VERSION 5.8 ;
BUSBITCHARS "[]" ;
DIVIDERCHAR "/" ;
UNITS
    DATABASE MICRONS 1000 ;
END UNITS

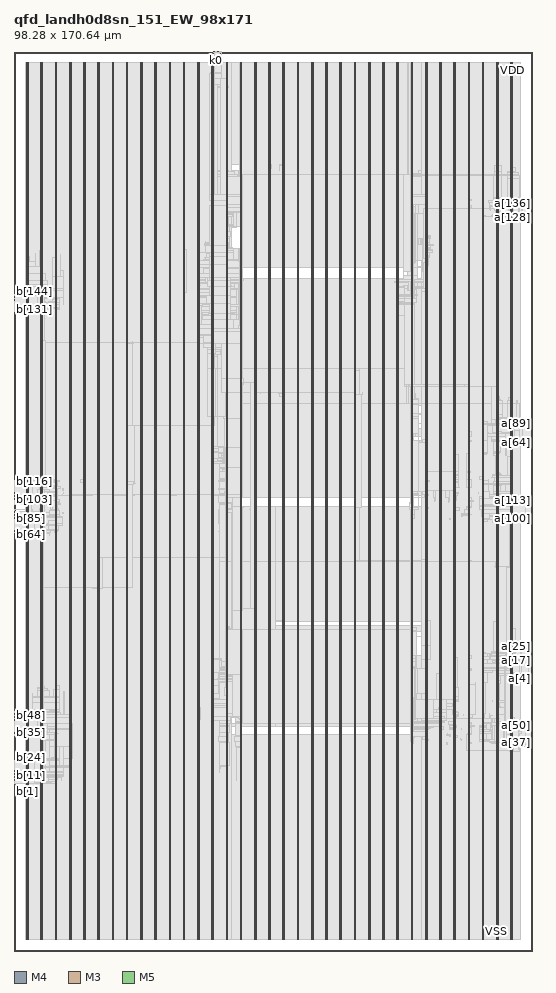
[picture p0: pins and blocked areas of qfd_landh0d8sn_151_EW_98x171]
MACRO qfd_landh0d8sn_151_EW_98x171
  FOREIGN qfd_landh0d8sn_151_EW_98x171 0 0 ;
  CLASS BLOCK ;
  SIZE 98.28 BY 170.64 ;
  PIN a[0]
    DIRECTION INPUT ;
    USE SIGNAL ;
    PORT
      LAYER M4 ;
        RECT  98.196 52.56 98.28 52.584 ;
    END
  END a[0]
  PIN a[100]
    DIRECTION INPUT ;
    USE SIGNAL ;
    PORT
      LAYER M4 ;
        RECT  98.196 81.936 98.28 81.96 ;
    END
  END a[100]
  PIN a[101]
    DIRECTION INPUT ;
    USE SIGNAL ;
    PORT
      LAYER M4 ;
        RECT  98.196 82.08 98.28 82.104 ;
    END
  END a[101]
  PIN a[102]
    DIRECTION INPUT ;
    USE SIGNAL ;
    PORT
      LAYER M4 ;
        RECT  98.196 82.224 98.28 82.248 ;
    END
  END a[102]
  PIN a[103]
    DIRECTION INPUT ;
    USE SIGNAL ;
    PORT
      LAYER M4 ;
        RECT  98.196 82.368 98.28 82.392 ;
    END
  END a[103]
  PIN a[104]
    DIRECTION INPUT ;
    USE SIGNAL ;
    PORT
      LAYER M4 ;
        RECT  98.196 82.512 98.28 82.536 ;
    END
  END a[104]
  PIN a[105]
    DIRECTION INPUT ;
    USE SIGNAL ;
    PORT
      LAYER M4 ;
        RECT  98.196 82.656 98.28 82.68 ;
    END
  END a[105]
  PIN a[106]
    DIRECTION INPUT ;
    USE SIGNAL ;
    PORT
      LAYER M4 ;
        RECT  98.196 82.8 98.28 82.824 ;
    END
  END a[106]
  PIN a[107]
    DIRECTION INPUT ;
    USE SIGNAL ;
    PORT
      LAYER M4 ;
        RECT  98.196 82.944 98.28 82.968 ;
    END
  END a[107]
  PIN a[108]
    DIRECTION INPUT ;
    USE SIGNAL ;
    PORT
      LAYER M4 ;
        RECT  98.196 83.088 98.28 83.112 ;
    END
  END a[108]
  PIN a[109]
    DIRECTION INPUT ;
    USE SIGNAL ;
    PORT
      LAYER M4 ;
        RECT  98.196 83.232 98.28 83.256 ;
    END
  END a[109]
  PIN a[10]
    DIRECTION INPUT ;
    USE SIGNAL ;
    PORT
      LAYER M4 ;
        RECT  98.196 54 98.28 54.024 ;
    END
  END a[10]
  PIN a[110]
    DIRECTION INPUT ;
    USE SIGNAL ;
    PORT
      LAYER M4 ;
        RECT  98.196 83.376 98.28 83.4 ;
    END
  END a[110]
  PIN a[111]
    DIRECTION INPUT ;
    USE SIGNAL ;
    PORT
      LAYER M4 ;
        RECT  98.196 83.52 98.28 83.544 ;
    END
  END a[111]
  PIN a[112]
    DIRECTION INPUT ;
    USE SIGNAL ;
    PORT
      LAYER M4 ;
        RECT  98.196 83.664 98.28 83.688 ;
    END
  END a[112]
  PIN a[113]
    DIRECTION INPUT ;
    USE SIGNAL ;
    PORT
      LAYER M4 ;
        RECT  98.196 83.808 98.28 83.832 ;
    END
  END a[113]
  PIN a[114]
    DIRECTION INPUT ;
    USE SIGNAL ;
    PORT
      LAYER M4 ;
        RECT  98.196 83.952 98.28 83.976 ;
    END
  END a[114]
  PIN a[115]
    DIRECTION INPUT ;
    USE SIGNAL ;
    PORT
      LAYER M4 ;
        RECT  98.196 84.096 98.28 84.12 ;
    END
  END a[115]
  PIN a[116]
    DIRECTION INPUT ;
    USE SIGNAL ;
    PORT
      LAYER M4 ;
        RECT  98.196 84.24 98.28 84.264 ;
    END
  END a[116]
  PIN a[117]
    DIRECTION INPUT ;
    USE SIGNAL ;
    PORT
      LAYER M4 ;
        RECT  98.196 84.384 98.28 84.408 ;
    END
  END a[117]
  PIN a[118]
    DIRECTION INPUT ;
    USE SIGNAL ;
    PORT
      LAYER M4 ;
        RECT  98.196 84.528 98.28 84.552 ;
    END
  END a[118]
  PIN a[119]
    DIRECTION INPUT ;
    USE SIGNAL ;
    PORT
      LAYER M4 ;
        RECT  98.196 84.672 98.28 84.696 ;
    END
  END a[119]
  PIN a[11]
    DIRECTION INPUT ;
    USE SIGNAL ;
    PORT
      LAYER M4 ;
        RECT  98.196 54.144 98.28 54.168 ;
    END
  END a[11]
  PIN a[120]
    DIRECTION INPUT ;
    USE SIGNAL ;
    PORT
      LAYER M4 ;
        RECT  98.196 84.816 98.28 84.84 ;
    END
  END a[120]
  PIN a[121]
    DIRECTION INPUT ;
    USE SIGNAL ;
    PORT
      LAYER M4 ;
        RECT  98.196 84.96 98.28 84.984 ;
    END
  END a[121]
  PIN a[122]
    DIRECTION INPUT ;
    USE SIGNAL ;
    PORT
      LAYER M4 ;
        RECT  98.196 85.104 98.28 85.128 ;
    END
  END a[122]
  PIN a[123]
    DIRECTION INPUT ;
    USE SIGNAL ;
    PORT
      LAYER M4 ;
        RECT  98.196 85.248 98.28 85.272 ;
    END
  END a[123]
  PIN a[124]
    DIRECTION INPUT ;
    USE SIGNAL ;
    PORT
      LAYER M4 ;
        RECT  98.196 85.392 98.28 85.416 ;
    END
  END a[124]
  PIN a[125]
    DIRECTION INPUT ;
    USE SIGNAL ;
    PORT
      LAYER M4 ;
        RECT  98.196 85.536 98.28 85.56 ;
    END
  END a[125]
  PIN a[126]
    DIRECTION INPUT ;
    USE SIGNAL ;
    PORT
      LAYER M4 ;
        RECT  98.196 85.68 98.28 85.704 ;
    END
  END a[126]
  PIN a[127]
    DIRECTION INPUT ;
    USE SIGNAL ;
    PORT
      LAYER M4 ;
        RECT  98.196 85.824 98.28 85.848 ;
    END
  END a[127]
  PIN a[128]
    DIRECTION INPUT ;
    USE SIGNAL ;
    PORT
      LAYER M4 ;
        RECT  98.196 139.104 98.28 139.128 ;
    END
  END a[128]
  PIN a[129]
    DIRECTION INPUT ;
    USE SIGNAL ;
    PORT
      LAYER M4 ;
        RECT  98.196 139.248 98.28 139.272 ;
    END
  END a[129]
  PIN a[12]
    DIRECTION INPUT ;
    USE SIGNAL ;
    PORT
      LAYER M4 ;
        RECT  98.196 54.288 98.28 54.312 ;
    END
  END a[12]
  PIN a[130]
    DIRECTION INPUT ;
    USE SIGNAL ;
    PORT
      LAYER M4 ;
        RECT  98.196 139.392 98.28 139.416 ;
    END
  END a[130]
  PIN a[131]
    DIRECTION INPUT ;
    USE SIGNAL ;
    PORT
      LAYER M4 ;
        RECT  98.196 139.536 98.28 139.56 ;
    END
  END a[131]
  PIN a[132]
    DIRECTION INPUT ;
    USE SIGNAL ;
    PORT
      LAYER M4 ;
        RECT  98.196 139.68 98.28 139.704 ;
    END
  END a[132]
  PIN a[133]
    DIRECTION INPUT ;
    USE SIGNAL ;
    PORT
      LAYER M4 ;
        RECT  98.196 139.824 98.28 139.848 ;
    END
  END a[133]
  PIN a[134]
    DIRECTION INPUT ;
    USE SIGNAL ;
    PORT
      LAYER M4 ;
        RECT  98.196 139.968 98.28 139.992 ;
    END
  END a[134]
  PIN a[135]
    DIRECTION INPUT ;
    USE SIGNAL ;
    PORT
      LAYER M4 ;
        RECT  98.196 140.112 98.28 140.136 ;
    END
  END a[135]
  PIN a[136]
    DIRECTION INPUT ;
    USE SIGNAL ;
    PORT
      LAYER M4 ;
        RECT  98.196 140.256 98.28 140.28 ;
    END
  END a[136]
  PIN a[137]
    DIRECTION INPUT ;
    USE SIGNAL ;
    PORT
      LAYER M4 ;
        RECT  98.196 140.4 98.28 140.424 ;
    END
  END a[137]
  PIN a[138]
    DIRECTION INPUT ;
    USE SIGNAL ;
    PORT
      LAYER M4 ;
        RECT  98.196 140.544 98.28 140.568 ;
    END
  END a[138]
  PIN a[139]
    DIRECTION INPUT ;
    USE SIGNAL ;
    PORT
      LAYER M4 ;
        RECT  98.196 140.688 98.28 140.712 ;
    END
  END a[139]
  PIN a[13]
    DIRECTION INPUT ;
    USE SIGNAL ;
    PORT
      LAYER M4 ;
        RECT  98.196 54.432 98.28 54.456 ;
    END
  END a[13]
  PIN a[140]
    DIRECTION INPUT ;
    USE SIGNAL ;
    PORT
      LAYER M4 ;
        RECT  98.196 140.832 98.28 140.856 ;
    END
  END a[140]
  PIN a[141]
    DIRECTION INPUT ;
    USE SIGNAL ;
    PORT
      LAYER M4 ;
        RECT  98.196 140.976 98.28 141 ;
    END
  END a[141]
  PIN a[142]
    DIRECTION INPUT ;
    USE SIGNAL ;
    PORT
      LAYER M4 ;
        RECT  98.196 141.12 98.28 141.144 ;
    END
  END a[142]
  PIN a[143]
    DIRECTION INPUT ;
    USE SIGNAL ;
    PORT
      LAYER M4 ;
        RECT  98.196 141.264 98.28 141.288 ;
    END
  END a[143]
  PIN a[144]
    DIRECTION INPUT ;
    USE SIGNAL ;
    PORT
      LAYER M4 ;
        RECT  98.196 141.408 98.28 141.432 ;
    END
  END a[144]
  PIN a[145]
    DIRECTION INPUT ;
    USE SIGNAL ;
    PORT
      LAYER M4 ;
        RECT  98.196 141.552 98.28 141.576 ;
    END
  END a[145]
  PIN a[146]
    DIRECTION INPUT ;
    USE SIGNAL ;
    PORT
      LAYER M4 ;
        RECT  98.196 141.696 98.28 141.72 ;
    END
  END a[146]
  PIN a[147]
    DIRECTION INPUT ;
    USE SIGNAL ;
    PORT
      LAYER M4 ;
        RECT  98.196 141.84 98.28 141.864 ;
    END
  END a[147]
  PIN a[148]
    DIRECTION INPUT ;
    USE SIGNAL ;
    PORT
      LAYER M4 ;
        RECT  98.196 141.984 98.28 142.008 ;
    END
  END a[148]
  PIN a[149]
    DIRECTION INPUT ;
    USE SIGNAL ;
    PORT
      LAYER M4 ;
        RECT  98.196 142.128 98.28 142.152 ;
    END
  END a[149]
  PIN a[14]
    DIRECTION INPUT ;
    USE SIGNAL ;
    PORT
      LAYER M4 ;
        RECT  98.196 54.576 98.28 54.6 ;
    END
  END a[14]
  PIN a[150]
    DIRECTION INPUT ;
    USE SIGNAL ;
    PORT
      LAYER M4 ;
        RECT  98.196 142.272 98.28 142.296 ;
    END
  END a[150]
  PIN a[15]
    DIRECTION INPUT ;
    USE SIGNAL ;
    PORT
      LAYER M4 ;
        RECT  98.196 54.72 98.28 54.744 ;
    END
  END a[15]
  PIN a[16]
    DIRECTION INPUT ;
    USE SIGNAL ;
    PORT
      LAYER M4 ;
        RECT  98.196 54.864 98.28 54.888 ;
    END
  END a[16]
  PIN a[17]
    DIRECTION INPUT ;
    USE SIGNAL ;
    PORT
      LAYER M4 ;
        RECT  98.196 55.008 98.28 55.032 ;
    END
  END a[17]
  PIN a[18]
    DIRECTION INPUT ;
    USE SIGNAL ;
    PORT
      LAYER M4 ;
        RECT  98.196 55.152 98.28 55.176 ;
    END
  END a[18]
  PIN a[19]
    DIRECTION INPUT ;
    USE SIGNAL ;
    PORT
      LAYER M4 ;
        RECT  98.196 55.296 98.28 55.32 ;
    END
  END a[19]
  PIN a[1]
    DIRECTION INPUT ;
    USE SIGNAL ;
    PORT
      LAYER M4 ;
        RECT  98.196 52.704 98.28 52.728 ;
    END
  END a[1]
  PIN a[20]
    DIRECTION INPUT ;
    USE SIGNAL ;
    PORT
      LAYER M4 ;
        RECT  98.196 55.44 98.28 55.464 ;
    END
  END a[20]
  PIN a[21]
    DIRECTION INPUT ;
    USE SIGNAL ;
    PORT
      LAYER M4 ;
        RECT  98.196 55.584 98.28 55.608 ;
    END
  END a[21]
  PIN a[22]
    DIRECTION INPUT ;
    USE SIGNAL ;
    PORT
      LAYER M4 ;
        RECT  98.196 55.728 98.28 55.752 ;
    END
  END a[22]
  PIN a[23]
    DIRECTION INPUT ;
    USE SIGNAL ;
    PORT
      LAYER M4 ;
        RECT  98.196 55.872 98.28 55.896 ;
    END
  END a[23]
  PIN a[24]
    DIRECTION INPUT ;
    USE SIGNAL ;
    PORT
      LAYER M4 ;
        RECT  98.196 56.016 98.28 56.04 ;
    END
  END a[24]
  PIN a[25]
    DIRECTION INPUT ;
    USE SIGNAL ;
    PORT
      LAYER M4 ;
        RECT  98.196 56.16 98.28 56.184 ;
    END
  END a[25]
  PIN a[26]
    DIRECTION INPUT ;
    USE SIGNAL ;
    PORT
      LAYER M4 ;
        RECT  98.196 56.304 98.28 56.328 ;
    END
  END a[26]
  PIN a[27]
    DIRECTION INPUT ;
    USE SIGNAL ;
    PORT
      LAYER M4 ;
        RECT  98.196 56.448 98.28 56.472 ;
    END
  END a[27]
  PIN a[28]
    DIRECTION INPUT ;
    USE SIGNAL ;
    PORT
      LAYER M4 ;
        RECT  98.196 56.592 98.28 56.616 ;
    END
  END a[28]
  PIN a[29]
    DIRECTION INPUT ;
    USE SIGNAL ;
    PORT
      LAYER M4 ;
        RECT  98.196 56.736 98.28 56.76 ;
    END
  END a[29]
  PIN a[2]
    DIRECTION INPUT ;
    USE SIGNAL ;
    PORT
      LAYER M4 ;
        RECT  98.196 52.848 98.28 52.872 ;
    END
  END a[2]
  PIN a[30]
    DIRECTION INPUT ;
    USE SIGNAL ;
    PORT
      LAYER M4 ;
        RECT  98.196 56.88 98.28 56.904 ;
    END
  END a[30]
  PIN a[31]
    DIRECTION INPUT ;
    USE SIGNAL ;
    PORT
      LAYER M4 ;
        RECT  98.196 57.024 98.28 57.048 ;
    END
  END a[31]
  PIN a[32]
    DIRECTION INPUT ;
    USE SIGNAL ;
    PORT
      LAYER M4 ;
        RECT  98.196 38.736 98.28 38.76 ;
    END
  END a[32]
  PIN a[33]
    DIRECTION INPUT ;
    USE SIGNAL ;
    PORT
      LAYER M4 ;
        RECT  98.196 38.88 98.28 38.904 ;
    END
  END a[33]
  PIN a[34]
    DIRECTION INPUT ;
    USE SIGNAL ;
    PORT
      LAYER M4 ;
        RECT  98.196 39.024 98.28 39.048 ;
    END
  END a[34]
  PIN a[35]
    DIRECTION INPUT ;
    USE SIGNAL ;
    PORT
      LAYER M4 ;
        RECT  98.196 39.168 98.28 39.192 ;
    END
  END a[35]
  PIN a[36]
    DIRECTION INPUT ;
    USE SIGNAL ;
    PORT
      LAYER M4 ;
        RECT  98.196 39.312 98.28 39.336 ;
    END
  END a[36]
  PIN a[37]
    DIRECTION INPUT ;
    USE SIGNAL ;
    PORT
      LAYER M4 ;
        RECT  98.196 39.456 98.28 39.48 ;
    END
  END a[37]
  PIN a[38]
    DIRECTION INPUT ;
    USE SIGNAL ;
    PORT
      LAYER M4 ;
        RECT  98.196 39.6 98.28 39.624 ;
    END
  END a[38]
  PIN a[39]
    DIRECTION INPUT ;
    USE SIGNAL ;
    PORT
      LAYER M4 ;
        RECT  98.196 39.744 98.28 39.768 ;
    END
  END a[39]
  PIN a[3]
    DIRECTION INPUT ;
    USE SIGNAL ;
    PORT
      LAYER M4 ;
        RECT  98.196 52.992 98.28 53.016 ;
    END
  END a[3]
  PIN a[40]
    DIRECTION INPUT ;
    USE SIGNAL ;
    PORT
      LAYER M4 ;
        RECT  98.196 39.888 98.28 39.912 ;
    END
  END a[40]
  PIN a[41]
    DIRECTION INPUT ;
    USE SIGNAL ;
    PORT
      LAYER M4 ;
        RECT  98.196 40.032 98.28 40.056 ;
    END
  END a[41]
  PIN a[42]
    DIRECTION INPUT ;
    USE SIGNAL ;
    PORT
      LAYER M4 ;
        RECT  98.196 40.176 98.28 40.2 ;
    END
  END a[42]
  PIN a[43]
    DIRECTION INPUT ;
    USE SIGNAL ;
    PORT
      LAYER M4 ;
        RECT  98.196 40.32 98.28 40.344 ;
    END
  END a[43]
  PIN a[44]
    DIRECTION INPUT ;
    USE SIGNAL ;
    PORT
      LAYER M4 ;
        RECT  98.196 40.464 98.28 40.488 ;
    END
  END a[44]
  PIN a[45]
    DIRECTION INPUT ;
    USE SIGNAL ;
    PORT
      LAYER M4 ;
        RECT  98.196 40.608 98.28 40.632 ;
    END
  END a[45]
  PIN a[46]
    DIRECTION INPUT ;
    USE SIGNAL ;
    PORT
      LAYER M4 ;
        RECT  98.196 40.752 98.28 40.776 ;
    END
  END a[46]
  PIN a[47]
    DIRECTION INPUT ;
    USE SIGNAL ;
    PORT
      LAYER M4 ;
        RECT  98.196 40.896 98.28 40.92 ;
    END
  END a[47]
  PIN a[48]
    DIRECTION INPUT ;
    USE SIGNAL ;
    PORT
      LAYER M4 ;
        RECT  98.196 41.04 98.28 41.064 ;
    END
  END a[48]
  PIN a[49]
    DIRECTION INPUT ;
    USE SIGNAL ;
    PORT
      LAYER M4 ;
        RECT  98.196 41.184 98.28 41.208 ;
    END
  END a[49]
  PIN a[4]
    DIRECTION INPUT ;
    USE SIGNAL ;
    PORT
      LAYER M4 ;
        RECT  98.196 53.136 98.28 53.16 ;
    END
  END a[4]
  PIN a[50]
    DIRECTION INPUT ;
    USE SIGNAL ;
    PORT
      LAYER M4 ;
        RECT  98.196 41.328 98.28 41.352 ;
    END
  END a[50]
  PIN a[51]
    DIRECTION INPUT ;
    USE SIGNAL ;
    PORT
      LAYER M4 ;
        RECT  98.196 41.472 98.28 41.496 ;
    END
  END a[51]
  PIN a[52]
    DIRECTION INPUT ;
    USE SIGNAL ;
    PORT
      LAYER M4 ;
        RECT  98.196 41.616 98.28 41.64 ;
    END
  END a[52]
  PIN a[53]
    DIRECTION INPUT ;
    USE SIGNAL ;
    PORT
      LAYER M4 ;
        RECT  98.196 41.76 98.28 41.784 ;
    END
  END a[53]
  PIN a[54]
    DIRECTION INPUT ;
    USE SIGNAL ;
    PORT
      LAYER M4 ;
        RECT  98.196 41.904 98.28 41.928 ;
    END
  END a[54]
  PIN a[55]
    DIRECTION INPUT ;
    USE SIGNAL ;
    PORT
      LAYER M4 ;
        RECT  98.196 42.048 98.28 42.072 ;
    END
  END a[55]
  PIN a[56]
    DIRECTION INPUT ;
    USE SIGNAL ;
    PORT
      LAYER M4 ;
        RECT  98.196 42.192 98.28 42.216 ;
    END
  END a[56]
  PIN a[57]
    DIRECTION INPUT ;
    USE SIGNAL ;
    PORT
      LAYER M4 ;
        RECT  98.196 42.336 98.28 42.36 ;
    END
  END a[57]
  PIN a[58]
    DIRECTION INPUT ;
    USE SIGNAL ;
    PORT
      LAYER M4 ;
        RECT  98.196 42.48 98.28 42.504 ;
    END
  END a[58]
  PIN a[59]
    DIRECTION INPUT ;
    USE SIGNAL ;
    PORT
      LAYER M4 ;
        RECT  98.196 42.624 98.28 42.648 ;
    END
  END a[59]
  PIN a[5]
    DIRECTION INPUT ;
    USE SIGNAL ;
    PORT
      LAYER M4 ;
        RECT  98.196 53.28 98.28 53.304 ;
    END
  END a[5]
  PIN a[60]
    DIRECTION INPUT ;
    USE SIGNAL ;
    PORT
      LAYER M4 ;
        RECT  98.196 42.768 98.28 42.792 ;
    END
  END a[60]
  PIN a[61]
    DIRECTION INPUT ;
    USE SIGNAL ;
    PORT
      LAYER M4 ;
        RECT  98.196 42.912 98.28 42.936 ;
    END
  END a[61]
  PIN a[62]
    DIRECTION INPUT ;
    USE SIGNAL ;
    PORT
      LAYER M4 ;
        RECT  98.196 43.056 98.28 43.08 ;
    END
  END a[62]
  PIN a[63]
    DIRECTION INPUT ;
    USE SIGNAL ;
    PORT
      LAYER M4 ;
        RECT  98.196 43.2 98.28 43.224 ;
    END
  END a[63]
  PIN a[64]
    DIRECTION INPUT ;
    USE SIGNAL ;
    PORT
      LAYER M4 ;
        RECT  98.196 96.336 98.28 96.36 ;
    END
  END a[64]
  PIN a[65]
    DIRECTION INPUT ;
    USE SIGNAL ;
    PORT
      LAYER M4 ;
        RECT  98.196 96.48 98.28 96.504 ;
    END
  END a[65]
  PIN a[66]
    DIRECTION INPUT ;
    USE SIGNAL ;
    PORT
      LAYER M4 ;
        RECT  98.196 96.624 98.28 96.648 ;
    END
  END a[66]
  PIN a[67]
    DIRECTION INPUT ;
    USE SIGNAL ;
    PORT
      LAYER M4 ;
        RECT  98.196 96.768 98.28 96.792 ;
    END
  END a[67]
  PIN a[68]
    DIRECTION INPUT ;
    USE SIGNAL ;
    PORT
      LAYER M4 ;
        RECT  98.196 96.912 98.28 96.936 ;
    END
  END a[68]
  PIN a[69]
    DIRECTION INPUT ;
    USE SIGNAL ;
    PORT
      LAYER M4 ;
        RECT  98.196 97.056 98.28 97.08 ;
    END
  END a[69]
  PIN a[6]
    DIRECTION INPUT ;
    USE SIGNAL ;
    PORT
      LAYER M4 ;
        RECT  98.196 53.424 98.28 53.448 ;
    END
  END a[6]
  PIN a[70]
    DIRECTION INPUT ;
    USE SIGNAL ;
    PORT
      LAYER M4 ;
        RECT  98.196 97.2 98.28 97.224 ;
    END
  END a[70]
  PIN a[71]
    DIRECTION INPUT ;
    USE SIGNAL ;
    PORT
      LAYER M4 ;
        RECT  98.196 97.344 98.28 97.368 ;
    END
  END a[71]
  PIN a[72]
    DIRECTION INPUT ;
    USE SIGNAL ;
    PORT
      LAYER M4 ;
        RECT  98.196 97.488 98.28 97.512 ;
    END
  END a[72]
  PIN a[73]
    DIRECTION INPUT ;
    USE SIGNAL ;
    PORT
      LAYER M4 ;
        RECT  98.196 97.632 98.28 97.656 ;
    END
  END a[73]
  PIN a[74]
    DIRECTION INPUT ;
    USE SIGNAL ;
    PORT
      LAYER M4 ;
        RECT  98.196 97.776 98.28 97.8 ;
    END
  END a[74]
  PIN a[75]
    DIRECTION INPUT ;
    USE SIGNAL ;
    PORT
      LAYER M4 ;
        RECT  98.196 97.92 98.28 97.944 ;
    END
  END a[75]
  PIN a[76]
    DIRECTION INPUT ;
    USE SIGNAL ;
    PORT
      LAYER M4 ;
        RECT  98.196 98.064 98.28 98.088 ;
    END
  END a[76]
  PIN a[77]
    DIRECTION INPUT ;
    USE SIGNAL ;
    PORT
      LAYER M4 ;
        RECT  98.196 98.208 98.28 98.232 ;
    END
  END a[77]
  PIN a[78]
    DIRECTION INPUT ;
    USE SIGNAL ;
    PORT
      LAYER M4 ;
        RECT  98.196 98.352 98.28 98.376 ;
    END
  END a[78]
  PIN a[79]
    DIRECTION INPUT ;
    USE SIGNAL ;
    PORT
      LAYER M4 ;
        RECT  98.196 98.496 98.28 98.52 ;
    END
  END a[79]
  PIN a[7]
    DIRECTION INPUT ;
    USE SIGNAL ;
    PORT
      LAYER M4 ;
        RECT  98.196 53.568 98.28 53.592 ;
    END
  END a[7]
  PIN a[80]
    DIRECTION INPUT ;
    USE SIGNAL ;
    PORT
      LAYER M4 ;
        RECT  98.196 98.64 98.28 98.664 ;
    END
  END a[80]
  PIN a[81]
    DIRECTION INPUT ;
    USE SIGNAL ;
    PORT
      LAYER M4 ;
        RECT  98.196 98.784 98.28 98.808 ;
    END
  END a[81]
  PIN a[82]
    DIRECTION INPUT ;
    USE SIGNAL ;
    PORT
      LAYER M4 ;
        RECT  98.196 98.928 98.28 98.952 ;
    END
  END a[82]
  PIN a[83]
    DIRECTION INPUT ;
    USE SIGNAL ;
    PORT
      LAYER M4 ;
        RECT  98.196 99.072 98.28 99.096 ;
    END
  END a[83]
  PIN a[84]
    DIRECTION INPUT ;
    USE SIGNAL ;
    PORT
      LAYER M4 ;
        RECT  98.196 99.216 98.28 99.24 ;
    END
  END a[84]
  PIN a[85]
    DIRECTION INPUT ;
    USE SIGNAL ;
    PORT
      LAYER M4 ;
        RECT  98.196 99.36 98.28 99.384 ;
    END
  END a[85]
  PIN a[86]
    DIRECTION INPUT ;
    USE SIGNAL ;
    PORT
      LAYER M4 ;
        RECT  98.196 99.504 98.28 99.528 ;
    END
  END a[86]
  PIN a[87]
    DIRECTION INPUT ;
    USE SIGNAL ;
    PORT
      LAYER M4 ;
        RECT  98.196 99.648 98.28 99.672 ;
    END
  END a[87]
  PIN a[88]
    DIRECTION INPUT ;
    USE SIGNAL ;
    PORT
      LAYER M4 ;
        RECT  98.196 99.792 98.28 99.816 ;
    END
  END a[88]
  PIN a[89]
    DIRECTION INPUT ;
    USE SIGNAL ;
    PORT
      LAYER M4 ;
        RECT  98.196 99.936 98.28 99.96 ;
    END
  END a[89]
  PIN a[8]
    DIRECTION INPUT ;
    USE SIGNAL ;
    PORT
      LAYER M4 ;
        RECT  98.196 53.712 98.28 53.736 ;
    END
  END a[8]
  PIN a[90]
    DIRECTION INPUT ;
    USE SIGNAL ;
    PORT
      LAYER M4 ;
        RECT  98.196 100.08 98.28 100.104 ;
    END
  END a[90]
  PIN a[91]
    DIRECTION INPUT ;
    USE SIGNAL ;
    PORT
      LAYER M4 ;
        RECT  98.196 100.224 98.28 100.248 ;
    END
  END a[91]
  PIN a[92]
    DIRECTION INPUT ;
    USE SIGNAL ;
    PORT
      LAYER M4 ;
        RECT  98.196 100.368 98.28 100.392 ;
    END
  END a[92]
  PIN a[93]
    DIRECTION INPUT ;
    USE SIGNAL ;
    PORT
      LAYER M4 ;
        RECT  98.196 100.512 98.28 100.536 ;
    END
  END a[93]
  PIN a[94]
    DIRECTION INPUT ;
    USE SIGNAL ;
    PORT
      LAYER M4 ;
        RECT  98.196 100.656 98.28 100.68 ;
    END
  END a[94]
  PIN a[95]
    DIRECTION INPUT ;
    USE SIGNAL ;
    PORT
      LAYER M4 ;
        RECT  98.196 100.8 98.28 100.824 ;
    END
  END a[95]
  PIN a[96]
    DIRECTION INPUT ;
    USE SIGNAL ;
    PORT
      LAYER M4 ;
        RECT  98.196 81.36 98.28 81.384 ;
    END
  END a[96]
  PIN a[97]
    DIRECTION INPUT ;
    USE SIGNAL ;
    PORT
      LAYER M4 ;
        RECT  98.196 81.504 98.28 81.528 ;
    END
  END a[97]
  PIN a[98]
    DIRECTION INPUT ;
    USE SIGNAL ;
    PORT
      LAYER M4 ;
        RECT  98.196 81.648 98.28 81.672 ;
    END
  END a[98]
  PIN a[99]
    DIRECTION INPUT ;
    USE SIGNAL ;
    PORT
      LAYER M4 ;
        RECT  98.196 81.792 98.28 81.816 ;
    END
  END a[99]
  PIN a[9]
    DIRECTION INPUT ;
    USE SIGNAL ;
    PORT
      LAYER M4 ;
        RECT  98.196 53.856 98.28 53.88 ;
    END
  END a[9]
  PIN b[0]
    DIRECTION OUTPUT ;
    USE SIGNAL ;
    PORT
      LAYER M4 ;
        RECT  0 31.68 0.084 31.704 ;
    END
  END b[0]
  PIN b[100]
    DIRECTION OUTPUT ;
    USE SIGNAL ;
    PORT
      LAYER M4 ;
        RECT  0 85.248 0.084 85.272 ;
    END
  END b[100]
  PIN b[101]
    DIRECTION OUTPUT ;
    USE SIGNAL ;
    PORT
      LAYER M4 ;
        RECT  0 85.392 0.084 85.416 ;
    END
  END b[101]
  PIN b[102]
    DIRECTION OUTPUT ;
    USE SIGNAL ;
    PORT
      LAYER M4 ;
        RECT  0 85.536 0.084 85.56 ;
    END
  END b[102]
  PIN b[103]
    DIRECTION OUTPUT ;
    USE SIGNAL ;
    PORT
      LAYER M4 ;
        RECT  0 85.68 0.084 85.704 ;
    END
  END b[103]
  PIN b[104]
    DIRECTION OUTPUT ;
    USE SIGNAL ;
    PORT
      LAYER M4 ;
        RECT  0 85.824 0.084 85.848 ;
    END
  END b[104]
  PIN b[105]
    DIRECTION OUTPUT ;
    USE SIGNAL ;
    PORT
      LAYER M4 ;
        RECT  0 85.968 0.084 85.992 ;
    END
  END b[105]
  PIN b[106]
    DIRECTION OUTPUT ;
    USE SIGNAL ;
    PORT
      LAYER M4 ;
        RECT  0 86.112 0.084 86.136 ;
    END
  END b[106]
  PIN b[107]
    DIRECTION OUTPUT ;
    USE SIGNAL ;
    PORT
      LAYER M4 ;
        RECT  0 86.256 0.084 86.28 ;
    END
  END b[107]
  PIN b[108]
    DIRECTION OUTPUT ;
    USE SIGNAL ;
    PORT
      LAYER M4 ;
        RECT  0 86.4 0.084 86.424 ;
    END
  END b[108]
  PIN b[109]
    DIRECTION OUTPUT ;
    USE SIGNAL ;
    PORT
      LAYER M4 ;
        RECT  0 86.544 0.084 86.568 ;
    END
  END b[109]
  PIN b[10]
    DIRECTION OUTPUT ;
    USE SIGNAL ;
    PORT
      LAYER M4 ;
        RECT  0 33.12 0.084 33.144 ;
    END
  END b[10]
  PIN b[110]
    DIRECTION OUTPUT ;
    USE SIGNAL ;
    PORT
      LAYER M4 ;
        RECT  0 86.688 0.084 86.712 ;
    END
  END b[110]
  PIN b[111]
    DIRECTION OUTPUT ;
    USE SIGNAL ;
    PORT
      LAYER M4 ;
        RECT  0 86.832 0.084 86.856 ;
    END
  END b[111]
  PIN b[112]
    DIRECTION OUTPUT ;
    USE SIGNAL ;
    PORT
      LAYER M4 ;
        RECT  0 86.976 0.084 87 ;
    END
  END b[112]
  PIN b[113]
    DIRECTION OUTPUT ;
    USE SIGNAL ;
    PORT
      LAYER M4 ;
        RECT  0 87.12 0.084 87.144 ;
    END
  END b[113]
  PIN b[114]
    DIRECTION OUTPUT ;
    USE SIGNAL ;
    PORT
      LAYER M4 ;
        RECT  0 87.264 0.084 87.288 ;
    END
  END b[114]
  PIN b[115]
    DIRECTION OUTPUT ;
    USE SIGNAL ;
    PORT
      LAYER M4 ;
        RECT  0 87.408 0.084 87.432 ;
    END
  END b[115]
  PIN b[116]
    DIRECTION OUTPUT ;
    USE SIGNAL ;
    PORT
      LAYER M4 ;
        RECT  0 87.552 0.084 87.576 ;
    END
  END b[116]
  PIN b[117]
    DIRECTION OUTPUT ;
    USE SIGNAL ;
    PORT
      LAYER M4 ;
        RECT  0 87.696 0.084 87.72 ;
    END
  END b[117]
  PIN b[118]
    DIRECTION OUTPUT ;
    USE SIGNAL ;
    PORT
      LAYER M4 ;
        RECT  0 87.84 0.084 87.864 ;
    END
  END b[118]
  PIN b[119]
    DIRECTION OUTPUT ;
    USE SIGNAL ;
    PORT
      LAYER M4 ;
        RECT  0 87.984 0.084 88.008 ;
    END
  END b[119]
  PIN b[11]
    DIRECTION OUTPUT ;
    USE SIGNAL ;
    PORT
      LAYER M4 ;
        RECT  0 33.264 0.084 33.288 ;
    END
  END b[11]
  PIN b[120]
    DIRECTION OUTPUT ;
    USE SIGNAL ;
    PORT
      LAYER M4 ;
        RECT  0 88.128 0.084 88.152 ;
    END
  END b[120]
  PIN b[121]
    DIRECTION OUTPUT ;
    USE SIGNAL ;
    PORT
      LAYER M4 ;
        RECT  0 88.272 0.084 88.296 ;
    END
  END b[121]
  PIN b[122]
    DIRECTION OUTPUT ;
    USE SIGNAL ;
    PORT
      LAYER M4 ;
        RECT  0 88.416 0.084 88.44 ;
    END
  END b[122]
  PIN b[123]
    DIRECTION OUTPUT ;
    USE SIGNAL ;
    PORT
      LAYER M4 ;
        RECT  0 88.56 0.084 88.584 ;
    END
  END b[123]
  PIN b[124]
    DIRECTION OUTPUT ;
    USE SIGNAL ;
    PORT
      LAYER M4 ;
        RECT  0 88.704 0.084 88.728 ;
    END
  END b[124]
  PIN b[125]
    DIRECTION OUTPUT ;
    USE SIGNAL ;
    PORT
      LAYER M4 ;
        RECT  0 88.848 0.084 88.872 ;
    END
  END b[125]
  PIN b[126]
    DIRECTION OUTPUT ;
    USE SIGNAL ;
    PORT
      LAYER M4 ;
        RECT  0 88.992 0.084 89.016 ;
    END
  END b[126]
  PIN b[127]
    DIRECTION OUTPUT ;
    USE SIGNAL ;
    PORT
      LAYER M4 ;
        RECT  0 89.136 0.084 89.16 ;
    END
  END b[127]
  PIN b[128]
    DIRECTION OUTPUT ;
    USE SIGNAL ;
    PORT
      LAYER M4 ;
        RECT  0 121.248 0.084 121.272 ;
    END
  END b[128]
  PIN b[129]
    DIRECTION OUTPUT ;
    USE SIGNAL ;
    PORT
      LAYER M4 ;
        RECT  0 121.392 0.084 121.416 ;
    END
  END b[129]
  PIN b[12]
    DIRECTION OUTPUT ;
    USE SIGNAL ;
    PORT
      LAYER M4 ;
        RECT  0 33.408 0.084 33.432 ;
    END
  END b[12]
  PIN b[130]
    DIRECTION OUTPUT ;
    USE SIGNAL ;
    PORT
      LAYER M4 ;
        RECT  0 121.536 0.084 121.56 ;
    END
  END b[130]
  PIN b[131]
    DIRECTION OUTPUT ;
    USE SIGNAL ;
    PORT
      LAYER M4 ;
        RECT  0 121.68 0.084 121.704 ;
    END
  END b[131]
  PIN b[132]
    DIRECTION OUTPUT ;
    USE SIGNAL ;
    PORT
      LAYER M4 ;
        RECT  0 121.824 0.084 121.848 ;
    END
  END b[132]
  PIN b[133]
    DIRECTION OUTPUT ;
    USE SIGNAL ;
    PORT
      LAYER M4 ;
        RECT  0 121.968 0.084 121.992 ;
    END
  END b[133]
  PIN b[134]
    DIRECTION OUTPUT ;
    USE SIGNAL ;
    PORT
      LAYER M4 ;
        RECT  0 122.112 0.084 122.136 ;
    END
  END b[134]
  PIN b[135]
    DIRECTION OUTPUT ;
    USE SIGNAL ;
    PORT
      LAYER M4 ;
        RECT  0 122.256 0.084 122.28 ;
    END
  END b[135]
  PIN b[136]
    DIRECTION OUTPUT ;
    USE SIGNAL ;
    PORT
      LAYER M4 ;
        RECT  0 122.4 0.084 122.424 ;
    END
  END b[136]
  PIN b[137]
    DIRECTION OUTPUT ;
    USE SIGNAL ;
    PORT
      LAYER M4 ;
        RECT  0 122.544 0.084 122.568 ;
    END
  END b[137]
  PIN b[138]
    DIRECTION OUTPUT ;
    USE SIGNAL ;
    PORT
      LAYER M4 ;
        RECT  0 122.688 0.084 122.712 ;
    END
  END b[138]
  PIN b[139]
    DIRECTION OUTPUT ;
    USE SIGNAL ;
    PORT
      LAYER M4 ;
        RECT  0 122.832 0.084 122.856 ;
    END
  END b[139]
  PIN b[13]
    DIRECTION OUTPUT ;
    USE SIGNAL ;
    PORT
      LAYER M4 ;
        RECT  0 33.552 0.084 33.576 ;
    END
  END b[13]
  PIN b[140]
    DIRECTION OUTPUT ;
    USE SIGNAL ;
    PORT
      LAYER M4 ;
        RECT  0 122.976 0.084 123 ;
    END
  END b[140]
  PIN b[141]
    DIRECTION OUTPUT ;
    USE SIGNAL ;
    PORT
      LAYER M4 ;
        RECT  0 123.12 0.084 123.144 ;
    END
  END b[141]
  PIN b[142]
    DIRECTION OUTPUT ;
    USE SIGNAL ;
    PORT
      LAYER M4 ;
        RECT  0 123.264 0.084 123.288 ;
    END
  END b[142]
  PIN b[143]
    DIRECTION OUTPUT ;
    USE SIGNAL ;
    PORT
      LAYER M4 ;
        RECT  0 123.408 0.084 123.432 ;
    END
  END b[143]
  PIN b[144]
    DIRECTION OUTPUT ;
    USE SIGNAL ;
    PORT
      LAYER M4 ;
        RECT  0 123.552 0.084 123.576 ;
    END
  END b[144]
  PIN b[145]
    DIRECTION OUTPUT ;
    USE SIGNAL ;
    PORT
      LAYER M4 ;
        RECT  0 123.696 0.084 123.72 ;
    END
  END b[145]
  PIN b[146]
    DIRECTION OUTPUT ;
    USE SIGNAL ;
    PORT
      LAYER M4 ;
        RECT  0 123.84 0.084 123.864 ;
    END
  END b[146]
  PIN b[147]
    DIRECTION OUTPUT ;
    USE SIGNAL ;
    PORT
      LAYER M4 ;
        RECT  0 123.984 0.084 124.008 ;
    END
  END b[147]
  PIN b[148]
    DIRECTION OUTPUT ;
    USE SIGNAL ;
    PORT
      LAYER M4 ;
        RECT  0 124.128 0.084 124.152 ;
    END
  END b[148]
  PIN b[149]
    DIRECTION OUTPUT ;
    USE SIGNAL ;
    PORT
      LAYER M4 ;
        RECT  0 124.272 0.084 124.296 ;
    END
  END b[149]
  PIN b[14]
    DIRECTION OUTPUT ;
    USE SIGNAL ;
    PORT
      LAYER M4 ;
        RECT  0 33.696 0.084 33.72 ;
    END
  END b[14]
  PIN b[150]
    DIRECTION OUTPUT ;
    USE SIGNAL ;
    PORT
      LAYER M4 ;
        RECT  0 124.416 0.084 124.44 ;
    END
  END b[150]
  PIN b[15]
    DIRECTION OUTPUT ;
    USE SIGNAL ;
    PORT
      LAYER M4 ;
        RECT  0 33.84 0.084 33.864 ;
    END
  END b[15]
  PIN b[16]
    DIRECTION OUTPUT ;
    USE SIGNAL ;
    PORT
      LAYER M4 ;
        RECT  0 33.984 0.084 34.008 ;
    END
  END b[16]
  PIN b[17]
    DIRECTION OUTPUT ;
    USE SIGNAL ;
    PORT
      LAYER M4 ;
        RECT  0 34.128 0.084 34.152 ;
    END
  END b[17]
  PIN b[18]
    DIRECTION OUTPUT ;
    USE SIGNAL ;
    PORT
      LAYER M4 ;
        RECT  0 34.272 0.084 34.296 ;
    END
  END b[18]
  PIN b[19]
    DIRECTION OUTPUT ;
    USE SIGNAL ;
    PORT
      LAYER M4 ;
        RECT  0 34.416 0.084 34.44 ;
    END
  END b[19]
  PIN b[1]
    DIRECTION OUTPUT ;
    USE SIGNAL ;
    PORT
      LAYER M4 ;
        RECT  0 31.824 0.084 31.848 ;
    END
  END b[1]
  PIN b[20]
    DIRECTION OUTPUT ;
    USE SIGNAL ;
    PORT
      LAYER M4 ;
        RECT  0 34.56 0.084 34.584 ;
    END
  END b[20]
  PIN b[21]
    DIRECTION OUTPUT ;
    USE SIGNAL ;
    PORT
      LAYER M4 ;
        RECT  0 34.704 0.084 34.728 ;
    END
  END b[21]
  PIN b[22]
    DIRECTION OUTPUT ;
    USE SIGNAL ;
    PORT
      LAYER M4 ;
        RECT  0 34.848 0.084 34.872 ;
    END
  END b[22]
  PIN b[23]
    DIRECTION OUTPUT ;
    USE SIGNAL ;
    PORT
      LAYER M4 ;
        RECT  0 34.992 0.084 35.016 ;
    END
  END b[23]
  PIN b[24]
    DIRECTION OUTPUT ;
    USE SIGNAL ;
    PORT
      LAYER M4 ;
        RECT  0 35.136 0.084 35.16 ;
    END
  END b[24]
  PIN b[25]
    DIRECTION OUTPUT ;
    USE SIGNAL ;
    PORT
      LAYER M4 ;
        RECT  0 35.28 0.084 35.304 ;
    END
  END b[25]
  PIN b[26]
    DIRECTION OUTPUT ;
    USE SIGNAL ;
    PORT
      LAYER M4 ;
        RECT  0 35.424 0.084 35.448 ;
    END
  END b[26]
  PIN b[27]
    DIRECTION OUTPUT ;
    USE SIGNAL ;
    PORT
      LAYER M4 ;
        RECT  0 35.568 0.084 35.592 ;
    END
  END b[27]
  PIN b[28]
    DIRECTION OUTPUT ;
    USE SIGNAL ;
    PORT
      LAYER M4 ;
        RECT  0 35.712 0.084 35.736 ;
    END
  END b[28]
  PIN b[29]
    DIRECTION OUTPUT ;
    USE SIGNAL ;
    PORT
      LAYER M4 ;
        RECT  0 35.856 0.084 35.88 ;
    END
  END b[29]
  PIN b[2]
    DIRECTION OUTPUT ;
    USE SIGNAL ;
    PORT
      LAYER M4 ;
        RECT  0 31.968 0.084 31.992 ;
    END
  END b[2]
  PIN b[30]
    DIRECTION OUTPUT ;
    USE SIGNAL ;
    PORT
      LAYER M4 ;
        RECT  0 36 0.084 36.024 ;
    END
  END b[30]
  PIN b[31]
    DIRECTION OUTPUT ;
    USE SIGNAL ;
    PORT
      LAYER M4 ;
        RECT  0 36.144 0.084 36.168 ;
    END
  END b[31]
  PIN b[32]
    DIRECTION OUTPUT ;
    USE SIGNAL ;
    PORT
      LAYER M4 ;
        RECT  0 40.896 0.084 40.92 ;
    END
  END b[32]
  PIN b[33]
    DIRECTION OUTPUT ;
    USE SIGNAL ;
    PORT
      LAYER M4 ;
        RECT  0 41.04 0.084 41.064 ;
    END
  END b[33]
  PIN b[34]
    DIRECTION OUTPUT ;
    USE SIGNAL ;
    PORT
      LAYER M4 ;
        RECT  0 41.184 0.084 41.208 ;
    END
  END b[34]
  PIN b[35]
    DIRECTION OUTPUT ;
    USE SIGNAL ;
    PORT
      LAYER M4 ;
        RECT  0 41.328 0.084 41.352 ;
    END
  END b[35]
  PIN b[36]
    DIRECTION OUTPUT ;
    USE SIGNAL ;
    PORT
      LAYER M4 ;
        RECT  0 41.472 0.084 41.496 ;
    END
  END b[36]
  PIN b[37]
    DIRECTION OUTPUT ;
    USE SIGNAL ;
    PORT
      LAYER M4 ;
        RECT  0 41.616 0.084 41.64 ;
    END
  END b[37]
  PIN b[38]
    DIRECTION OUTPUT ;
    USE SIGNAL ;
    PORT
      LAYER M4 ;
        RECT  0 41.76 0.084 41.784 ;
    END
  END b[38]
  PIN b[39]
    DIRECTION OUTPUT ;
    USE SIGNAL ;
    PORT
      LAYER M4 ;
        RECT  0 41.904 0.084 41.928 ;
    END
  END b[39]
  PIN b[3]
    DIRECTION OUTPUT ;
    USE SIGNAL ;
    PORT
      LAYER M4 ;
        RECT  0 32.112 0.084 32.136 ;
    END
  END b[3]
  PIN b[40]
    DIRECTION OUTPUT ;
    USE SIGNAL ;
    PORT
      LAYER M4 ;
        RECT  0 42.048 0.084 42.072 ;
    END
  END b[40]
  PIN b[41]
    DIRECTION OUTPUT ;
    USE SIGNAL ;
    PORT
      LAYER M4 ;
        RECT  0 42.192 0.084 42.216 ;
    END
  END b[41]
  PIN b[42]
    DIRECTION OUTPUT ;
    USE SIGNAL ;
    PORT
      LAYER M4 ;
        RECT  0 42.336 0.084 42.36 ;
    END
  END b[42]
  PIN b[43]
    DIRECTION OUTPUT ;
    USE SIGNAL ;
    PORT
      LAYER M4 ;
        RECT  0 42.48 0.084 42.504 ;
    END
  END b[43]
  PIN b[44]
    DIRECTION OUTPUT ;
    USE SIGNAL ;
    PORT
      LAYER M4 ;
        RECT  0 42.624 0.084 42.648 ;
    END
  END b[44]
  PIN b[45]
    DIRECTION OUTPUT ;
    USE SIGNAL ;
    PORT
      LAYER M4 ;
        RECT  0 42.768 0.084 42.792 ;
    END
  END b[45]
  PIN b[46]
    DIRECTION OUTPUT ;
    USE SIGNAL ;
    PORT
      LAYER M4 ;
        RECT  0 42.912 0.084 42.936 ;
    END
  END b[46]
  PIN b[47]
    DIRECTION OUTPUT ;
    USE SIGNAL ;
    PORT
      LAYER M4 ;
        RECT  0 43.056 0.084 43.08 ;
    END
  END b[47]
  PIN b[48]
    DIRECTION OUTPUT ;
    USE SIGNAL ;
    PORT
      LAYER M4 ;
        RECT  0 43.2 0.084 43.224 ;
    END
  END b[48]
  PIN b[49]
    DIRECTION OUTPUT ;
    USE SIGNAL ;
    PORT
      LAYER M4 ;
        RECT  0 43.344 0.084 43.368 ;
    END
  END b[49]
  PIN b[4]
    DIRECTION OUTPUT ;
    USE SIGNAL ;
    PORT
      LAYER M4 ;
        RECT  0 32.256 0.084 32.28 ;
    END
  END b[4]
  PIN b[50]
    DIRECTION OUTPUT ;
    USE SIGNAL ;
    PORT
      LAYER M4 ;
        RECT  0 43.488 0.084 43.512 ;
    END
  END b[50]
  PIN b[51]
    DIRECTION OUTPUT ;
    USE SIGNAL ;
    PORT
      LAYER M4 ;
        RECT  0 43.632 0.084 43.656 ;
    END
  END b[51]
  PIN b[52]
    DIRECTION OUTPUT ;
    USE SIGNAL ;
    PORT
      LAYER M4 ;
        RECT  0 43.776 0.084 43.8 ;
    END
  END b[52]
  PIN b[53]
    DIRECTION OUTPUT ;
    USE SIGNAL ;
    PORT
      LAYER M4 ;
        RECT  0 43.92 0.084 43.944 ;
    END
  END b[53]
  PIN b[54]
    DIRECTION OUTPUT ;
    USE SIGNAL ;
    PORT
      LAYER M4 ;
        RECT  0 44.064 0.084 44.088 ;
    END
  END b[54]
  PIN b[55]
    DIRECTION OUTPUT ;
    USE SIGNAL ;
    PORT
      LAYER M4 ;
        RECT  0 44.208 0.084 44.232 ;
    END
  END b[55]
  PIN b[56]
    DIRECTION OUTPUT ;
    USE SIGNAL ;
    PORT
      LAYER M4 ;
        RECT  0 44.352 0.084 44.376 ;
    END
  END b[56]
  PIN b[57]
    DIRECTION OUTPUT ;
    USE SIGNAL ;
    PORT
      LAYER M4 ;
        RECT  0 44.496 0.084 44.52 ;
    END
  END b[57]
  PIN b[58]
    DIRECTION OUTPUT ;
    USE SIGNAL ;
    PORT
      LAYER M4 ;
        RECT  0 44.64 0.084 44.664 ;
    END
  END b[58]
  PIN b[59]
    DIRECTION OUTPUT ;
    USE SIGNAL ;
    PORT
      LAYER M4 ;
        RECT  0 44.784 0.084 44.808 ;
    END
  END b[59]
  PIN b[5]
    DIRECTION OUTPUT ;
    USE SIGNAL ;
    PORT
      LAYER M4 ;
        RECT  0 32.4 0.084 32.424 ;
    END
  END b[5]
  PIN b[60]
    DIRECTION OUTPUT ;
    USE SIGNAL ;
    PORT
      LAYER M4 ;
        RECT  0 44.928 0.084 44.952 ;
    END
  END b[60]
  PIN b[61]
    DIRECTION OUTPUT ;
    USE SIGNAL ;
    PORT
      LAYER M4 ;
        RECT  0 45.072 0.084 45.096 ;
    END
  END b[61]
  PIN b[62]
    DIRECTION OUTPUT ;
    USE SIGNAL ;
    PORT
      LAYER M4 ;
        RECT  0 45.216 0.084 45.24 ;
    END
  END b[62]
  PIN b[63]
    DIRECTION OUTPUT ;
    USE SIGNAL ;
    PORT
      LAYER M4 ;
        RECT  0 45.36 0.084 45.384 ;
    END
  END b[63]
  PIN b[64]
    DIRECTION OUTPUT ;
    USE SIGNAL ;
    PORT
      LAYER M4 ;
        RECT  0 78.912 0.084 78.936 ;
    END
  END b[64]
  PIN b[65]
    DIRECTION OUTPUT ;
    USE SIGNAL ;
    PORT
      LAYER M4 ;
        RECT  0 79.056 0.084 79.08 ;
    END
  END b[65]
  PIN b[66]
    DIRECTION OUTPUT ;
    USE SIGNAL ;
    PORT
      LAYER M4 ;
        RECT  0 79.2 0.084 79.224 ;
    END
  END b[66]
  PIN b[67]
    DIRECTION OUTPUT ;
    USE SIGNAL ;
    PORT
      LAYER M4 ;
        RECT  0 79.344 0.084 79.368 ;
    END
  END b[67]
  PIN b[68]
    DIRECTION OUTPUT ;
    USE SIGNAL ;
    PORT
      LAYER M4 ;
        RECT  0 79.488 0.084 79.512 ;
    END
  END b[68]
  PIN b[69]
    DIRECTION OUTPUT ;
    USE SIGNAL ;
    PORT
      LAYER M4 ;
        RECT  0 79.632 0.084 79.656 ;
    END
  END b[69]
  PIN b[6]
    DIRECTION OUTPUT ;
    USE SIGNAL ;
    PORT
      LAYER M4 ;
        RECT  0 32.544 0.084 32.568 ;
    END
  END b[6]
  PIN b[70]
    DIRECTION OUTPUT ;
    USE SIGNAL ;
    PORT
      LAYER M4 ;
        RECT  0 79.776 0.084 79.8 ;
    END
  END b[70]
  PIN b[71]
    DIRECTION OUTPUT ;
    USE SIGNAL ;
    PORT
      LAYER M4 ;
        RECT  0 79.92 0.084 79.944 ;
    END
  END b[71]
  PIN b[72]
    DIRECTION OUTPUT ;
    USE SIGNAL ;
    PORT
      LAYER M4 ;
        RECT  0 80.064 0.084 80.088 ;
    END
  END b[72]
  PIN b[73]
    DIRECTION OUTPUT ;
    USE SIGNAL ;
    PORT
      LAYER M4 ;
        RECT  0 80.208 0.084 80.232 ;
    END
  END b[73]
  PIN b[74]
    DIRECTION OUTPUT ;
    USE SIGNAL ;
    PORT
      LAYER M4 ;
        RECT  0 80.352 0.084 80.376 ;
    END
  END b[74]
  PIN b[75]
    DIRECTION OUTPUT ;
    USE SIGNAL ;
    PORT
      LAYER M4 ;
        RECT  0 80.496 0.084 80.52 ;
    END
  END b[75]
  PIN b[76]
    DIRECTION OUTPUT ;
    USE SIGNAL ;
    PORT
      LAYER M4 ;
        RECT  0 80.64 0.084 80.664 ;
    END
  END b[76]
  PIN b[77]
    DIRECTION OUTPUT ;
    USE SIGNAL ;
    PORT
      LAYER M4 ;
        RECT  0 80.784 0.084 80.808 ;
    END
  END b[77]
  PIN b[78]
    DIRECTION OUTPUT ;
    USE SIGNAL ;
    PORT
      LAYER M4 ;
        RECT  0 80.928 0.084 80.952 ;
    END
  END b[78]
  PIN b[79]
    DIRECTION OUTPUT ;
    USE SIGNAL ;
    PORT
      LAYER M4 ;
        RECT  0 81.072 0.084 81.096 ;
    END
  END b[79]
  PIN b[7]
    DIRECTION OUTPUT ;
    USE SIGNAL ;
    PORT
      LAYER M4 ;
        RECT  0 32.688 0.084 32.712 ;
    END
  END b[7]
  PIN b[80]
    DIRECTION OUTPUT ;
    USE SIGNAL ;
    PORT
      LAYER M4 ;
        RECT  0 81.216 0.084 81.24 ;
    END
  END b[80]
  PIN b[81]
    DIRECTION OUTPUT ;
    USE SIGNAL ;
    PORT
      LAYER M4 ;
        RECT  0 81.36 0.084 81.384 ;
    END
  END b[81]
  PIN b[82]
    DIRECTION OUTPUT ;
    USE SIGNAL ;
    PORT
      LAYER M4 ;
        RECT  0 81.504 0.084 81.528 ;
    END
  END b[82]
  PIN b[83]
    DIRECTION OUTPUT ;
    USE SIGNAL ;
    PORT
      LAYER M4 ;
        RECT  0 81.648 0.084 81.672 ;
    END
  END b[83]
  PIN b[84]
    DIRECTION OUTPUT ;
    USE SIGNAL ;
    PORT
      LAYER M4 ;
        RECT  0 81.792 0.084 81.816 ;
    END
  END b[84]
  PIN b[85]
    DIRECTION OUTPUT ;
    USE SIGNAL ;
    PORT
      LAYER M4 ;
        RECT  0 81.936 0.084 81.96 ;
    END
  END b[85]
  PIN b[86]
    DIRECTION OUTPUT ;
    USE SIGNAL ;
    PORT
      LAYER M4 ;
        RECT  0 82.08 0.084 82.104 ;
    END
  END b[86]
  PIN b[87]
    DIRECTION OUTPUT ;
    USE SIGNAL ;
    PORT
      LAYER M4 ;
        RECT  0 82.224 0.084 82.248 ;
    END
  END b[87]
  PIN b[88]
    DIRECTION OUTPUT ;
    USE SIGNAL ;
    PORT
      LAYER M4 ;
        RECT  0 82.368 0.084 82.392 ;
    END
  END b[88]
  PIN b[89]
    DIRECTION OUTPUT ;
    USE SIGNAL ;
    PORT
      LAYER M4 ;
        RECT  0 82.512 0.084 82.536 ;
    END
  END b[89]
  PIN b[8]
    DIRECTION OUTPUT ;
    USE SIGNAL ;
    PORT
      LAYER M4 ;
        RECT  0 32.832 0.084 32.856 ;
    END
  END b[8]
  PIN b[90]
    DIRECTION OUTPUT ;
    USE SIGNAL ;
    PORT
      LAYER M4 ;
        RECT  0 82.656 0.084 82.68 ;
    END
  END b[90]
  PIN b[91]
    DIRECTION OUTPUT ;
    USE SIGNAL ;
    PORT
      LAYER M4 ;
        RECT  0 82.8 0.084 82.824 ;
    END
  END b[91]
  PIN b[92]
    DIRECTION OUTPUT ;
    USE SIGNAL ;
    PORT
      LAYER M4 ;
        RECT  0 82.944 0.084 82.968 ;
    END
  END b[92]
  PIN b[93]
    DIRECTION OUTPUT ;
    USE SIGNAL ;
    PORT
      LAYER M4 ;
        RECT  0 83.088 0.084 83.112 ;
    END
  END b[93]
  PIN b[94]
    DIRECTION OUTPUT ;
    USE SIGNAL ;
    PORT
      LAYER M4 ;
        RECT  0 83.232 0.084 83.256 ;
    END
  END b[94]
  PIN b[95]
    DIRECTION OUTPUT ;
    USE SIGNAL ;
    PORT
      LAYER M4 ;
        RECT  0 83.376 0.084 83.4 ;
    END
  END b[95]
  PIN b[96]
    DIRECTION OUTPUT ;
    USE SIGNAL ;
    PORT
      LAYER M4 ;
        RECT  0 84.672 0.084 84.696 ;
    END
  END b[96]
  PIN b[97]
    DIRECTION OUTPUT ;
    USE SIGNAL ;
    PORT
      LAYER M4 ;
        RECT  0 84.816 0.084 84.84 ;
    END
  END b[97]
  PIN b[98]
    DIRECTION OUTPUT ;
    USE SIGNAL ;
    PORT
      LAYER M4 ;
        RECT  0 84.96 0.084 84.984 ;
    END
  END b[98]
  PIN b[99]
    DIRECTION OUTPUT ;
    USE SIGNAL ;
    PORT
      LAYER M4 ;
        RECT  0 85.104 0.084 85.128 ;
    END
  END b[99]
  PIN b[9]
    DIRECTION OUTPUT ;
    USE SIGNAL ;
    PORT
      LAYER M4 ;
        RECT  0 32.976 0.084 33 ;
    END
  END b[9]
  PIN ck
    DIRECTION INPUT ;
    USE SIGNAL ;
    PORT
      LAYER M3 ;
        RECT  37.908 170.603 37.926 170.64 ;
    END
  END ck
  PIN ck_s
    DIRECTION INPUT ;
    USE SIGNAL ;
    PORT
      LAYER M3 ;
        RECT  38.016 170.603 38.034 170.64 ;
    END
  END ck_s
  PIN en
    DIRECTION INPUT ;
    USE SIGNAL ;
    PORT
      LAYER M3 ;
        RECT  38.124 170.603 38.142 170.64 ;
    END
  END en
  PIN fault
    DIRECTION OUTPUT ;
    USE SIGNAL ;
    PORT
      LAYER M3 ;
        RECT  38.232 170.603 38.25 170.64 ;
    END
  END fault
  PIN k0
    DIRECTION INPUT ;
    USE SIGNAL ;
    PORT
      LAYER M3 ;
        RECT  38.34 170.603 38.358 170.64 ;
    END
  END k0
  PIN k1
    DIRECTION INPUT ;
    USE SIGNAL ;
    PORT
      LAYER M3 ;
        RECT  38.448 170.603 38.466 170.64 ;
    END
  END k1
  PIN k2
    DIRECTION INPUT ;
    USE SIGNAL ;
    PORT
      LAYER M3 ;
        RECT  38.556 170.603 38.574 170.64 ;
    END
  END k2
  PIN k3
    DIRECTION INPUT ;
    USE SIGNAL ;
    PORT
      LAYER M3 ;
        RECT  38.664 170.603 38.682 170.64 ;
    END
  END k3
  PIN rs
    DIRECTION INPUT ;
    USE SIGNAL ;
    PORT
      LAYER M3 ;
        RECT  38.772 170.603 38.79 170.64 ;
    END
  END rs
  PIN tie_hi
    DIRECTION OUTPUT ;
    USE SIGNAL ;
    PORT
      LAYER M3 ;
        RECT  38.88 170.603 38.898 170.64 ;
    END
  END tie_hi
  PIN tie_lo
    DIRECTION OUTPUT ;
    USE SIGNAL ;
    PORT
      LAYER M3 ;
        RECT  38.988 170.603 39.006 170.64 ;
    END
  END tie_lo
  PIN VDD
    DIRECTION INOUT ;
    USE POWER ;
    PORT
      LAYER M5 ;
        RECT  94.392 2.151 94.512 168.489 ;
        RECT  91.692 2.151 91.812 168.489 ;
        RECT  88.992 2.151 89.112 168.489 ;
        RECT  86.292 2.151 86.412 168.489 ;
        RECT  83.592 2.151 83.712 168.489 ;
        RECT  80.892 2.151 81.012 168.489 ;
        RECT  78.192 2.151 78.312 168.489 ;
        RECT  75.492 2.151 75.612 168.489 ;
        RECT  72.792 2.151 72.912 168.489 ;
        RECT  70.092 2.151 70.212 168.489 ;
        RECT  67.392 2.151 67.512 168.489 ;
        RECT  64.692 2.151 64.812 168.489 ;
        RECT  61.992 2.151 62.112 168.489 ;
        RECT  59.292 2.151 59.412 168.489 ;
        RECT  56.592 2.151 56.712 168.489 ;
        RECT  53.892 2.151 54.012 168.489 ;
        RECT  51.192 2.151 51.312 168.489 ;
        RECT  48.492 2.151 48.612 168.489 ;
        RECT  45.792 2.151 45.912 168.489 ;
        RECT  43.092 2.151 43.212 168.489 ;
        RECT  40.392 2.151 40.512 168.489 ;
        RECT  37.692 2.151 37.812 168.489 ;
        RECT  34.992 2.151 35.112 168.489 ;
        RECT  32.292 2.151 32.412 168.489 ;
        RECT  29.592 2.151 29.712 168.489 ;
        RECT  26.892 2.151 27.012 168.489 ;
        RECT  24.192 2.151 24.312 168.489 ;
        RECT  21.492 2.151 21.612 168.489 ;
        RECT  18.792 2.151 18.912 168.489 ;
        RECT  16.092 2.151 16.212 168.489 ;
        RECT  13.392 2.151 13.512 168.489 ;
        RECT  10.692 2.151 10.812 168.489 ;
        RECT  7.992 2.151 8.112 168.489 ;
        RECT  5.292 2.151 5.412 168.489 ;
        RECT  2.592 2.151 2.712 168.489 ;
    END
  END VDD
  PIN VSS
    DIRECTION INOUT ;
    USE GROUND ;
    PORT
      LAYER M5 ;
        RECT  94.2 2.137 94.32 168.503 ;
        RECT  91.5 2.137 91.62 168.503 ;
        RECT  88.8 2.137 88.92 168.503 ;
        RECT  86.1 2.137 86.22 168.503 ;
        RECT  83.4 2.137 83.52 168.503 ;
        RECT  80.7 2.137 80.82 168.503 ;
        RECT  78 2.137 78.12 168.503 ;
        RECT  75.3 2.137 75.42 168.503 ;
        RECT  72.6 2.137 72.72 168.503 ;
        RECT  69.9 2.137 70.02 168.503 ;
        RECT  67.2 2.137 67.32 168.503 ;
        RECT  64.5 2.137 64.62 168.503 ;
        RECT  61.8 2.137 61.92 168.503 ;
        RECT  59.1 2.137 59.22 168.503 ;
        RECT  56.4 2.137 56.52 168.503 ;
        RECT  53.7 2.137 53.82 168.503 ;
        RECT  51 2.137 51.12 168.503 ;
        RECT  48.3 2.137 48.42 168.503 ;
        RECT  45.6 2.137 45.72 168.503 ;
        RECT  42.9 2.137 43.02 168.503 ;
        RECT  40.2 2.137 40.32 168.503 ;
        RECT  37.5 2.137 37.62 168.503 ;
        RECT  34.8 2.137 34.92 168.503 ;
        RECT  32.1 2.137 32.22 168.503 ;
        RECT  29.4 2.137 29.52 168.503 ;
        RECT  26.7 2.137 26.82 168.503 ;
        RECT  24 2.137 24.12 168.503 ;
        RECT  21.3 2.137 21.42 168.503 ;
        RECT  18.6 2.137 18.72 168.503 ;
        RECT  15.9 2.137 16.02 168.503 ;
        RECT  13.2 2.137 13.32 168.503 ;
        RECT  10.5 2.137 10.62 168.503 ;
        RECT  7.8 2.137 7.92 168.503 ;
        RECT  5.1 2.137 5.22 168.503 ;
        RECT  2.4 2.137 2.52 168.503 ;
    END
  END VSS
  OBS
    LAYER RVTN ;
     RECT  2.16 2.16 96.12 2.295 ;
     RECT  2.16 2.565 96.12 2.835 ;
     RECT  2.16 3.105 96.12 3.375 ;
     RECT  2.16 3.645 96.12 3.915 ;
     RECT  2.16 4.185 96.12 4.455 ;
     RECT  2.16 4.725 96.12 4.995 ;
     RECT  2.16 5.265 96.12 5.535 ;
     RECT  2.16 5.805 96.12 6.075 ;
     RECT  2.16 6.345 96.12 6.615 ;
     RECT  2.16 6.885 96.12 7.155 ;
     RECT  2.16 7.425 96.12 7.695 ;
     RECT  2.16 7.965 96.12 8.235 ;
     RECT  2.16 8.505 96.12 8.775 ;
     RECT  2.16 9.045 96.12 9.315 ;
     RECT  2.16 9.585 96.12 9.855 ;
     RECT  2.16 10.125 96.12 10.395 ;
     RECT  2.16 10.665 96.12 10.935 ;
     RECT  2.16 11.205 96.12 11.475 ;
     RECT  2.16 11.745 96.12 12.015 ;
     RECT  2.16 12.285 96.12 12.555 ;
     RECT  2.16 12.825 96.12 13.095 ;
     RECT  2.16 13.365 96.12 13.635 ;
     RECT  2.16 13.905 96.12 14.175 ;
     RECT  2.16 14.445 96.12 14.715 ;
     RECT  2.16 14.985 96.12 15.255 ;
     RECT  2.16 15.525 96.12 15.795 ;
     RECT  2.16 16.065 96.12 16.335 ;
     RECT  2.16 16.605 96.12 16.875 ;
     RECT  2.16 17.145 96.12 17.415 ;
     RECT  2.16 17.685 96.12 17.955 ;
     RECT  2.16 18.225 96.12 18.495 ;
     RECT  2.16 18.765 96.12 19.035 ;
     RECT  2.16 19.305 96.12 19.575 ;
     RECT  2.16 19.845 96.12 20.115 ;
     RECT  2.16 20.385 96.12 20.655 ;
     RECT  2.16 20.925 96.12 21.195 ;
     RECT  2.16 21.465 96.12 21.735 ;
     RECT  2.16 22.005 96.12 22.275 ;
     RECT  2.16 22.545 96.12 22.815 ;
     RECT  2.16 23.085 96.12 23.355 ;
     RECT  2.16 23.625 96.12 23.895 ;
     RECT  2.16 24.165 96.12 24.435 ;
     RECT  2.16 24.705 96.12 24.975 ;
     RECT  2.16 25.245 96.12 25.515 ;
     RECT  2.16 25.785 96.12 26.055 ;
     RECT  2.16 26.325 96.12 26.595 ;
     RECT  2.16 26.865 96.12 27.135 ;
     RECT  2.16 27.405 96.12 27.675 ;
     RECT  2.16 27.945 96.12 28.215 ;
     RECT  2.16 28.485 96.12 28.755 ;
     RECT  2.16 29.025 96.12 29.295 ;
     RECT  2.16 29.565 96.12 29.835 ;
     RECT  2.16 30.105 96.12 30.375 ;
     RECT  2.16 30.645 96.12 30.915 ;
     RECT  2.16 31.185 96.12 31.455 ;
     RECT  2.16 31.725 96.12 31.995 ;
     RECT  2.16 32.265 96.12 32.535 ;
     RECT  2.16 32.805 96.12 33.075 ;
     RECT  2.16 33.345 96.12 33.615 ;
     RECT  2.16 33.885 96.12 34.155 ;
     RECT  2.16 34.425 96.12 34.695 ;
     RECT  2.16 34.965 96.12 35.235 ;
     RECT  2.16 35.505 96.12 35.775 ;
     RECT  2.16 36.045 96.12 36.315 ;
     RECT  2.16 36.585 96.12 36.855 ;
     RECT  2.16 37.125 96.12 37.395 ;
     RECT  2.16 37.665 96.12 37.935 ;
     RECT  2.16 38.205 96.12 38.475 ;
     RECT  2.16 38.745 96.12 39.015 ;
     RECT  2.16 39.285 96.12 39.555 ;
     RECT  2.16 39.825 96.12 40.095 ;
     RECT  2.16 40.365 96.12 40.635 ;
     RECT  2.16 40.905 96.12 41.04 ;
     RECT  2.16 41.04 41.148 41.175 ;
     RECT  77.22 41.04 96.12 41.175 ;
     RECT  2.16 41.445 41.148 41.715 ;
     RECT  77.22 41.445 96.12 41.715 ;
     RECT  2.16 41.985 41.148 42.255 ;
     RECT  77.22 41.985 96.12 42.255 ;
     RECT  2.16 42.525 41.148 42.795 ;
     RECT  77.22 42.525 96.12 42.795 ;
     RECT  2.16 43.065 41.148 43.335 ;
     RECT  77.22 43.065 96.12 43.335 ;
     RECT  2.16 43.605 41.148 43.875 ;
     RECT  77.22 43.605 96.12 43.875 ;
     RECT  2.16 44.145 41.148 44.415 ;
     RECT  77.22 44.145 96.12 44.415 ;
     RECT  2.16 44.685 41.148 44.955 ;
     RECT  77.22 44.685 96.12 44.955 ;
     RECT  2.16 45.225 41.148 45.495 ;
     RECT  77.22 45.225 96.12 45.495 ;
     RECT  2.16 45.765 41.148 46.035 ;
     RECT  77.22 45.765 96.12 46.035 ;
     RECT  2.16 46.305 41.148 46.575 ;
     RECT  77.22 46.305 96.12 46.575 ;
     RECT  2.16 46.845 41.148 47.115 ;
     RECT  77.22 46.845 96.12 47.115 ;
     RECT  2.16 47.385 41.148 47.655 ;
     RECT  77.22 47.385 96.12 47.655 ;
     RECT  2.16 47.925 41.148 48.195 ;
     RECT  77.22 47.925 96.12 48.195 ;
     RECT  2.16 48.465 41.148 48.735 ;
     RECT  77.22 48.465 96.12 48.735 ;
     RECT  2.16 49.005 41.148 49.275 ;
     RECT  77.22 49.005 96.12 49.275 ;
     RECT  2.16 49.545 41.148 49.815 ;
     RECT  77.22 49.545 96.12 49.815 ;
     RECT  2.16 50.085 41.148 50.355 ;
     RECT  77.22 50.085 96.12 50.355 ;
     RECT  2.16 50.625 41.148 50.895 ;
     RECT  77.22 50.625 96.12 50.895 ;
     RECT  2.16 51.165 41.148 51.435 ;
     RECT  77.22 51.165 96.12 51.435 ;
     RECT  2.16 51.705 41.148 51.975 ;
     RECT  77.22 51.705 96.12 51.975 ;
     RECT  2.16 52.245 41.148 52.515 ;
     RECT  77.22 52.245 96.12 52.515 ;
     RECT  2.16 52.785 41.148 53.055 ;
     RECT  77.22 52.785 96.12 53.055 ;
     RECT  2.16 53.325 41.148 53.595 ;
     RECT  77.22 53.325 96.12 53.595 ;
     RECT  2.16 53.865 41.148 54.135 ;
     RECT  77.22 53.865 96.12 54.135 ;
     RECT  2.16 54.405 41.148 54.675 ;
     RECT  77.22 54.405 96.12 54.675 ;
     RECT  2.16 54.945 41.148 55.215 ;
     RECT  77.22 54.945 96.12 55.215 ;
     RECT  2.16 55.485 41.148 55.755 ;
     RECT  77.22 55.485 96.12 55.755 ;
     RECT  2.16 56.025 41.148 56.295 ;
     RECT  77.22 56.025 96.12 56.295 ;
     RECT  2.16 56.565 41.148 56.835 ;
     RECT  77.22 56.565 96.12 56.835 ;
     RECT  2.16 57.105 41.148 57.375 ;
     RECT  77.22 57.105 96.12 57.375 ;
     RECT  2.16 57.645 41.148 57.915 ;
     RECT  77.22 57.645 96.12 57.915 ;
     RECT  2.16 58.185 41.148 58.455 ;
     RECT  77.22 58.185 96.12 58.455 ;
     RECT  2.16 58.725 41.148 58.995 ;
     RECT  77.22 58.725 96.12 58.995 ;
     RECT  2.16 59.265 41.148 59.535 ;
     RECT  77.22 59.265 96.12 59.535 ;
     RECT  2.16 59.805 41.148 60.075 ;
     RECT  77.22 59.805 96.12 60.075 ;
     RECT  2.16 60.345 41.148 60.615 ;
     RECT  77.22 60.345 96.12 60.615 ;
     RECT  2.16 60.885 41.148 61.155 ;
     RECT  77.22 60.885 96.12 61.155 ;
     RECT  2.16 61.425 41.148 61.695 ;
     RECT  77.22 61.425 96.12 61.695 ;
     RECT  2.16 61.965 41.148 62.235 ;
     RECT  77.22 61.965 96.12 62.235 ;
     RECT  2.16 62.505 41.148 62.64 ;
     RECT  77.22 62.505 96.12 62.64 ;
     RECT  2.16 62.64 96.12 62.775 ;
     RECT  2.16 63.045 96.12 63.315 ;
     RECT  2.16 63.585 96.12 63.855 ;
     RECT  2.16 64.125 96.12 64.395 ;
     RECT  2.16 64.665 96.12 64.935 ;
     RECT  2.16 65.205 96.12 65.475 ;
     RECT  2.16 65.745 96.12 66.015 ;
     RECT  2.16 66.285 96.12 66.555 ;
     RECT  2.16 66.825 96.12 67.095 ;
     RECT  2.16 67.365 96.12 67.635 ;
     RECT  2.16 67.905 96.12 68.175 ;
     RECT  2.16 68.445 96.12 68.715 ;
     RECT  2.16 68.985 96.12 69.255 ;
     RECT  2.16 69.525 96.12 69.795 ;
     RECT  2.16 70.065 96.12 70.335 ;
     RECT  2.16 70.605 96.12 70.875 ;
     RECT  2.16 71.145 96.12 71.415 ;
     RECT  2.16 71.685 96.12 71.955 ;
     RECT  2.16 72.225 96.12 72.495 ;
     RECT  2.16 72.765 96.12 73.035 ;
     RECT  2.16 73.305 96.12 73.575 ;
     RECT  2.16 73.845 96.12 74.115 ;
     RECT  2.16 74.385 96.12 74.655 ;
     RECT  2.16 74.925 96.12 75.195 ;
     RECT  2.16 75.465 96.12 75.735 ;
     RECT  2.16 76.005 96.12 76.275 ;
     RECT  2.16 76.545 96.12 76.815 ;
     RECT  2.16 77.085 96.12 77.355 ;
     RECT  2.16 77.625 96.12 77.895 ;
     RECT  2.16 78.165 96.12 78.435 ;
     RECT  2.16 78.705 96.12 78.975 ;
     RECT  2.16 79.245 96.12 79.515 ;
     RECT  2.16 79.785 96.12 80.055 ;
     RECT  2.16 80.325 96.12 80.595 ;
     RECT  2.16 80.865 96.12 81.135 ;
     RECT  2.16 81.405 96.12 81.675 ;
     RECT  2.16 81.945 96.12 82.215 ;
     RECT  2.16 82.485 96.12 82.755 ;
     RECT  2.16 83.025 96.12 83.295 ;
     RECT  2.16 83.565 96.12 83.835 ;
     RECT  2.16 84.105 96.12 84.24 ;
     RECT  2.16 84.24 41.148 84.375 ;
     RECT  77.22 84.24 96.12 84.375 ;
     RECT  2.16 84.645 41.148 84.915 ;
     RECT  77.22 84.645 96.12 84.915 ;
     RECT  2.16 85.185 41.148 85.455 ;
     RECT  77.22 85.185 96.12 85.455 ;
     RECT  2.16 85.725 41.148 85.995 ;
     RECT  77.22 85.725 96.12 85.995 ;
     RECT  2.16 86.265 41.148 86.535 ;
     RECT  77.22 86.265 96.12 86.535 ;
     RECT  2.16 86.805 41.148 87.075 ;
     RECT  77.22 86.805 96.12 87.075 ;
     RECT  2.16 87.345 41.148 87.615 ;
     RECT  77.22 87.345 96.12 87.615 ;
     RECT  2.16 87.885 41.148 88.155 ;
     RECT  77.22 87.885 96.12 88.155 ;
     RECT  2.16 88.425 41.148 88.695 ;
     RECT  77.22 88.425 96.12 88.695 ;
     RECT  2.16 88.965 41.148 89.235 ;
     RECT  77.22 88.965 96.12 89.235 ;
     RECT  2.16 89.505 41.148 89.775 ;
     RECT  77.22 89.505 96.12 89.775 ;
     RECT  2.16 90.045 41.148 90.315 ;
     RECT  77.22 90.045 96.12 90.315 ;
     RECT  2.16 90.585 41.148 90.855 ;
     RECT  77.22 90.585 96.12 90.855 ;
     RECT  2.16 91.125 41.148 91.395 ;
     RECT  77.22 91.125 96.12 91.395 ;
     RECT  2.16 91.665 41.148 91.935 ;
     RECT  77.22 91.665 96.12 91.935 ;
     RECT  2.16 92.205 41.148 92.475 ;
     RECT  77.22 92.205 96.12 92.475 ;
     RECT  2.16 92.745 41.148 93.015 ;
     RECT  77.22 92.745 96.12 93.015 ;
     RECT  2.16 93.285 41.148 93.555 ;
     RECT  77.22 93.285 96.12 93.555 ;
     RECT  2.16 93.825 41.148 94.095 ;
     RECT  77.22 93.825 96.12 94.095 ;
     RECT  2.16 94.365 41.148 94.635 ;
     RECT  77.22 94.365 96.12 94.635 ;
     RECT  2.16 94.905 41.148 95.175 ;
     RECT  77.22 94.905 96.12 95.175 ;
     RECT  2.16 95.445 41.148 95.715 ;
     RECT  77.22 95.445 96.12 95.715 ;
     RECT  2.16 95.985 41.148 96.255 ;
     RECT  77.22 95.985 96.12 96.255 ;
     RECT  2.16 96.525 41.148 96.795 ;
     RECT  77.22 96.525 96.12 96.795 ;
     RECT  2.16 97.065 41.148 97.335 ;
     RECT  77.22 97.065 96.12 97.335 ;
     RECT  2.16 97.605 41.148 97.875 ;
     RECT  77.22 97.605 96.12 97.875 ;
     RECT  2.16 98.145 41.148 98.415 ;
     RECT  77.22 98.145 96.12 98.415 ;
     RECT  2.16 98.685 41.148 98.955 ;
     RECT  77.22 98.685 96.12 98.955 ;
     RECT  2.16 99.225 41.148 99.495 ;
     RECT  77.22 99.225 96.12 99.495 ;
     RECT  2.16 99.765 41.148 100.035 ;
     RECT  77.22 99.765 96.12 100.035 ;
     RECT  2.16 100.305 41.148 100.575 ;
     RECT  77.22 100.305 96.12 100.575 ;
     RECT  2.16 100.845 41.148 101.115 ;
     RECT  77.22 100.845 96.12 101.115 ;
     RECT  2.16 101.385 41.148 101.655 ;
     RECT  77.22 101.385 96.12 101.655 ;
     RECT  2.16 101.925 41.148 102.195 ;
     RECT  77.22 101.925 96.12 102.195 ;
     RECT  2.16 102.465 41.148 102.735 ;
     RECT  77.22 102.465 96.12 102.735 ;
     RECT  2.16 103.005 41.148 103.275 ;
     RECT  77.22 103.005 96.12 103.275 ;
     RECT  2.16 103.545 41.148 103.815 ;
     RECT  77.22 103.545 96.12 103.815 ;
     RECT  2.16 104.085 41.148 104.355 ;
     RECT  77.22 104.085 96.12 104.355 ;
     RECT  2.16 104.625 41.148 104.895 ;
     RECT  77.22 104.625 96.12 104.895 ;
     RECT  2.16 105.165 41.148 105.435 ;
     RECT  77.22 105.165 96.12 105.435 ;
     RECT  2.16 105.705 41.148 105.84 ;
     RECT  77.22 105.705 96.12 105.84 ;
     RECT  2.16 105.84 96.12 105.975 ;
     RECT  2.16 106.245 96.12 106.515 ;
     RECT  2.16 106.785 96.12 107.055 ;
     RECT  2.16 107.325 96.12 107.595 ;
     RECT  2.16 107.865 96.12 108.135 ;
     RECT  2.16 108.405 96.12 108.675 ;
     RECT  2.16 108.945 96.12 109.215 ;
     RECT  2.16 109.485 96.12 109.755 ;
     RECT  2.16 110.025 96.12 110.295 ;
     RECT  2.16 110.565 96.12 110.835 ;
     RECT  2.16 111.105 96.12 111.375 ;
     RECT  2.16 111.645 96.12 111.915 ;
     RECT  2.16 112.185 96.12 112.455 ;
     RECT  2.16 112.725 96.12 112.995 ;
     RECT  2.16 113.265 96.12 113.535 ;
     RECT  2.16 113.805 96.12 114.075 ;
     RECT  2.16 114.345 96.12 114.615 ;
     RECT  2.16 114.885 96.12 115.155 ;
     RECT  2.16 115.425 96.12 115.695 ;
     RECT  2.16 115.965 96.12 116.235 ;
     RECT  2.16 116.505 96.12 116.775 ;
     RECT  2.16 117.045 96.12 117.315 ;
     RECT  2.16 117.585 96.12 117.855 ;
     RECT  2.16 118.125 96.12 118.395 ;
     RECT  2.16 118.665 96.12 118.935 ;
     RECT  2.16 119.205 96.12 119.475 ;
     RECT  2.16 119.745 96.12 120.015 ;
     RECT  2.16 120.285 96.12 120.555 ;
     RECT  2.16 120.825 96.12 121.095 ;
     RECT  2.16 121.365 96.12 121.635 ;
     RECT  2.16 121.905 96.12 122.175 ;
     RECT  2.16 122.445 96.12 122.715 ;
     RECT  2.16 122.985 96.12 123.255 ;
     RECT  2.16 123.525 96.12 123.795 ;
     RECT  2.16 124.065 96.12 124.335 ;
     RECT  2.16 124.605 96.12 124.875 ;
     RECT  2.16 125.145 96.12 125.415 ;
     RECT  2.16 125.685 96.12 125.955 ;
     RECT  2.16 126.225 96.12 126.495 ;
     RECT  2.16 126.765 96.12 127.035 ;
     RECT  2.16 127.305 96.12 127.44 ;
     RECT  2.16 127.44 41.148 127.575 ;
     RECT  77.22 127.44 96.12 127.575 ;
     RECT  2.16 127.845 41.148 128.115 ;
     RECT  77.22 127.845 96.12 128.115 ;
     RECT  2.16 128.385 41.148 128.655 ;
     RECT  77.22 128.385 96.12 128.655 ;
     RECT  2.16 128.925 41.148 129.195 ;
     RECT  77.22 128.925 96.12 129.195 ;
     RECT  2.16 129.465 41.148 129.735 ;
     RECT  77.22 129.465 96.12 129.735 ;
     RECT  2.16 130.005 41.148 130.275 ;
     RECT  77.22 130.005 96.12 130.275 ;
     RECT  2.16 130.545 41.148 130.815 ;
     RECT  77.22 130.545 96.12 130.815 ;
     RECT  2.16 131.085 41.148 131.355 ;
     RECT  77.22 131.085 96.12 131.355 ;
     RECT  2.16 131.625 41.148 131.895 ;
     RECT  77.22 131.625 96.12 131.895 ;
     RECT  2.16 132.165 41.148 132.435 ;
     RECT  77.22 132.165 96.12 132.435 ;
     RECT  2.16 132.705 41.148 132.975 ;
     RECT  77.22 132.705 96.12 132.975 ;
     RECT  2.16 133.245 41.148 133.515 ;
     RECT  77.22 133.245 96.12 133.515 ;
     RECT  2.16 133.785 41.148 134.055 ;
     RECT  77.22 133.785 96.12 134.055 ;
     RECT  2.16 134.325 41.148 134.595 ;
     RECT  77.22 134.325 96.12 134.595 ;
     RECT  2.16 134.865 41.148 135.135 ;
     RECT  77.22 134.865 96.12 135.135 ;
     RECT  2.16 135.405 41.148 135.675 ;
     RECT  77.22 135.405 96.12 135.675 ;
     RECT  2.16 135.945 41.148 136.215 ;
     RECT  77.22 135.945 96.12 136.215 ;
     RECT  2.16 136.485 41.148 136.755 ;
     RECT  77.22 136.485 96.12 136.755 ;
     RECT  2.16 137.025 41.148 137.295 ;
     RECT  77.22 137.025 96.12 137.295 ;
     RECT  2.16 137.565 41.148 137.835 ;
     RECT  77.22 137.565 96.12 137.835 ;
     RECT  2.16 138.105 41.148 138.375 ;
     RECT  77.22 138.105 96.12 138.375 ;
     RECT  2.16 138.645 41.148 138.915 ;
     RECT  77.22 138.645 96.12 138.915 ;
     RECT  2.16 139.185 41.148 139.455 ;
     RECT  77.22 139.185 96.12 139.455 ;
     RECT  2.16 139.725 41.148 139.995 ;
     RECT  77.22 139.725 96.12 139.995 ;
     RECT  2.16 140.265 41.148 140.535 ;
     RECT  77.22 140.265 96.12 140.535 ;
     RECT  2.16 140.805 41.148 141.075 ;
     RECT  77.22 140.805 96.12 141.075 ;
     RECT  2.16 141.345 41.148 141.615 ;
     RECT  77.22 141.345 96.12 141.615 ;
     RECT  2.16 141.885 41.148 142.155 ;
     RECT  77.22 141.885 96.12 142.155 ;
     RECT  2.16 142.425 41.148 142.695 ;
     RECT  77.22 142.425 96.12 142.695 ;
     RECT  2.16 142.965 41.148 143.235 ;
     RECT  77.22 142.965 96.12 143.235 ;
     RECT  2.16 143.505 41.148 143.775 ;
     RECT  77.22 143.505 96.12 143.775 ;
     RECT  2.16 144.045 41.148 144.315 ;
     RECT  77.22 144.045 96.12 144.315 ;
     RECT  2.16 144.585 41.148 144.855 ;
     RECT  77.22 144.585 96.12 144.855 ;
     RECT  2.16 145.125 41.148 145.395 ;
     RECT  77.22 145.125 96.12 145.395 ;
     RECT  2.16 145.665 41.148 145.935 ;
     RECT  77.22 145.665 96.12 145.935 ;
     RECT  2.16 146.205 41.148 146.475 ;
     RECT  77.22 146.205 96.12 146.475 ;
     RECT  2.16 146.745 41.148 147.015 ;
     RECT  77.22 146.745 96.12 147.015 ;
     RECT  2.16 147.285 41.148 147.555 ;
     RECT  77.22 147.285 96.12 147.555 ;
     RECT  2.16 147.825 41.148 148.095 ;
     RECT  77.22 147.825 96.12 148.095 ;
     RECT  2.16 148.365 41.148 148.635 ;
     RECT  77.22 148.365 96.12 148.635 ;
     RECT  2.16 148.905 41.148 149.04 ;
     RECT  77.22 148.905 96.12 149.04 ;
     RECT  2.16 149.04 96.12 149.175 ;
     RECT  2.16 149.445 96.12 149.715 ;
     RECT  2.16 149.985 96.12 150.255 ;
     RECT  2.16 150.525 96.12 150.795 ;
     RECT  2.16 151.065 96.12 151.335 ;
     RECT  2.16 151.605 96.12 151.875 ;
     RECT  2.16 152.145 96.12 152.415 ;
     RECT  2.16 152.685 96.12 152.955 ;
     RECT  2.16 153.225 96.12 153.495 ;
     RECT  2.16 153.765 96.12 154.035 ;
     RECT  2.16 154.305 96.12 154.575 ;
     RECT  2.16 154.845 96.12 155.115 ;
     RECT  2.16 155.385 96.12 155.655 ;
     RECT  2.16 155.925 96.12 156.195 ;
     RECT  2.16 156.465 96.12 156.735 ;
     RECT  2.16 157.005 96.12 157.275 ;
     RECT  2.16 157.545 96.12 157.815 ;
     RECT  2.16 158.085 96.12 158.355 ;
     RECT  2.16 158.625 96.12 158.895 ;
     RECT  2.16 159.165 96.12 159.435 ;
     RECT  2.16 159.705 96.12 159.975 ;
     RECT  2.16 160.245 96.12 160.515 ;
     RECT  2.16 160.785 96.12 161.055 ;
     RECT  2.16 161.325 96.12 161.595 ;
     RECT  2.16 161.865 96.12 162.135 ;
     RECT  2.16 162.405 96.12 162.675 ;
     RECT  2.16 162.945 96.12 163.215 ;
     RECT  2.16 163.485 96.12 163.755 ;
     RECT  2.16 164.025 96.12 164.295 ;
     RECT  2.16 164.565 96.12 164.835 ;
     RECT  2.16 165.105 96.12 165.375 ;
     RECT  2.16 165.645 96.12 165.915 ;
     RECT  2.16 166.185 96.12 166.455 ;
     RECT  2.16 166.725 96.12 166.995 ;
     RECT  2.16 167.265 96.12 167.535 ;
     RECT  2.16 167.805 96.12 168.075 ;
     RECT  2.16 168.345 96.12 168.48 ;
    LAYER RVTP ;
     RECT  2.16 2.295 96.12 2.565 ;
     RECT  2.16 2.835 96.12 3.105 ;
     RECT  2.16 3.375 96.12 3.645 ;
     RECT  2.16 3.915 96.12 4.185 ;
     RECT  2.16 4.455 96.12 4.725 ;
     RECT  2.16 4.995 96.12 5.265 ;
     RECT  2.16 5.535 96.12 5.805 ;
     RECT  2.16 6.075 96.12 6.345 ;
     RECT  2.16 6.615 96.12 6.885 ;
     RECT  2.16 7.155 96.12 7.425 ;
     RECT  2.16 7.695 96.12 7.965 ;
     RECT  2.16 8.235 96.12 8.505 ;
     RECT  2.16 8.775 96.12 9.045 ;
     RECT  2.16 9.315 96.12 9.585 ;
     RECT  2.16 9.855 96.12 10.125 ;
     RECT  2.16 10.395 96.12 10.665 ;
     RECT  2.16 10.935 96.12 11.205 ;
     RECT  2.16 11.475 96.12 11.745 ;
     RECT  2.16 12.015 96.12 12.285 ;
     RECT  2.16 12.555 96.12 12.825 ;
     RECT  2.16 13.095 96.12 13.365 ;
     RECT  2.16 13.635 96.12 13.905 ;
     RECT  2.16 14.175 96.12 14.445 ;
     RECT  2.16 14.715 96.12 14.985 ;
     RECT  2.16 15.255 96.12 15.525 ;
     RECT  2.16 15.795 96.12 16.065 ;
     RECT  2.16 16.335 96.12 16.605 ;
     RECT  2.16 16.875 96.12 17.145 ;
     RECT  2.16 17.415 96.12 17.685 ;
     RECT  2.16 17.955 96.12 18.225 ;
     RECT  2.16 18.495 96.12 18.765 ;
     RECT  2.16 19.035 96.12 19.305 ;
     RECT  2.16 19.575 96.12 19.845 ;
     RECT  2.16 20.115 96.12 20.385 ;
     RECT  2.16 20.655 96.12 20.925 ;
     RECT  2.16 21.195 96.12 21.465 ;
     RECT  2.16 21.735 96.12 22.005 ;
     RECT  2.16 22.275 96.12 22.545 ;
     RECT  2.16 22.815 96.12 23.085 ;
     RECT  2.16 23.355 96.12 23.625 ;
     RECT  2.16 23.895 96.12 24.165 ;
     RECT  2.16 24.435 96.12 24.705 ;
     RECT  2.16 24.975 96.12 25.245 ;
     RECT  2.16 25.515 96.12 25.785 ;
     RECT  2.16 26.055 96.12 26.325 ;
     RECT  2.16 26.595 96.12 26.865 ;
     RECT  2.16 27.135 96.12 27.405 ;
     RECT  2.16 27.675 96.12 27.945 ;
     RECT  2.16 28.215 96.12 28.485 ;
     RECT  2.16 28.755 96.12 29.025 ;
     RECT  2.16 29.295 96.12 29.565 ;
     RECT  2.16 29.835 96.12 30.105 ;
     RECT  2.16 30.375 96.12 30.645 ;
     RECT  2.16 30.915 96.12 31.185 ;
     RECT  2.16 31.455 96.12 31.725 ;
     RECT  2.16 31.995 96.12 32.265 ;
     RECT  2.16 32.535 96.12 32.805 ;
     RECT  2.16 33.075 96.12 33.345 ;
     RECT  2.16 33.615 96.12 33.885 ;
     RECT  2.16 34.155 96.12 34.425 ;
     RECT  2.16 34.695 96.12 34.965 ;
     RECT  2.16 35.235 96.12 35.505 ;
     RECT  2.16 35.775 96.12 36.045 ;
     RECT  2.16 36.315 96.12 36.585 ;
     RECT  2.16 36.855 96.12 37.125 ;
     RECT  2.16 37.395 96.12 37.665 ;
     RECT  2.16 37.935 96.12 38.205 ;
     RECT  2.16 38.475 96.12 38.745 ;
     RECT  2.16 39.015 96.12 39.285 ;
     RECT  2.16 39.555 96.12 39.825 ;
     RECT  2.16 40.095 96.12 40.365 ;
     RECT  2.16 40.635 96.12 40.905 ;
     RECT  2.16 41.175 41.148 41.445 ;
     RECT  77.22 41.175 96.12 41.445 ;
     RECT  2.16 41.715 41.148 41.985 ;
     RECT  77.22 41.715 96.12 41.985 ;
     RECT  2.16 42.255 41.148 42.525 ;
     RECT  77.22 42.255 96.12 42.525 ;
     RECT  2.16 42.795 41.148 43.065 ;
     RECT  77.22 42.795 96.12 43.065 ;
     RECT  2.16 43.335 41.148 43.605 ;
     RECT  77.22 43.335 96.12 43.605 ;
     RECT  2.16 43.875 41.148 44.145 ;
     RECT  77.22 43.875 96.12 44.145 ;
     RECT  2.16 44.415 41.148 44.685 ;
     RECT  77.22 44.415 96.12 44.685 ;
     RECT  2.16 44.955 41.148 45.225 ;
     RECT  77.22 44.955 96.12 45.225 ;
     RECT  2.16 45.495 41.148 45.765 ;
     RECT  77.22 45.495 96.12 45.765 ;
     RECT  2.16 46.035 41.148 46.305 ;
     RECT  77.22 46.035 96.12 46.305 ;
     RECT  2.16 46.575 41.148 46.845 ;
     RECT  77.22 46.575 96.12 46.845 ;
     RECT  2.16 47.115 41.148 47.385 ;
     RECT  77.22 47.115 96.12 47.385 ;
     RECT  2.16 47.655 41.148 47.925 ;
     RECT  77.22 47.655 96.12 47.925 ;
     RECT  2.16 48.195 41.148 48.465 ;
     RECT  77.22 48.195 96.12 48.465 ;
     RECT  2.16 48.735 41.148 49.005 ;
     RECT  77.22 48.735 96.12 49.005 ;
     RECT  2.16 49.275 41.148 49.545 ;
     RECT  77.22 49.275 96.12 49.545 ;
     RECT  2.16 49.815 41.148 50.085 ;
     RECT  77.22 49.815 96.12 50.085 ;
     RECT  2.16 50.355 41.148 50.625 ;
     RECT  77.22 50.355 96.12 50.625 ;
     RECT  2.16 50.895 41.148 51.165 ;
     RECT  77.22 50.895 96.12 51.165 ;
     RECT  2.16 51.435 41.148 51.705 ;
     RECT  77.22 51.435 96.12 51.705 ;
     RECT  2.16 51.975 41.148 52.245 ;
     RECT  77.22 51.975 96.12 52.245 ;
     RECT  2.16 52.515 41.148 52.785 ;
     RECT  77.22 52.515 96.12 52.785 ;
     RECT  2.16 53.055 41.148 53.325 ;
     RECT  77.22 53.055 96.12 53.325 ;
     RECT  2.16 53.595 41.148 53.865 ;
     RECT  77.22 53.595 96.12 53.865 ;
     RECT  2.16 54.135 41.148 54.405 ;
     RECT  77.22 54.135 96.12 54.405 ;
     RECT  2.16 54.675 41.148 54.945 ;
     RECT  77.22 54.675 96.12 54.945 ;
     RECT  2.16 55.215 41.148 55.485 ;
     RECT  77.22 55.215 96.12 55.485 ;
     RECT  2.16 55.755 41.148 56.025 ;
     RECT  77.22 55.755 96.12 56.025 ;
     RECT  2.16 56.295 41.148 56.565 ;
     RECT  77.22 56.295 96.12 56.565 ;
     RECT  2.16 56.835 41.148 57.105 ;
     RECT  77.22 56.835 96.12 57.105 ;
     RECT  2.16 57.375 41.148 57.645 ;
     RECT  77.22 57.375 96.12 57.645 ;
     RECT  2.16 57.915 41.148 58.185 ;
     RECT  77.22 57.915 96.12 58.185 ;
     RECT  2.16 58.455 41.148 58.725 ;
     RECT  77.22 58.455 96.12 58.725 ;
     RECT  2.16 58.995 41.148 59.265 ;
     RECT  77.22 58.995 96.12 59.265 ;
     RECT  2.16 59.535 41.148 59.805 ;
     RECT  77.22 59.535 96.12 59.805 ;
     RECT  2.16 60.075 41.148 60.345 ;
     RECT  77.22 60.075 96.12 60.345 ;
     RECT  2.16 60.615 41.148 60.885 ;
     RECT  77.22 60.615 96.12 60.885 ;
     RECT  2.16 61.155 41.148 61.425 ;
     RECT  77.22 61.155 96.12 61.425 ;
     RECT  2.16 61.695 41.148 61.965 ;
     RECT  77.22 61.695 96.12 61.965 ;
     RECT  2.16 62.235 41.148 62.505 ;
     RECT  77.22 62.235 96.12 62.505 ;
     RECT  2.16 62.775 96.12 63.045 ;
     RECT  2.16 63.315 96.12 63.585 ;
     RECT  2.16 63.855 96.12 64.125 ;
     RECT  2.16 64.395 96.12 64.665 ;
     RECT  2.16 64.935 96.12 65.205 ;
     RECT  2.16 65.475 96.12 65.745 ;
     RECT  2.16 66.015 96.12 66.285 ;
     RECT  2.16 66.555 96.12 66.825 ;
     RECT  2.16 67.095 96.12 67.365 ;
     RECT  2.16 67.635 96.12 67.905 ;
     RECT  2.16 68.175 96.12 68.445 ;
     RECT  2.16 68.715 96.12 68.985 ;
     RECT  2.16 69.255 96.12 69.525 ;
     RECT  2.16 69.795 96.12 70.065 ;
     RECT  2.16 70.335 96.12 70.605 ;
     RECT  2.16 70.875 96.12 71.145 ;
     RECT  2.16 71.415 96.12 71.685 ;
     RECT  2.16 71.955 96.12 72.225 ;
     RECT  2.16 72.495 96.12 72.765 ;
     RECT  2.16 73.035 96.12 73.305 ;
     RECT  2.16 73.575 96.12 73.845 ;
     RECT  2.16 74.115 96.12 74.385 ;
     RECT  2.16 74.655 96.12 74.925 ;
     RECT  2.16 75.195 96.12 75.465 ;
     RECT  2.16 75.735 96.12 76.005 ;
     RECT  2.16 76.275 96.12 76.545 ;
     RECT  2.16 76.815 96.12 77.085 ;
     RECT  2.16 77.355 96.12 77.625 ;
     RECT  2.16 77.895 96.12 78.165 ;
     RECT  2.16 78.435 96.12 78.705 ;
     RECT  2.16 78.975 96.12 79.245 ;
     RECT  2.16 79.515 96.12 79.785 ;
     RECT  2.16 80.055 96.12 80.325 ;
     RECT  2.16 80.595 96.12 80.865 ;
     RECT  2.16 81.135 96.12 81.405 ;
     RECT  2.16 81.675 96.12 81.945 ;
     RECT  2.16 82.215 96.12 82.485 ;
     RECT  2.16 82.755 96.12 83.025 ;
     RECT  2.16 83.295 96.12 83.565 ;
     RECT  2.16 83.835 96.12 84.105 ;
     RECT  2.16 84.375 41.148 84.645 ;
     RECT  77.22 84.375 96.12 84.645 ;
     RECT  2.16 84.915 41.148 85.185 ;
     RECT  77.22 84.915 96.12 85.185 ;
     RECT  2.16 85.455 41.148 85.725 ;
     RECT  77.22 85.455 96.12 85.725 ;
     RECT  2.16 85.995 41.148 86.265 ;
     RECT  77.22 85.995 96.12 86.265 ;
     RECT  2.16 86.535 41.148 86.805 ;
     RECT  77.22 86.535 96.12 86.805 ;
     RECT  2.16 87.075 41.148 87.345 ;
     RECT  77.22 87.075 96.12 87.345 ;
     RECT  2.16 87.615 41.148 87.885 ;
     RECT  77.22 87.615 96.12 87.885 ;
     RECT  2.16 88.155 41.148 88.425 ;
     RECT  77.22 88.155 96.12 88.425 ;
     RECT  2.16 88.695 41.148 88.965 ;
     RECT  77.22 88.695 96.12 88.965 ;
     RECT  2.16 89.235 41.148 89.505 ;
     RECT  77.22 89.235 96.12 89.505 ;
     RECT  2.16 89.775 41.148 90.045 ;
     RECT  77.22 89.775 96.12 90.045 ;
     RECT  2.16 90.315 41.148 90.585 ;
     RECT  77.22 90.315 96.12 90.585 ;
     RECT  2.16 90.855 41.148 91.125 ;
     RECT  77.22 90.855 96.12 91.125 ;
     RECT  2.16 91.395 41.148 91.665 ;
     RECT  77.22 91.395 96.12 91.665 ;
     RECT  2.16 91.935 41.148 92.205 ;
     RECT  77.22 91.935 96.12 92.205 ;
     RECT  2.16 92.475 41.148 92.745 ;
     RECT  77.22 92.475 96.12 92.745 ;
     RECT  2.16 93.015 41.148 93.285 ;
     RECT  77.22 93.015 96.12 93.285 ;
     RECT  2.16 93.555 41.148 93.825 ;
     RECT  77.22 93.555 96.12 93.825 ;
     RECT  2.16 94.095 41.148 94.365 ;
     RECT  77.22 94.095 96.12 94.365 ;
     RECT  2.16 94.635 41.148 94.905 ;
     RECT  77.22 94.635 96.12 94.905 ;
     RECT  2.16 95.175 41.148 95.445 ;
     RECT  77.22 95.175 96.12 95.445 ;
     RECT  2.16 95.715 41.148 95.985 ;
     RECT  77.22 95.715 96.12 95.985 ;
     RECT  2.16 96.255 41.148 96.525 ;
     RECT  77.22 96.255 96.12 96.525 ;
     RECT  2.16 96.795 41.148 97.065 ;
     RECT  77.22 96.795 96.12 97.065 ;
     RECT  2.16 97.335 41.148 97.605 ;
     RECT  77.22 97.335 96.12 97.605 ;
     RECT  2.16 97.875 41.148 98.145 ;
     RECT  77.22 97.875 96.12 98.145 ;
     RECT  2.16 98.415 41.148 98.685 ;
     RECT  77.22 98.415 96.12 98.685 ;
     RECT  2.16 98.955 41.148 99.225 ;
     RECT  77.22 98.955 96.12 99.225 ;
     RECT  2.16 99.495 41.148 99.765 ;
     RECT  77.22 99.495 96.12 99.765 ;
     RECT  2.16 100.035 41.148 100.305 ;
     RECT  77.22 100.035 96.12 100.305 ;
     RECT  2.16 100.575 41.148 100.845 ;
     RECT  77.22 100.575 96.12 100.845 ;
     RECT  2.16 101.115 41.148 101.385 ;
     RECT  77.22 101.115 96.12 101.385 ;
     RECT  2.16 101.655 41.148 101.925 ;
     RECT  77.22 101.655 96.12 101.925 ;
     RECT  2.16 102.195 41.148 102.465 ;
     RECT  77.22 102.195 96.12 102.465 ;
     RECT  2.16 102.735 41.148 103.005 ;
     RECT  77.22 102.735 96.12 103.005 ;
     RECT  2.16 103.275 41.148 103.545 ;
     RECT  77.22 103.275 96.12 103.545 ;
     RECT  2.16 103.815 41.148 104.085 ;
     RECT  77.22 103.815 96.12 104.085 ;
     RECT  2.16 104.355 41.148 104.625 ;
     RECT  77.22 104.355 96.12 104.625 ;
     RECT  2.16 104.895 41.148 105.165 ;
     RECT  77.22 104.895 96.12 105.165 ;
     RECT  2.16 105.435 41.148 105.705 ;
     RECT  77.22 105.435 96.12 105.705 ;
     RECT  2.16 105.975 96.12 106.245 ;
     RECT  2.16 106.515 96.12 106.785 ;
     RECT  2.16 107.055 96.12 107.325 ;
     RECT  2.16 107.595 96.12 107.865 ;
     RECT  2.16 108.135 96.12 108.405 ;
     RECT  2.16 108.675 96.12 108.945 ;
     RECT  2.16 109.215 96.12 109.485 ;
     RECT  2.16 109.755 96.12 110.025 ;
     RECT  2.16 110.295 96.12 110.565 ;
     RECT  2.16 110.835 96.12 111.105 ;
     RECT  2.16 111.375 96.12 111.645 ;
     RECT  2.16 111.915 96.12 112.185 ;
     RECT  2.16 112.455 96.12 112.725 ;
     RECT  2.16 112.995 96.12 113.265 ;
     RECT  2.16 113.535 96.12 113.805 ;
     RECT  2.16 114.075 96.12 114.345 ;
     RECT  2.16 114.615 96.12 114.885 ;
     RECT  2.16 115.155 96.12 115.425 ;
     RECT  2.16 115.695 96.12 115.965 ;
     RECT  2.16 116.235 96.12 116.505 ;
     RECT  2.16 116.775 96.12 117.045 ;
     RECT  2.16 117.315 96.12 117.585 ;
     RECT  2.16 117.855 96.12 118.125 ;
     RECT  2.16 118.395 96.12 118.665 ;
     RECT  2.16 118.935 96.12 119.205 ;
     RECT  2.16 119.475 96.12 119.745 ;
     RECT  2.16 120.015 96.12 120.285 ;
     RECT  2.16 120.555 96.12 120.825 ;
     RECT  2.16 121.095 96.12 121.365 ;
     RECT  2.16 121.635 96.12 121.905 ;
     RECT  2.16 122.175 96.12 122.445 ;
     RECT  2.16 122.715 96.12 122.985 ;
     RECT  2.16 123.255 96.12 123.525 ;
     RECT  2.16 123.795 96.12 124.065 ;
     RECT  2.16 124.335 96.12 124.605 ;
     RECT  2.16 124.875 96.12 125.145 ;
     RECT  2.16 125.415 96.12 125.685 ;
     RECT  2.16 125.955 96.12 126.225 ;
     RECT  2.16 126.495 96.12 126.765 ;
     RECT  2.16 127.035 96.12 127.305 ;
     RECT  2.16 127.575 41.148 127.845 ;
     RECT  77.22 127.575 96.12 127.845 ;
     RECT  2.16 128.115 41.148 128.385 ;
     RECT  77.22 128.115 96.12 128.385 ;
     RECT  2.16 128.655 41.148 128.925 ;
     RECT  77.22 128.655 96.12 128.925 ;
     RECT  2.16 129.195 41.148 129.465 ;
     RECT  77.22 129.195 96.12 129.465 ;
     RECT  2.16 129.735 41.148 130.005 ;
     RECT  77.22 129.735 96.12 130.005 ;
     RECT  2.16 130.275 41.148 130.545 ;
     RECT  77.22 130.275 96.12 130.545 ;
     RECT  2.16 130.815 41.148 131.085 ;
     RECT  77.22 130.815 96.12 131.085 ;
     RECT  2.16 131.355 41.148 131.625 ;
     RECT  77.22 131.355 96.12 131.625 ;
     RECT  2.16 131.895 41.148 132.165 ;
     RECT  77.22 131.895 96.12 132.165 ;
     RECT  2.16 132.435 41.148 132.705 ;
     RECT  77.22 132.435 96.12 132.705 ;
     RECT  2.16 132.975 41.148 133.245 ;
     RECT  77.22 132.975 96.12 133.245 ;
     RECT  2.16 133.515 41.148 133.785 ;
     RECT  77.22 133.515 96.12 133.785 ;
     RECT  2.16 134.055 41.148 134.325 ;
     RECT  77.22 134.055 96.12 134.325 ;
     RECT  2.16 134.595 41.148 134.865 ;
     RECT  77.22 134.595 96.12 134.865 ;
     RECT  2.16 135.135 41.148 135.405 ;
     RECT  77.22 135.135 96.12 135.405 ;
     RECT  2.16 135.675 41.148 135.945 ;
     RECT  77.22 135.675 96.12 135.945 ;
     RECT  2.16 136.215 41.148 136.485 ;
     RECT  77.22 136.215 96.12 136.485 ;
     RECT  2.16 136.755 41.148 137.025 ;
     RECT  77.22 136.755 96.12 137.025 ;
     RECT  2.16 137.295 41.148 137.565 ;
     RECT  77.22 137.295 96.12 137.565 ;
     RECT  2.16 137.835 41.148 138.105 ;
     RECT  77.22 137.835 96.12 138.105 ;
     RECT  2.16 138.375 41.148 138.645 ;
     RECT  77.22 138.375 96.12 138.645 ;
     RECT  2.16 138.915 41.148 139.185 ;
     RECT  77.22 138.915 96.12 139.185 ;
     RECT  2.16 139.455 41.148 139.725 ;
     RECT  77.22 139.455 96.12 139.725 ;
     RECT  2.16 139.995 41.148 140.265 ;
     RECT  77.22 139.995 96.12 140.265 ;
     RECT  2.16 140.535 41.148 140.805 ;
     RECT  77.22 140.535 96.12 140.805 ;
     RECT  2.16 141.075 41.148 141.345 ;
     RECT  77.22 141.075 96.12 141.345 ;
     RECT  2.16 141.615 41.148 141.885 ;
     RECT  77.22 141.615 96.12 141.885 ;
     RECT  2.16 142.155 41.148 142.425 ;
     RECT  77.22 142.155 96.12 142.425 ;
     RECT  2.16 142.695 41.148 142.965 ;
     RECT  77.22 142.695 96.12 142.965 ;
     RECT  2.16 143.235 41.148 143.505 ;
     RECT  77.22 143.235 96.12 143.505 ;
     RECT  2.16 143.775 41.148 144.045 ;
     RECT  77.22 143.775 96.12 144.045 ;
     RECT  2.16 144.315 41.148 144.585 ;
     RECT  77.22 144.315 96.12 144.585 ;
     RECT  2.16 144.855 41.148 145.125 ;
     RECT  77.22 144.855 96.12 145.125 ;
     RECT  2.16 145.395 41.148 145.665 ;
     RECT  77.22 145.395 96.12 145.665 ;
     RECT  2.16 145.935 41.148 146.205 ;
     RECT  77.22 145.935 96.12 146.205 ;
     RECT  2.16 146.475 41.148 146.745 ;
     RECT  77.22 146.475 96.12 146.745 ;
     RECT  2.16 147.015 41.148 147.285 ;
     RECT  77.22 147.015 96.12 147.285 ;
     RECT  2.16 147.555 41.148 147.825 ;
     RECT  77.22 147.555 96.12 147.825 ;
     RECT  2.16 148.095 41.148 148.365 ;
     RECT  77.22 148.095 96.12 148.365 ;
     RECT  2.16 148.635 41.148 148.905 ;
     RECT  77.22 148.635 96.12 148.905 ;
     RECT  2.16 149.175 96.12 149.445 ;
     RECT  2.16 149.715 96.12 149.985 ;
     RECT  2.16 150.255 96.12 150.525 ;
     RECT  2.16 150.795 96.12 151.065 ;
     RECT  2.16 151.335 96.12 151.605 ;
     RECT  2.16 151.875 96.12 152.145 ;
     RECT  2.16 152.415 96.12 152.685 ;
     RECT  2.16 152.955 96.12 153.225 ;
     RECT  2.16 153.495 96.12 153.765 ;
     RECT  2.16 154.035 96.12 154.305 ;
     RECT  2.16 154.575 96.12 154.845 ;
     RECT  2.16 155.115 96.12 155.385 ;
     RECT  2.16 155.655 96.12 155.925 ;
     RECT  2.16 156.195 96.12 156.465 ;
     RECT  2.16 156.735 96.12 157.005 ;
     RECT  2.16 157.275 96.12 157.545 ;
     RECT  2.16 157.815 96.12 158.085 ;
     RECT  2.16 158.355 96.12 158.625 ;
     RECT  2.16 158.895 96.12 159.165 ;
     RECT  2.16 159.435 96.12 159.705 ;
     RECT  2.16 159.975 96.12 160.245 ;
     RECT  2.16 160.515 96.12 160.785 ;
     RECT  2.16 161.055 96.12 161.325 ;
     RECT  2.16 161.595 96.12 161.865 ;
     RECT  2.16 162.135 96.12 162.405 ;
     RECT  2.16 162.675 96.12 162.945 ;
     RECT  2.16 163.215 96.12 163.485 ;
     RECT  2.16 163.755 96.12 164.025 ;
     RECT  2.16 164.295 96.12 164.565 ;
     RECT  2.16 164.835 96.12 165.105 ;
     RECT  2.16 165.375 96.12 165.645 ;
     RECT  2.16 165.915 96.12 166.185 ;
     RECT  2.16 166.455 96.12 166.725 ;
     RECT  2.16 166.995 96.12 167.265 ;
     RECT  2.16 167.535 96.12 167.805 ;
     RECT  2.16 168.075 96.12 168.345 ;
    LAYER M1 ;
     RECT  2.16 2.151 96.12 41.049 ;
     RECT  43.2 43.2 75.192 60.504 ;
     RECT  2.16 41.049 41.148 62.631 ;
     RECT  77.22 41.049 96.12 62.631 ;
     RECT  2.16 62.631 96.12 84.249 ;
     RECT  43.2 86.4 75.192 103.704 ;
     RECT  2.16 84.249 41.148 105.831 ;
     RECT  77.22 84.249 96.12 105.831 ;
     RECT  2.16 105.831 96.12 127.449 ;
     RECT  43.2 129.6 75.192 146.904 ;
     RECT  2.16 127.449 41.148 149.031 ;
     RECT  77.22 127.449 96.12 149.031 ;
     RECT  2.16 149.031 96.12 168.489 ;
    LAYER M2 ;
     RECT  0.103 84.888 0.139 85.446 ;
     RECT  0.103 81.648 0.239 82.044 ;
     RECT  0.103 79.056 0.535 80.856 ;
     RECT  0.139 84.888 0.535 85.554 ;
     RECT  0.103 86.616 0.535 87.174 ;
     RECT  0.103 88.776 0.535 88.794 ;
     RECT  0.103 43.614 1.147 44.604 ;
     RECT  0.103 31.806 2.16 35.334 ;
     RECT  0.103 40.986 2.16 42.714 ;
     RECT  1.147 43.614 2.16 44.676 ;
     RECT  0.535 79.056 2.16 81.234 ;
     RECT  0.239 82.026 2.16 82.044 ;
     RECT  0.103 83.646 2.16 83.664 ;
     RECT  0.535 84.888 2.16 85.824 ;
     RECT  0.535 86.616 2.16 88.794 ;
     RECT  0.103 121.338 2.16 123.084 ;
     RECT  37.831 170.586 37.903 170.604 ;
     RECT  37.903 170.514 38.219 170.604 ;
     RECT  2.16 2.151 41.148 168.489 ;
     RECT  41.148 50.976 41.315 56.754 ;
     RECT  41.148 85.932 41.387 89.766 ;
     RECT  41.148 93.996 41.387 100.134 ;
     RECT  41.148 130.554 41.423 133.434 ;
     RECT  41.387 96.696 41.459 100.134 ;
     RECT  41.423 130.752 41.459 133.434 ;
     RECT  41.315 50.976 41.495 54.324 ;
     RECT  41.459 97.236 41.495 100.134 ;
     RECT  41.315 55.386 41.531 56.754 ;
     RECT  41.387 93.996 41.531 95.904 ;
     RECT  41.148 47.358 41.639 49.338 ;
     RECT  41.459 130.752 41.639 132.966 ;
     RECT  41.639 47.592 41.675 49.338 ;
     RECT  41.675 47.781 41.711 49.338 ;
     RECT  41.387 86.544 41.747 89.766 ;
     RECT  41.747 86.616 41.819 89.766 ;
     RECT  41.148 105.831 41.891 127.566 ;
     RECT  41.148 60.552 41.899 61.614 ;
     RECT  41.148 62.631 41.899 84.249 ;
     RECT  41.148 101.016 41.927 101.034 ;
     RECT  41.148 128.898 41.927 129.528 ;
     RECT  41.531 55.458 41.963 56.754 ;
     RECT  41.899 62.631 42.043 84.294 ;
     RECT  41.495 97.416 42.143 99.684 ;
     RECT  41.495 50.976 42.179 52.974 ;
     RECT  42.043 62.631 42.179 84.366 ;
     RECT  42.143 97.416 42.179 99.414 ;
     RECT  41.148 137.106 42.179 142.488 ;
     RECT  41.148 44.388 42.215 46.332 ;
     RECT  42.179 50.976 42.215 52.074 ;
     RECT  41.963 55.458 42.215 55.476 ;
     RECT  41.531 93.996 42.215 95.544 ;
     RECT  41.927 128.898 42.215 128.916 ;
     RECT  41.639 130.752 42.215 132.696 ;
     RECT  42.215 50.976 42.251 51.084 ;
     RECT  42.215 130.752 42.251 131.616 ;
     RECT  42.179 138.006 42.251 142.488 ;
     RECT  42.251 51.066 42.287 51.084 ;
     RECT  42.215 132.372 42.287 132.696 ;
     RECT  42.287 132.678 42.323 132.696 ;
     RECT  41.819 87.12 42.431 89.766 ;
     RECT  42.215 51.876 42.467 52.074 ;
     RECT  42.431 87.12 42.467 88.65 ;
     RECT  41.148 147.096 42.547 148.014 ;
     RECT  41.891 105.831 42.619 127.449 ;
     RECT  41.148 103.752 42.655 104.922 ;
     RECT  42.619 105.75 42.655 127.449 ;
     RECT  41.899 60.552 42.691 61.65 ;
     RECT  42.547 147.06 42.691 148.014 ;
     RECT  41.148 149.031 42.691 168.489 ;
     RECT  42.691 60.552 42.727 61.839 ;
     RECT  42.179 62.631 42.727 84.249 ;
     RECT  42.655 103.752 42.799 127.449 ;
     RECT  41.148 42.57 43.2 43.164 ;
     RECT  42.215 44.856 43.2 46.332 ;
     RECT  41.711 47.781 43.2 48.762 ;
     RECT  42.467 51.876 43.2 51.894 ;
     RECT  42.179 52.866 43.2 52.974 ;
     RECT  41.495 53.874 43.2 54.324 ;
     RECT  41.963 56.268 43.2 56.754 ;
     RECT  42.727 60.552 43.2 84.249 ;
     RECT  42.467 87.12 43.2 88.344 ;
     RECT  42.431 89.748 43.2 89.766 ;
     RECT  42.655 90.63 43.2 90.648 ;
     RECT  41.148 92.826 43.2 92.844 ;
     RECT  42.215 93.996 43.2 94.284 ;
     RECT  42.215 95.184 43.2 95.544 ;
     RECT  42.179 97.416 43.2 99.216 ;
     RECT  42.799 103.752 43.2 127.674 ;
     RECT  42.251 131.058 43.2 131.616 ;
     RECT  42.251 138.006 43.2 139.014 ;
     RECT  42.251 140.076 43.2 142.488 ;
     RECT  42.691 147.06 43.2 168.489 ;
     RECT  43.2 86.4 43.331 127.674 ;
     RECT  43.2 42.57 49.667 84.249 ;
     RECT  43.331 86.4 74.443 127.449 ;
     RECT  43.2 129.6 74.659 168.489 ;
     RECT  74.443 86.4 74.731 128.142 ;
     RECT  74.731 86.4 74.767 128.259 ;
     RECT  74.659 129.402 74.767 168.489 ;
     RECT  74.767 86.4 75.091 168.489 ;
     RECT  75.091 86.121 75.127 168.489 ;
     RECT  49.667 42.57 75.192 61.65 ;
     RECT  75.127 86.076 75.192 168.489 ;
     RECT  75.192 86.076 75.235 87.03 ;
     RECT  49.667 62.514 75.271 84.249 ;
     RECT  75.192 53.334 75.335 54.738 ;
     RECT  75.235 86.004 75.335 87.03 ;
     RECT  75.192 91.296 75.335 91.314 ;
     RECT  75.192 96.57 75.335 98.91 ;
     RECT  75.192 142.506 75.335 142.524 ;
     RECT  75.192 58.698 75.371 58.716 ;
     RECT  75.271 62.514 75.371 84.942 ;
     RECT  75.192 103.446 75.371 130.536 ;
     RECT  75.192 146.448 75.371 168.489 ;
     RECT  75.192 42.57 75.407 43.164 ;
     RECT  75.335 86.121 75.407 87.03 ;
     RECT  75.192 44.928 75.551 45.252 ;
     RECT  75.371 128.7 75.551 130.536 ;
     RECT  75.371 62.514 75.587 84.294 ;
     RECT  75.407 86.346 75.623 87.03 ;
     RECT  75.371 103.446 75.623 127.602 ;
     RECT  75.551 128.7 75.767 128.799 ;
     RECT  75.623 103.446 75.947 127.494 ;
     RECT  75.335 53.334 76.063 54.324 ;
     RECT  75.192 131.598 76.063 132.084 ;
     RECT  75.192 139.896 76.063 141.174 ;
     RECT  75.551 129.672 76.091 130.536 ;
     RECT  75.407 42.57 76.099 43.128 ;
     RECT  75.335 97.506 76.099 98.91 ;
     RECT  76.063 53.334 76.135 55.008 ;
     RECT  76.135 53.334 76.207 55.512 ;
     RECT  76.091 130.446 76.235 130.536 ;
     RECT  75.192 88.506 76.279 88.722 ;
     RECT  75.192 135.072 76.279 135.09 ;
     RECT  75.192 136.152 76.279 137.358 ;
     RECT  76.063 91.404 76.315 91.422 ;
     RECT  75.192 92.79 76.315 93.348 ;
     RECT  76.279 135.072 76.315 137.358 ;
     RECT  76.235 130.518 76.343 130.536 ;
     RECT  76.207 53.334 76.351 56.052 ;
     RECT  75.623 86.472 76.351 87.03 ;
     RECT  76.315 91.332 76.351 91.422 ;
     RECT  76.315 92.79 76.351 93.816 ;
     RECT  75.192 94.608 76.351 95.13 ;
     RECT  76.279 88.506 76.379 88.92 ;
     RECT  76.099 42.156 76.387 43.128 ;
     RECT  75.551 45 76.387 45.252 ;
     RECT  75.192 47.736 76.387 48.996 ;
     RECT  75.192 51.21 76.387 51.228 ;
     RECT  76.351 52.866 76.387 56.052 ;
     RECT  76.351 92.79 76.387 95.13 ;
     RECT  75.335 96.57 76.387 96.588 ;
     RECT  76.063 131.436 76.387 132.084 ;
     RECT  75.192 133.596 76.387 133.614 ;
     RECT  76.315 134.874 76.387 137.358 ;
     RECT  76.387 42.156 76.423 43.29 ;
     RECT  76.387 44.316 76.423 45.252 ;
     RECT  76.387 130.896 76.423 132.624 ;
     RECT  76.387 133.596 76.423 133.974 ;
     RECT  76.387 134.874 76.423 138.87 ;
     RECT  76.423 130.896 76.487 138.87 ;
     RECT  76.487 130.986 76.639 138.87 ;
     RECT  76.063 139.896 76.639 141.606 ;
     RECT  76.171 101.736 76.675 101.754 ;
     RECT  76.351 90.936 76.927 91.422 ;
     RECT  76.387 92.25 76.927 96.75 ;
     RECT  76.639 130.986 76.999 141.606 ;
     RECT  76.135 142.434 76.999 142.452 ;
     RECT  41.148 2.151 77.22 41.049 ;
     RECT  76.423 42.156 77.22 45.252 ;
     RECT  76.387 47.736 77.22 56.052 ;
     RECT  76.099 59.706 77.22 59.724 ;
     RECT  75.192 60.552 77.22 61.65 ;
     RECT  75.587 62.514 77.22 84.249 ;
     RECT  76.351 86.346 77.22 87.03 ;
     RECT  76.379 88.506 77.22 88.722 ;
     RECT  76.279 89.946 77.22 89.964 ;
     RECT  76.927 90.936 77.22 96.75 ;
     RECT  76.099 97.506 77.22 99.144 ;
     RECT  75.192 99.972 77.22 99.99 ;
     RECT  76.675 101.736 77.22 101.844 ;
     RECT  75.947 103.446 77.22 127.449 ;
     RECT  76.091 129.672 77.22 129.69 ;
     RECT  76.999 130.986 77.22 142.452 ;
     RECT  75.192 145.332 77.22 145.35 ;
     RECT  75.371 147.06 77.22 168.489 ;
     RECT  77.22 2.151 96.12 168.489 ;
     RECT  96.12 39.798 96.323 39.816 ;
     RECT  96.12 81.684 96.323 85.446 ;
     RECT  96.12 139.158 96.323 142.722 ;
     RECT  96.12 41.148 96.359 43.596 ;
     RECT  96.12 52.794 96.359 57.402 ;
     RECT  96.12 96.3 96.359 96.624 ;
     RECT  96.323 139.23 96.359 142.722 ;
     RECT  96.359 139.23 96.899 142.524 ;
     RECT  96.359 54.99 96.935 57.402 ;
     RECT  96.323 81.684 96.935 84.636 ;
     RECT  96.12 86.238 96.935 86.256 ;
     RECT  96.12 97.38 96.935 100.872 ;
     RECT  96.899 139.23 96.935 140.562 ;
     RECT  96.359 43.074 96.971 43.596 ;
     RECT  96.935 82.26 96.971 82.278 ;
     RECT  96.971 43.074 97.007 43.164 ;
     RECT  96.935 55.026 97.007 55.044 ;
     RECT  96.935 97.38 97.007 100.098 ;
     RECT  96.359 41.148 97.439 42.084 ;
     RECT  97.439 41.148 97.475 41.166 ;
     RECT  97.439 42.03 97.475 42.084 ;
     RECT  97.007 43.074 97.511 43.092 ;
     RECT  96.359 52.794 97.511 53.964 ;
     RECT  96.935 56.034 97.511 57.402 ;
     RECT  96.935 83.07 97.511 84.636 ;
     RECT  96.359 96.534 97.511 96.624 ;
     RECT  97.007 97.38 97.511 97.398 ;
     RECT  97.007 98.424 97.511 100.098 ;
     RECT  96.935 139.23 97.511 139.824 ;
     RECT  96.899 141.426 97.511 142.524 ;
     RECT  97.475 42.03 97.547 42.048 ;
     RECT  97.511 98.424 97.547 98.982 ;
     RECT  97.511 100.008 97.547 100.026 ;
     RECT  97.511 139.23 97.547 139.284 ;
     RECT  97.547 139.266 97.619 139.284 ;
     RECT  98.167 81.756 98.267 81.774 ;
    LAYER M3 ;
     RECT  2.415 2.143 2.505 2.413 ;
     RECT  5.115 2.143 5.205 2.413 ;
     RECT  7.815 2.143 7.905 2.413 ;
     RECT  10.515 2.143 10.605 2.413 ;
     RECT  13.215 2.143 13.305 2.413 ;
     RECT  15.915 2.143 16.005 2.413 ;
     RECT  18.615 2.143 18.705 2.413 ;
     RECT  21.315 2.143 21.405 2.413 ;
     RECT  24.015 2.143 24.105 2.413 ;
     RECT  26.715 2.143 26.805 2.413 ;
     RECT  29.415 2.143 29.505 2.413 ;
     RECT  32.115 2.143 32.205 2.413 ;
     RECT  34.815 2.143 34.905 2.413 ;
     RECT  37.515 2.143 37.605 2.413 ;
     RECT  40.215 2.143 40.305 2.413 ;
     RECT  42.915 2.143 43.005 2.413 ;
     RECT  45.615 2.143 45.705 2.413 ;
     RECT  48.315 2.143 48.405 2.413 ;
     RECT  51.015 2.143 51.105 2.413 ;
     RECT  53.715 2.143 53.805 2.413 ;
     RECT  56.415 2.143 56.505 2.413 ;
     RECT  59.115 2.143 59.205 2.413 ;
     RECT  61.815 2.143 61.905 2.413 ;
     RECT  64.515 2.143 64.605 2.413 ;
     RECT  67.215 2.143 67.305 2.413 ;
     RECT  69.915 2.143 70.005 2.413 ;
     RECT  72.615 2.143 72.705 2.413 ;
     RECT  75.315 2.143 75.405 2.413 ;
     RECT  78.015 2.143 78.105 2.413 ;
     RECT  80.715 2.143 80.805 2.413 ;
     RECT  83.415 2.143 83.505 2.413 ;
     RECT  86.115 2.143 86.205 2.413 ;
     RECT  88.815 2.143 88.905 2.413 ;
     RECT  91.515 2.143 91.605 2.413 ;
     RECT  94.215 2.143 94.305 2.413 ;
     RECT  0.108 31.675 0.126 31.723 ;
     RECT  5.115 2.413 5.397 31.765 ;
     RECT  3.852 31.723 3.87 31.801 ;
     RECT  4.824 31.765 5.598 31.801 ;
     RECT  3.852 31.801 6.102 31.829 ;
     RECT  0.108 31.723 0.198 31.853 ;
     RECT  3.996 31.829 6.102 31.927 ;
     RECT  7.02 31.771 7.038 31.927 ;
     RECT  2.415 2.413 2.697 32.059 ;
     RECT  3.996 31.927 7.038 32.063 ;
     RECT  6.624 32.063 7.038 32.071 ;
     RECT  7.815 2.413 8.097 32.071 ;
     RECT  2.415 32.059 2.79 32.161 ;
     RECT  2.415 32.161 2.862 32.261 ;
     RECT  3.996 32.063 5.814 32.333 ;
     RECT  2.415 32.261 2.697 32.395 ;
     RECT  2.304 32.395 2.697 32.459 ;
     RECT  6.624 32.071 8.097 32.467 ;
     RECT  0.108 31.853 0.126 32.683 ;
     RECT  0.108 32.683 0.234 32.813 ;
     RECT  4.14 32.333 5.814 32.845 ;
     RECT  6.624 32.467 8.298 32.845 ;
     RECT  9.072 32.341 9.09 32.845 ;
     RECT  2.415 32.459 2.697 33.007 ;
     RECT  4.14 32.845 9.09 33.043 ;
     RECT  2.415 33.007 3.33 33.241 ;
     RECT  4.14 33.043 9.306 33.241 ;
     RECT  2.415 33.241 9.306 33.403 ;
     RECT  2.304 33.403 9.306 33.809 ;
     RECT  3.6 33.809 9.306 33.889 ;
     RECT  3.6 33.889 9.45 33.953 ;
     RECT  2.304 33.809 2.79 33.989 ;
     RECT  39.024 33.889 39.042 34.627 ;
     RECT  3.6 33.953 6.03 34.699 ;
     RECT  2.415 33.989 2.79 34.735 ;
     RECT  3.6 34.699 6.066 34.735 ;
     RECT  6.804 33.953 9.45 34.735 ;
     RECT  10.515 2.413 10.797 34.735 ;
     RECT  2.415 34.735 6.066 34.747 ;
     RECT  6.804 34.735 10.797 34.747 ;
     RECT  0.108 32.813 0.126 34.843 ;
     RECT  0.108 34.843 0.162 34.973 ;
     RECT  2.415 34.747 10.797 34.973 ;
     RECT  39.024 34.627 39.078 35.041 ;
     RECT  40.215 2.413 40.497 35.041 ;
     RECT  39.024 35.041 40.497 35.131 ;
     RECT  6.768 34.973 10.797 35.159 ;
     RECT  0.108 34.973 0.126 35.339 ;
     RECT  2.415 34.973 6.03 35.563 ;
     RECT  2.304 35.563 6.03 35.779 ;
     RECT  2.232 35.779 6.03 35.885 ;
     RECT  2.304 35.885 6.03 36.211 ;
     RECT  6.768 35.159 8.622 36.211 ;
     RECT  2.304 36.211 8.622 36.269 ;
     RECT  2.415 36.269 8.622 36.509 ;
     RECT  9.396 35.159 10.797 36.589 ;
     RECT  94.215 2.413 94.497 37.867 ;
     RECT  95.904 37.831 95.922 37.901 ;
     RECT  94.032 37.867 94.497 37.963 ;
     RECT  94.032 37.963 94.914 37.975 ;
     RECT  94.032 37.975 95.886 38.137 ;
     RECT  42.12 32.269 42.138 38.515 ;
     RECT  42.915 2.413 43.197 38.515 ;
     RECT  93.924 38.137 95.886 38.551 ;
     RECT  42.12 38.515 43.197 38.713 ;
     RECT  6.768 36.509 8.622 38.749 ;
     RECT  9.396 36.589 11.106 38.749 ;
     RECT  93.492 38.551 95.886 38.947 ;
     RECT  92.952 38.947 95.886 38.983 ;
     RECT  92.88 38.983 95.886 39.181 ;
     RECT  75.315 2.413 75.597 39.289 ;
     RECT  91.515 2.413 91.797 39.325 ;
     RECT  86.115 2.413 86.397 39.361 ;
     RECT  91.152 39.325 91.797 39.361 ;
     RECT  39.024 35.131 40.95 39.479 ;
     RECT  82.08 39.181 82.098 39.479 ;
     RECT  90.54 39.361 91.797 39.487 ;
     RECT  92.844 39.181 95.886 39.499 ;
     RECT  92.736 39.499 95.886 39.547 ;
     RECT  86.115 39.361 86.67 39.551 ;
     RECT  92.592 39.547 95.886 39.595 ;
     RECT  42.084 38.713 43.197 39.631 ;
     RECT  75.315 39.289 75.654 39.631 ;
     RECT  88.815 2.413 89.097 39.631 ;
     RECT  90.144 39.487 91.797 39.631 ;
     RECT  92.592 39.595 96.318 39.631 ;
     RECT  39.024 39.479 40.734 39.721 ;
     RECT  88.815 39.631 91.797 39.793 ;
     RECT  92.556 39.631 96.318 39.821 ;
     RECT  78.015 2.413 78.297 39.901 ;
     RECT  78.015 39.901 78.642 40.019 ;
     RECT  84.816 39.901 84.834 40.019 ;
     RECT  88.344 39.793 91.797 40.027 ;
     RECT  92.556 39.821 95.922 40.027 ;
     RECT  88.344 40.027 95.922 40.127 ;
     RECT  78.015 40.019 78.297 40.171 ;
     RECT  84.708 40.027 84.726 40.199 ;
     RECT  75.132 39.631 75.654 40.441 ;
     RECT  83.415 2.413 83.697 40.567 ;
     RECT  98.1 40.459 98.118 40.589 ;
     RECT  75.132 40.441 75.906 40.639 ;
     RECT  41.832 39.631 43.197 40.667 ;
     RECT  38.772 39.721 40.734 40.703 ;
     RECT  75.132 40.639 76.41 40.711 ;
     RECT  77.364 40.171 78.297 40.711 ;
     RECT  41.94 40.667 43.197 40.787 ;
     RECT  45.615 2.413 45.897 40.787 ;
     RECT  48.315 2.413 48.597 40.787 ;
     RECT  51.015 2.413 51.297 40.787 ;
     RECT  53.715 2.413 53.997 40.787 ;
     RECT  56.415 2.413 56.697 40.787 ;
     RECT  59.115 2.413 59.397 40.787 ;
     RECT  61.815 2.413 62.097 40.787 ;
     RECT  64.515 2.413 64.797 40.787 ;
     RECT  67.215 2.413 67.497 40.787 ;
     RECT  69.915 2.413 70.197 40.787 ;
     RECT  72.615 2.413 72.897 40.787 ;
     RECT  82.656 40.603 82.674 40.801 ;
     RECT  83.415 40.567 84.15 40.829 ;
     RECT  90.648 40.127 95.922 40.829 ;
     RECT  82.152 40.801 82.674 40.837 ;
     RECT  90.648 40.829 95.814 40.987 ;
     RECT  82.08 40.837 82.674 41.009 ;
     RECT  2.415 36.509 6.03 41.035 ;
     RECT  86.115 39.551 86.397 41.035 ;
     RECT  45.615 40.787 45.705 41.057 ;
     RECT  48.315 40.787 48.405 41.057 ;
     RECT  51.015 40.787 51.105 41.057 ;
     RECT  53.715 40.787 53.805 41.057 ;
     RECT  56.415 40.787 56.505 41.057 ;
     RECT  59.115 40.787 59.205 41.057 ;
     RECT  61.815 40.787 61.905 41.057 ;
     RECT  64.515 40.787 64.605 41.057 ;
     RECT  67.215 40.787 67.305 41.057 ;
     RECT  69.915 40.787 70.005 41.057 ;
     RECT  72.615 40.787 72.705 41.057 ;
     RECT  85.788 41.035 86.397 41.071 ;
     RECT  2.304 41.035 6.03 41.099 ;
     RECT  82.08 41.009 82.17 41.099 ;
     RECT  83.415 40.829 83.697 41.107 ;
     RECT  0.108 40.891 0.126 41.131 ;
     RECT  85.788 41.071 86.67 41.135 ;
     RECT  82.152 41.099 82.17 41.207 ;
     RECT  85.896 41.135 86.67 41.207 ;
     RECT  88.344 40.127 89.586 41.251 ;
     RECT  90.504 40.987 95.814 41.251 ;
     RECT  83.412 41.107 83.697 41.279 ;
     RECT  39.024 40.703 40.734 41.449 ;
     RECT  75.132 40.711 78.297 41.597 ;
     RECT  97.452 41.035 97.47 41.611 ;
     RECT  88.344 41.251 95.814 41.639 ;
     RECT  97.416 41.611 97.47 41.711 ;
     RECT  0.108 41.131 0.162 41.741 ;
     RECT  93.96 41.639 95.814 41.755 ;
     RECT  97.452 41.711 97.47 41.755 ;
     RECT  75.204 41.597 78.297 41.989 ;
     RECT  80.715 2.413 80.997 41.989 ;
     RECT  2.415 41.099 6.03 42.025 ;
     RECT  6.768 38.749 11.106 42.025 ;
     RECT  93.96 41.755 95.922 42.043 ;
     RECT  88.344 41.639 93.15 42.053 ;
     RECT  97.452 41.755 97.542 42.053 ;
     RECT  2.415 42.025 11.106 42.061 ;
     RECT  82.656 41.953 82.674 42.061 ;
     RECT  83.415 41.279 83.697 42.061 ;
     RECT  80.715 41.989 81.522 42.089 ;
     RECT  97.452 42.053 97.47 42.089 ;
     RECT  75.204 41.989 78.678 42.151 ;
     RECT  2.376 42.061 11.106 42.179 ;
     RECT  84.852 41.953 84.87 42.179 ;
     RECT  82.656 42.061 83.697 42.259 ;
     RECT  88.344 42.053 89.586 42.295 ;
     RECT  82.548 42.259 83.697 42.331 ;
     RECT  75.204 42.151 78.93 42.421 ;
     RECT  86.115 41.207 86.67 42.421 ;
     RECT  90.36 42.053 93.15 42.421 ;
     RECT  93.96 42.043 96.354 42.421 ;
     RECT  82.476 42.331 83.697 42.457 ;
     RECT  90.36 42.421 96.354 42.509 ;
     RECT  88.272 42.295 89.586 42.529 ;
     RECT  80.715 42.089 81.486 42.557 ;
     RECT  39.024 41.449 40.878 42.565 ;
     RECT  75.204 42.421 79.506 42.565 ;
     RECT  80.715 42.557 80.997 42.565 ;
     RECT  86.115 42.421 86.742 42.601 ;
     RECT  95.76 42.509 96.354 42.619 ;
     RECT  82.476 42.457 83.934 42.719 ;
     RECT  82.476 42.719 83.754 42.755 ;
     RECT  86.115 42.601 87.354 42.755 ;
     RECT  88.164 42.529 89.586 42.755 ;
     RECT  39.024 42.565 40.914 42.758 ;
     RECT  95.76 42.619 96.966 42.907 ;
     RECT  82.476 42.755 83.697 43.033 ;
     RECT  90.36 42.509 94.878 43.061 ;
     RECT  39.024 42.758 40.95 43.069 ;
     RECT  88.815 42.755 89.586 43.069 ;
     RECT  90.36 43.061 90.702 43.069 ;
     RECT  95.76 42.907 97.506 43.085 ;
     RECT  91.44 43.061 94.878 43.097 ;
     RECT  96.912 43.085 97.506 43.097 ;
     RECT  38.988 43.069 40.95 43.105 ;
     RECT  86.115 42.755 86.742 43.133 ;
     RECT  88.815 43.069 90.702 43.133 ;
     RECT  91.44 43.097 93.258 43.133 ;
     RECT  2.415 42.179 11.106 43.169 ;
     RECT  91.476 43.133 93.258 43.169 ;
     RECT  2.415 43.169 10.797 43.195 ;
     RECT  41.94 40.787 43.074 43.2 ;
     RECT  70.74 43.069 70.758 43.2 ;
     RECT  75.204 42.565 80.997 43.2 ;
     RECT  96.912 43.097 97.002 43.229 ;
     RECT  86.115 43.133 86.67 43.259 ;
     RECT  41.94 43.2 80.997 43.303 ;
     RECT  96.912 43.229 96.966 43.331 ;
     RECT  82.368 43.033 83.697 43.439 ;
     RECT  95.76 43.085 95.994 43.439 ;
     RECT  83.34 43.439 83.697 43.501 ;
     RECT  94.032 43.097 94.878 43.529 ;
     RECT  41.94 43.303 81.558 43.565 ;
     RECT  91.512 43.169 93.258 43.565 ;
     RECT  88.815 43.133 90.63 43.601 ;
     RECT  96.948 43.331 96.966 43.601 ;
     RECT  37.515 2.413 37.797 43.609 ;
     RECT  38.988 43.105 40.986 43.609 ;
     RECT  88.815 43.601 90.378 43.637 ;
     RECT  77.22 43.565 81.558 43.771 ;
     RECT  95.76 43.439 95.922 43.799 ;
     RECT  34.815 2.413 35.097 43.807 ;
     RECT  95.76 43.799 95.778 43.835 ;
     RECT  83.34 43.501 83.754 44.107 ;
     RECT  94.215 43.529 94.878 44.213 ;
     RECT  2.304 43.195 10.797 44.249 ;
     RECT  86.115 43.259 86.397 44.311 ;
     RECT  37.515 43.609 40.986 44.419 ;
     RECT  41.94 43.565 76.446 44.419 ;
     RECT  83.34 44.107 83.826 44.455 ;
     RECT  0.108 41.741 0.126 44.609 ;
     RECT  83.34 44.455 84.294 44.609 ;
     RECT  90.072 43.637 90.378 44.617 ;
     RECT  1.152 43.483 1.17 44.681 ;
     RECT  90.072 44.617 90.702 44.717 ;
     RECT  2.415 44.249 10.797 44.753 ;
     RECT  85.284 44.617 85.302 44.753 ;
     RECT  83.34 44.609 84.222 44.761 ;
     RECT  86.115 44.311 86.922 44.761 ;
     RECT  34.815 43.807 35.37 44.851 ;
     RECT  2.415 44.753 9.63 44.879 ;
     RECT  91.515 43.565 93.258 44.879 ;
     RECT  34.776 44.851 35.37 44.987 ;
     RECT  90.072 44.717 90.09 45.059 ;
     RECT  88.815 43.637 89.154 45.121 ;
     RECT  2.415 44.879 8.73 45.149 ;
     RECT  9.468 44.879 9.63 45.149 ;
     RECT  83.232 44.761 84.222 45.185 ;
     RECT  77.22 43.771 82.026 45.193 ;
     RECT  0.144 45.067 0.162 45.197 ;
     RECT  77.22 45.193 82.062 45.293 ;
     RECT  2.415 45.149 8.694 45.355 ;
     RECT  2.304 45.355 8.694 45.419 ;
     RECT  83.232 45.185 84.114 45.455 ;
     RECT  77.22 45.293 79.218 45.533 ;
     RECT  77.22 45.533 78.714 45.563 ;
     RECT  80.064 45.293 82.062 45.697 ;
     RECT  83.232 45.455 83.697 45.697 ;
     RECT  2.415 45.419 8.694 45.761 ;
     RECT  37.515 44.419 76.446 46.109 ;
     RECT  34.815 44.987 35.37 46.229 ;
     RECT  91.515 44.879 93.114 46.229 ;
     RECT  91.515 46.229 92.322 46.265 ;
     RECT  80.064 45.697 83.697 46.409 ;
     RECT  34.815 46.229 35.097 46.471 ;
     RECT  37.515 46.109 76.41 46.493 ;
     RECT  77.22 45.563 78.642 46.747 ;
     RECT  37.515 46.493 76.086 46.877 ;
     RECT  83.232 46.409 83.697 46.877 ;
     RECT  37.515 46.877 41.706 46.973 ;
     RECT  93.06 46.229 93.114 47.039 ;
     RECT  80.064 46.409 82.062 47.069 ;
     RECT  80.064 47.069 81.522 47.165 ;
     RECT  3.42 45.761 8.694 47.183 ;
     RECT  91.515 46.265 92.07 47.191 ;
     RECT  93.06 47.039 93.078 47.191 ;
     RECT  34.776 46.471 35.097 47.219 ;
     RECT  42.768 46.877 76.086 47.261 ;
     RECT  83.415 46.877 83.697 47.281 ;
     RECT  90.648 47.317 90.666 47.417 ;
     RECT  91.515 47.191 93.078 47.417 ;
     RECT  91.515 47.417 91.962 47.461 ;
     RECT  77.22 46.747 78.678 47.563 ;
     RECT  91.476 47.461 91.962 47.615 ;
     RECT  83.415 47.281 84.186 47.659 ;
     RECT  77.22 47.563 78.714 47.693 ;
     RECT  37.515 46.973 41.67 47.741 ;
     RECT  83.088 47.659 84.186 47.759 ;
     RECT  37.515 47.741 41.202 47.804 ;
     RECT  3.42 47.183 8.658 48.029 ;
     RECT  83.415 47.759 84.186 48.163 ;
     RECT  3.42 48.029 8.622 48.191 ;
     RECT  42.192 47.857 42.21 48.199 ;
     RECT  42.192 48.199 42.246 48.221 ;
     RECT  4.5 48.191 8.622 48.263 ;
     RECT  42.228 48.221 42.246 48.361 ;
     RECT  43.092 47.261 76.086 48.361 ;
     RECT  42.228 48.361 76.086 48.605 ;
     RECT  42.768 48.605 76.086 48.763 ;
     RECT  3.42 48.191 3.438 48.839 ;
     RECT  42.768 48.763 76.41 48.989 ;
     RECT  42.804 48.989 76.41 49.085 ;
     RECT  9.468 45.149 9.486 49.109 ;
     RECT  37.515 47.804 41.13 49.279 ;
     RECT  43.2 49.085 76.41 49.351 ;
     RECT  4.5 48.263 6.642 49.379 ;
     RECT  43.2 49.351 76.446 49.565 ;
     RECT  7.524 48.263 8.622 49.649 ;
     RECT  43.2 49.565 76.41 49.661 ;
     RECT  34.815 47.219 35.097 49.711 ;
     RECT  4.5 49.379 6.318 49.739 ;
     RECT  4.5 49.739 5.814 49.919 ;
     RECT  37.515 49.279 41.706 50.009 ;
     RECT  83.415 48.163 84.258 50.009 ;
     RECT  38.772 50.009 41.706 50.045 ;
     RECT  5.115 49.919 5.814 50.189 ;
     RECT  7.815 49.649 8.622 50.279 ;
     RECT  38.772 50.045 41.13 50.333 ;
     RECT  34.776 49.711 35.097 50.351 ;
     RECT  86.115 44.761 87.498 50.549 ;
     RECT  91.515 47.615 91.962 50.629 ;
     RECT  91.515 50.629 92.034 50.665 ;
     RECT  87.48 50.549 87.498 50.819 ;
     RECT  93.06 47.417 93.078 50.819 ;
     RECT  88.815 45.121 89.406 50.935 ;
     RECT  42.228 50.971 42.246 51.061 ;
     RECT  42.228 51.061 42.282 51.067 ;
     RECT  38.808 50.333 41.13 51.163 ;
     RECT  42.156 51.067 42.282 51.163 ;
     RECT  43.2 49.661 75.192 51.205 ;
     RECT  76.392 49.661 76.41 51.205 ;
     RECT  91.515 50.665 92.214 51.205 ;
     RECT  43.2 51.205 76.41 51.389 ;
     RECT  37.515 50.009 37.797 51.475 ;
     RECT  38.808 51.163 42.282 51.475 ;
     RECT  37.515 51.475 42.282 51.533 ;
     RECT  43.2 51.389 75.192 51.547 ;
     RECT  38.628 51.533 42.282 51.737 ;
     RECT  77.22 47.693 78.297 52.007 ;
     RECT  38.916 51.737 42.282 52.051 ;
     RECT  43.092 51.547 75.192 52.051 ;
     RECT  91.44 51.205 92.214 52.285 ;
     RECT  93.096 50.935 93.258 52.285 ;
     RECT  94.215 44.213 94.497 52.285 ;
     RECT  91.44 52.285 94.497 52.321 ;
     RECT  38.916 52.051 75.192 52.445 ;
     RECT  77.4 52.007 78.297 52.475 ;
     RECT  38.916 52.445 41.598 52.591 ;
     RECT  80.064 47.165 80.997 52.619 ;
     RECT  91.44 52.321 94.554 52.681 ;
     RECT  37.515 51.533 37.797 52.717 ;
     RECT  38.772 52.591 41.598 52.717 ;
     RECT  37.515 52.717 41.598 52.781 ;
     RECT  95.76 52.411 95.778 52.825 ;
     RECT  76.392 51.389 76.41 52.861 ;
     RECT  88.815 50.935 89.766 52.861 ;
     RECT  76.356 52.861 76.41 53.015 ;
     RECT  76.356 53.015 76.374 53.117 ;
     RECT  88.815 52.861 90.666 53.131 ;
     RECT  91.44 52.681 94.662 53.131 ;
     RECT  95.76 52.825 95.922 53.131 ;
     RECT  88.815 53.131 90.702 53.221 ;
     RECT  91.44 53.131 95.922 53.221 ;
     RECT  86.115 50.549 86.397 53.257 ;
     RECT  38.7 52.781 41.598 53.275 ;
     RECT  42.444 52.445 75.192 53.275 ;
     RECT  77.436 52.475 78.297 53.275 ;
     RECT  38.7 53.275 75.192 53.329 ;
     RECT  86.115 53.257 86.67 53.329 ;
     RECT  77.4 53.275 78.297 53.467 ;
     RECT  38.7 53.329 75.582 53.563 ;
     RECT  77.364 53.467 78.297 53.563 ;
     RECT  88.815 53.221 95.922 53.563 ;
     RECT  86.115 53.329 86.742 53.591 ;
     RECT  38.7 53.563 76.122 53.693 ;
     RECT  88.815 53.563 96.354 53.741 ;
     RECT  39.276 53.693 76.122 53.969 ;
     RECT  97.488 52.699 97.506 54.029 ;
     RECT  88.815 53.741 96.066 54.437 ;
     RECT  90.648 54.437 96.066 54.679 ;
     RECT  96.912 54.571 96.93 54.679 ;
     RECT  39.348 53.969 76.122 54.869 ;
     RECT  90.648 54.679 96.93 55.021 ;
     RECT  77.22 53.563 78.297 55.183 ;
     RECT  88.815 54.437 89.838 55.183 ;
     RECT  90.648 55.021 97.002 55.183 ;
     RECT  37.515 52.781 37.797 55.291 ;
     RECT  38.736 54.985 39.294 55.291 ;
     RECT  88.815 55.183 97.002 55.325 ;
     RECT  86.115 53.591 86.397 55.381 ;
     RECT  37.515 55.291 39.294 55.409 ;
     RECT  38.736 55.409 38.97 55.445 ;
     RECT  40.068 54.869 76.122 55.489 ;
     RECT  86.115 55.381 86.706 55.517 ;
     RECT  83.415 50.009 84.114 55.553 ;
     RECT  88.815 55.325 96.318 55.859 ;
     RECT  90.504 55.859 96.318 56.021 ;
     RECT  40.068 55.489 76.158 56.029 ;
     RECT  86.115 55.517 86.67 56.057 ;
     RECT  90.504 56.021 95.166 56.399 ;
     RECT  88.815 55.859 89.766 56.489 ;
     RECT  88.815 56.489 89.37 56.525 ;
     RECT  96.048 56.021 96.318 56.587 ;
     RECT  90.504 56.399 95.022 56.669 ;
     RECT  90.504 56.669 91.797 56.759 ;
     RECT  92.664 56.669 95.022 56.759 ;
     RECT  96.048 56.587 96.354 56.869 ;
     RECT  95.76 56.869 96.354 56.909 ;
     RECT  92.808 56.759 95.022 56.939 ;
     RECT  92.916 56.939 95.022 57.029 ;
     RECT  96.048 56.909 96.354 57.137 ;
     RECT  93.492 57.029 95.022 57.299 ;
     RECT  97.488 55.867 97.506 57.407 ;
     RECT  77.22 55.183 78.93 57.875 ;
     RECT  96.048 57.137 96.066 58.693 ;
     RECT  95.976 58.693 96.066 58.721 ;
     RECT  40.068 56.029 76.23 60.504 ;
     RECT  95.976 58.721 95.994 60.575 ;
     RECT  70.704 60.504 70.794 60.719 ;
     RECT  74.664 60.504 76.23 60.719 ;
     RECT  70.704 60.719 70.722 60.764 ;
     RECT  93.528 57.299 95.022 61.079 ;
     RECT  40.068 60.504 42.75 61.115 ;
     RECT  93.528 61.079 94.497 61.115 ;
     RECT  41.904 61.115 42.75 61.187 ;
     RECT  93.6 61.115 94.497 61.187 ;
     RECT  41.904 61.187 41.958 61.223 ;
     RECT  75.204 60.719 76.23 61.259 ;
     RECT  40.068 61.115 40.842 61.385 ;
     RECT  75.204 61.259 76.158 61.385 ;
     RECT  76.14 61.385 76.158 61.421 ;
     RECT  40.068 61.385 40.77 61.457 ;
     RECT  77.22 57.875 77.238 61.457 ;
     RECT  40.068 61.457 40.734 61.619 ;
     RECT  41.904 61.223 41.922 61.655 ;
     RECT  93.78 61.187 94.497 61.655 ;
     RECT  42.696 61.187 42.75 61.844 ;
     RECT  49.644 61.816 49.662 62.509 ;
     RECT  90.9 56.759 91.797 62.537 ;
     RECT  42.732 61.844 42.75 62.573 ;
     RECT  49.536 62.509 49.662 62.581 ;
     RECT  50.4 62.545 50.418 62.581 ;
     RECT  78.015 57.875 78.93 62.609 ;
     RECT  49.536 62.581 50.418 62.623 ;
     RECT  75.204 61.385 75.33 62.623 ;
     RECT  49.536 62.623 51.105 62.699 ;
     RECT  75.204 62.623 75.405 62.735 ;
     RECT  42.915 62.623 43.005 62.893 ;
     RECT  45.615 62.623 45.705 62.893 ;
     RECT  48.315 62.623 48.405 62.893 ;
     RECT  51.015 62.699 51.105 62.893 ;
     RECT  53.715 62.623 53.805 62.893 ;
     RECT  56.415 62.623 56.505 62.893 ;
     RECT  59.115 62.623 59.205 62.893 ;
     RECT  61.815 62.623 61.905 62.893 ;
     RECT  64.515 62.623 64.605 62.893 ;
     RECT  67.215 62.623 67.305 62.893 ;
     RECT  69.915 62.623 70.005 62.893 ;
     RECT  72.615 62.623 72.705 62.893 ;
     RECT  75.24 62.735 75.405 62.893 ;
     RECT  75.24 62.893 75.597 62.969 ;
     RECT  42.915 62.893 43.197 64.552 ;
     RECT  42.915 64.552 43.326 64.589 ;
     RECT  42.915 64.589 43.254 64.973 ;
     RECT  15.915 2.413 16.197 68.731 ;
     RECT  13.215 2.413 13.497 68.827 ;
     RECT  14.832 68.731 14.85 68.861 ;
     RECT  15.915 68.731 16.83 68.909 ;
     RECT  15.915 68.909 16.197 68.917 ;
     RECT  13.215 68.827 13.59 68.957 ;
     RECT  15.228 68.917 16.197 68.957 ;
     RECT  94.215 61.655 94.497 72.619 ;
     RECT  93.456 72.619 94.497 72.845 ;
     RECT  93.744 72.845 94.497 72.959 ;
     RECT  78.015 62.609 78.297 73.771 ;
     RECT  86.115 56.057 86.397 73.867 ;
     RECT  78.015 73.771 78.678 73.901 ;
     RECT  86.115 73.867 86.67 74.045 ;
     RECT  76.968 74.047 76.986 74.093 ;
     RECT  77.256 74.191 77.274 74.309 ;
     RECT  40.068 61.619 40.497 74.551 ;
     RECT  39.888 74.551 40.497 74.621 ;
     RECT  5.115 50.189 5.397 78.619 ;
     RECT  4.716 78.619 5.397 78.745 ;
     RECT  4.716 78.745 5.706 78.871 ;
     RECT  4.5 78.871 5.706 78.899 ;
     RECT  41.904 78.601 41.922 78.907 ;
     RECT  0.108 78.907 0.126 78.955 ;
     RECT  2.415 45.761 2.697 79.015 ;
     RECT  3.42 78.781 3.438 79.015 ;
     RECT  4.5 78.899 5.397 79.051 ;
     RECT  0.108 78.955 0.198 79.085 ;
     RECT  6.804 78.781 6.822 79.141 ;
     RECT  2.415 79.015 3.438 79.147 ;
     RECT  4.392 79.051 5.397 79.177 ;
     RECT  2.415 79.147 3.474 79.243 ;
     RECT  6.444 79.141 6.822 79.249 ;
     RECT  6.156 79.249 6.822 79.285 ;
     RECT  41.904 78.907 42.174 79.285 ;
     RECT  42.915 64.973 43.197 79.285 ;
     RECT  7.815 50.279 8.097 79.321 ;
     RECT  10.515 44.753 10.797 79.321 ;
     RECT  2.304 79.243 3.474 79.373 ;
     RECT  38.952 55.445 38.97 79.483 ;
     RECT  7.668 79.321 8.097 79.555 ;
     RECT  38.772 79.483 38.97 79.583 ;
     RECT  10.515 79.321 10.926 79.619 ;
     RECT  6.156 79.285 6.858 79.681 ;
     RECT  7.668 79.555 8.19 79.681 ;
     RECT  41.904 79.285 43.197 79.681 ;
     RECT  6.156 79.681 8.406 79.717 ;
     RECT  0.108 79.085 0.162 79.949 ;
     RECT  6.156 79.717 8.478 79.979 ;
     RECT  4.284 79.177 5.397 80.023 ;
     RECT  2.415 79.373 3.474 80.131 ;
     RECT  4.284 80.023 5.706 80.131 ;
     RECT  2.16 80.131 5.706 80.237 ;
     RECT  41.616 79.681 43.197 80.329 ;
     RECT  6.552 79.979 8.478 80.635 ;
     RECT  2.304 80.237 5.706 80.761 ;
     RECT  6.552 80.635 9.198 80.761 ;
     RECT  0.108 79.949 0.126 80.861 ;
     RECT  2.304 80.761 9.198 80.969 ;
     RECT  91.515 62.537 91.797 81.031 ;
     RECT  1.116 80.923 1.134 81.053 ;
     RECT  38.952 79.583 38.97 81.103 ;
     RECT  41.58 80.329 43.197 81.103 ;
     RECT  2.415 80.969 9.198 81.131 ;
     RECT  41.544 81.103 43.197 81.139 ;
     RECT  0.144 80.923 0.162 81.205 ;
     RECT  94.215 72.959 94.497 81.211 ;
     RECT  0.144 81.205 0.558 81.245 ;
     RECT  93.312 81.259 93.33 81.301 ;
     RECT  94.215 81.211 94.554 81.301 ;
     RECT  41.328 81.139 43.197 81.329 ;
     RECT  93.312 81.301 94.554 81.329 ;
     RECT  93.78 81.329 94.554 81.355 ;
     RECT  88.815 56.525 89.097 81.481 ;
     RECT  91.515 81.031 92.25 81.481 ;
     RECT  2.415 81.131 4.374 81.485 ;
     RECT  93.78 81.355 95.202 81.635 ;
     RECT  0.144 81.245 0.342 81.643 ;
     RECT  0.108 81.643 0.342 81.677 ;
     RECT  91.515 81.481 92.358 81.715 ;
     RECT  90.648 81.301 90.666 81.751 ;
     RECT  91.515 81.715 92.538 81.751 ;
     RECT  98.244 81.739 98.262 81.751 ;
     RECT  98.172 81.751 98.262 81.779 ;
     RECT  98.172 81.779 98.19 81.821 ;
     RECT  88.815 81.481 89.73 81.869 ;
     RECT  85.032 81.751 85.05 81.905 ;
     RECT  88.815 81.869 89.334 81.917 ;
     RECT  94.215 81.635 95.202 81.949 ;
     RECT  75.315 62.969 75.597 82.021 ;
     RECT  90.648 81.751 92.538 82.021 ;
     RECT  0.108 81.677 0.162 82.049 ;
     RECT  38.772 81.103 38.97 82.049 ;
     RECT  82.656 81.877 82.674 82.049 ;
     RECT  94.215 81.949 95.778 82.109 ;
     RECT  3.528 81.485 4.374 82.111 ;
     RECT  5.115 81.131 9.126 82.111 ;
     RECT  90.108 82.021 92.538 82.111 ;
     RECT  96.912 81.643 96.93 82.21 ;
     RECT  3.528 82.111 9.126 82.255 ;
     RECT  41.436 81.329 43.197 82.255 ;
     RECT  88.815 81.917 89.097 82.291 ;
     RECT  2.415 81.485 2.754 82.363 ;
     RECT  3.528 82.255 9.198 82.409 ;
     RECT  90.108 82.111 92.934 82.525 ;
     RECT  94.215 82.109 95.526 82.525 ;
     RECT  84.924 82.417 84.942 82.651 ;
     RECT  86.115 74.045 86.397 82.651 ;
     RECT  40.068 74.621 40.497 82.687 ;
     RECT  84.924 82.651 86.397 82.687 ;
     RECT  3.528 82.409 8.55 82.751 ;
     RECT  0.144 82.049 0.162 82.781 ;
     RECT  84.924 82.687 86.67 82.787 ;
     RECT  2.376 82.363 2.754 82.795 ;
     RECT  3.528 82.751 6.822 82.795 ;
     RECT  38.844 82.049 38.97 82.831 ;
     RECT  75.315 82.021 75.906 82.831 ;
     RECT  84.924 82.787 86.397 82.859 ;
     RECT  90.108 82.525 95.526 82.859 ;
     RECT  2.376 82.795 6.822 82.925 ;
     RECT  96.912 82.21 96.966 82.939 ;
     RECT  88.632 82.291 89.097 82.993 ;
     RECT  90.108 82.859 94.806 82.993 ;
     RECT  96.912 82.939 97.506 83.029 ;
     RECT  2.376 82.925 2.697 83.083 ;
     RECT  40.032 82.687 40.497 83.101 ;
     RECT  41.4 82.255 43.197 83.101 ;
     RECT  96.3 83.029 97.506 83.117 ;
     RECT  2.304 83.083 2.697 83.129 ;
     RECT  3.42 82.925 6.822 83.213 ;
     RECT  3.42 83.213 5.85 83.219 ;
     RECT  6.696 83.213 6.822 83.219 ;
     RECT  9.288 83.029 9.306 83.219 ;
     RECT  4.716 83.219 5.49 83.255 ;
     RECT  10.515 79.619 10.797 83.263 ;
     RECT  4.824 83.255 5.49 83.399 ;
     RECT  6.804 83.219 6.822 83.489 ;
     RECT  7.815 82.751 8.55 83.489 ;
     RECT  10.515 83.263 10.854 83.489 ;
     RECT  95.544 83.299 95.562 83.489 ;
     RECT  7.815 83.489 8.406 83.533 ;
     RECT  83.415 55.553 83.697 83.569 ;
     RECT  38.772 82.831 38.97 83.633 ;
     RECT  96.912 83.117 97.506 83.633 ;
     RECT  88.632 82.993 94.806 83.641 ;
     RECT  0.108 83.371 0.126 83.669 ;
     RECT  75.096 82.831 75.942 83.731 ;
     RECT  40.032 83.101 43.197 83.755 ;
     RECT  3.42 83.219 3.438 83.759 ;
     RECT  6.912 83.533 8.406 83.759 ;
     RECT  75.096 83.731 76.662 83.767 ;
     RECT  88.344 83.641 94.806 83.767 ;
     RECT  7.236 83.759 8.406 83.789 ;
     RECT  44.784 83.755 44.802 83.795 ;
     RECT  85.464 82.859 86.397 83.795 ;
     RECT  7.815 83.789 8.406 83.831 ;
     RECT  40.032 83.755 43.218 83.831 ;
     RECT  78.015 73.901 78.297 83.911 ;
     RECT  4.824 83.399 5.397 83.939 ;
     RECT  45.615 62.893 45.897 83.987 ;
     RECT  48.315 62.893 48.597 83.987 ;
     RECT  51.015 62.893 51.297 83.987 ;
     RECT  53.715 62.893 53.997 83.987 ;
     RECT  56.415 62.893 56.697 83.987 ;
     RECT  59.115 62.893 59.397 83.987 ;
     RECT  61.815 62.893 62.097 83.987 ;
     RECT  67.215 62.893 67.497 83.987 ;
     RECT  69.915 62.893 70.197 83.987 ;
     RECT  72.615 62.893 72.897 83.987 ;
     RECT  78.015 83.911 78.642 84.029 ;
     RECT  83.415 83.569 84.402 84.029 ;
     RECT  64.515 62.893 64.797 84.073 ;
     RECT  95.868 83.659 95.922 84.091 ;
     RECT  75.06 83.767 76.662 84.101 ;
     RECT  85.752 83.795 86.397 84.109 ;
     RECT  64.515 84.073 65.106 84.125 ;
     RECT  41.436 83.831 43.218 84.181 ;
     RECT  65.412 84.181 65.43 84.221 ;
     RECT  88.344 83.767 95.094 84.235 ;
     RECT  95.868 84.091 96.354 84.235 ;
     RECT  45.615 83.987 45.705 84.257 ;
     RECT  48.315 83.987 48.405 84.257 ;
     RECT  51.015 83.987 51.105 84.257 ;
     RECT  53.715 83.987 53.805 84.257 ;
     RECT  56.415 83.987 56.505 84.257 ;
     RECT  59.115 83.987 59.205 84.257 ;
     RECT  61.815 83.987 61.905 84.257 ;
     RECT  64.515 84.125 64.605 84.257 ;
     RECT  67.215 83.987 67.305 84.257 ;
     RECT  69.915 83.987 70.005 84.257 ;
     RECT  72.615 83.987 72.705 84.257 ;
     RECT  85.752 84.109 86.67 84.299 ;
     RECT  41.436 84.181 43.542 84.365 ;
     RECT  88.344 84.235 96.354 84.407 ;
     RECT  96.3 84.407 96.354 84.479 ;
     RECT  97.488 83.633 97.506 84.641 ;
     RECT  6.84 84.541 6.858 84.649 ;
     RECT  7.815 83.831 8.298 84.649 ;
     RECT  4.14 84.649 4.158 84.667 ;
     RECT  5.04 83.939 5.397 84.685 ;
     RECT  3.42 84.667 4.158 84.721 ;
     RECT  5.04 84.685 5.85 84.721 ;
     RECT  6.768 84.649 6.858 84.721 ;
     RECT  38.952 83.633 38.97 84.721 ;
     RECT  40.032 83.831 40.497 84.721 ;
     RECT  2.415 83.129 2.697 84.811 ;
     RECT  3.42 84.721 6.858 84.811 ;
     RECT  2.415 84.811 6.858 84.839 ;
     RECT  0.108 84.667 0.342 84.845 ;
     RECT  7.815 84.649 8.802 84.847 ;
     RECT  38.952 84.721 40.497 84.883 ;
     RECT  41.436 84.365 43.11 84.883 ;
     RECT  7.596 84.847 8.802 84.911 ;
     RECT  75.06 84.101 75.834 84.941 ;
     RECT  6.804 84.839 6.858 84.991 ;
     RECT  7.596 84.911 8.55 84.991 ;
     RECT  38.952 84.883 43.11 84.991 ;
     RECT  6.804 84.991 8.55 85.145 ;
     RECT  83.415 84.029 83.697 85.189 ;
     RECT  86.115 84.299 86.67 85.189 ;
     RECT  82.368 84.991 82.386 85.225 ;
     RECT  86.115 85.189 86.922 85.261 ;
     RECT  86.115 85.261 87.066 85.379 ;
     RECT  86.115 85.379 86.922 85.415 ;
     RECT  0.108 84.845 0.306 85.451 ;
     RECT  96.3 84.479 96.318 85.451 ;
     RECT  79.776 85.261 79.794 85.459 ;
     RECT  83.415 85.189 83.79 85.459 ;
     RECT  0.144 85.451 0.306 85.568 ;
     RECT  2.415 84.839 3.438 85.621 ;
     RECT  4.212 84.839 5.886 85.621 ;
     RECT  2.415 85.621 5.994 85.649 ;
     RECT  6.876 85.145 8.55 85.649 ;
     RECT  3.852 85.649 5.994 85.793 ;
     RECT  82.368 85.225 82.602 85.801 ;
     RECT  88.344 84.407 95.202 85.829 ;
     RECT  0.54 85.801 0.558 85.853 ;
     RECT  86.115 85.415 86.706 85.955 ;
     RECT  79.776 85.459 79.902 85.963 ;
     RECT  78.015 84.029 78.297 86.011 ;
     RECT  86.115 85.955 86.562 86.063 ;
     RECT  6.876 85.649 8.226 86.071 ;
     RECT  82.332 85.801 82.602 86.071 ;
     RECT  90.072 85.829 95.202 86.071 ;
     RECT  6.84 86.071 8.226 86.155 ;
     RECT  3.924 85.793 5.994 86.189 ;
     RECT  90.072 86.071 95.382 86.189 ;
     RECT  88.344 85.829 89.097 86.225 ;
     RECT  96.912 85.819 96.93 86.261 ;
     RECT  4.5 86.189 5.994 86.269 ;
     RECT  6.732 86.155 8.226 86.269 ;
     RECT  10.515 83.489 10.797 86.299 ;
     RECT  75.096 84.941 75.834 86.341 ;
     RECT  76.644 84.101 76.662 86.341 ;
     RECT  77.904 86.011 78.297 86.341 ;
     RECT  83.415 85.459 83.898 86.341 ;
     RECT  38.772 84.991 43.11 86.4 ;
     RECT  75.096 86.341 76.662 86.4 ;
     RECT  13.215 68.957 13.497 86.431 ;
     RECT  21.315 2.413 21.597 86.431 ;
     RECT  4.5 86.269 8.226 86.459 ;
     RECT  9.18 86.269 9.198 86.459 ;
     RECT  77.904 86.341 78.678 86.459 ;
     RECT  90.072 86.189 94.842 86.459 ;
     RECT  2.415 85.649 2.79 86.467 ;
     RECT  10.515 86.299 10.818 86.477 ;
     RECT  13.104 86.431 13.497 86.477 ;
     RECT  21.204 86.431 21.597 86.477 ;
     RECT  38.772 86.4 76.662 86.531 ;
     RECT  2.415 86.467 2.862 86.539 ;
     RECT  90.072 86.459 94.59 86.567 ;
     RECT  14.832 86.443 14.85 86.573 ;
     RECT  22.824 86.443 22.842 86.573 ;
     RECT  30.78 86.443 30.798 86.573 ;
     RECT  77.904 86.459 78.297 86.611 ;
     RECT  38.808 86.531 76.662 86.639 ;
     RECT  83.415 86.341 84.078 86.701 ;
     RECT  38.952 86.639 76.662 86.765 ;
     RECT  90.864 86.567 94.59 86.801 ;
     RECT  83.415 86.701 84.186 86.837 ;
     RECT  88.02 86.737 88.038 86.837 ;
     RECT  6.408 86.459 8.226 86.873 ;
     RECT  6.588 86.873 8.226 86.909 ;
     RECT  83.415 86.837 84.006 86.909 ;
     RECT  4.5 86.459 5.634 86.971 ;
     RECT  9.36 86.773 9.378 86.999 ;
     RECT  34.815 50.351 35.097 87.007 ;
     RECT  90.072 86.567 90.09 87.035 ;
     RECT  90.864 86.801 94.497 87.035 ;
     RECT  34.776 87.007 35.097 87.107 ;
     RECT  4.428 86.971 5.634 87.115 ;
     RECT  2.304 86.539 2.862 87.151 ;
     RECT  6.732 86.909 8.226 87.151 ;
     RECT  88.815 86.225 89.097 87.151 ;
     RECT  0.108 86.395 0.126 87.179 ;
     RECT  3.996 87.115 5.634 87.211 ;
     RECT  77.4 86.611 78.297 87.307 ;
     RECT  79.488 85.963 79.902 87.307 ;
     RECT  3.996 87.211 5.67 87.349 ;
     RECT  81.756 86.071 82.602 87.355 ;
     RECT  83.415 86.909 83.79 87.355 ;
     RECT  2.304 87.151 3.186 87.385 ;
     RECT  3.996 87.349 5.706 87.385 ;
     RECT  2.304 87.385 5.706 87.539 ;
     RECT  38.952 86.765 76.41 87.583 ;
     RECT  3.492 87.539 5.706 87.611 ;
     RECT  9.288 87.385 9.306 87.611 ;
     RECT  38.772 87.583 76.41 87.683 ;
     RECT  5.115 87.611 5.706 87.691 ;
     RECT  6.732 87.151 8.298 87.691 ;
     RECT  81.756 87.355 83.79 87.809 ;
     RECT  83.415 87.809 83.79 87.817 ;
     RECT  86.115 86.063 86.397 87.817 ;
     RECT  77.4 87.307 79.902 87.853 ;
     RECT  77.328 87.853 79.902 87.917 ;
     RECT  83.415 87.817 84.402 87.917 ;
     RECT  86.115 87.817 86.67 87.925 ;
     RECT  0.54 87.511 0.558 87.979 ;
     RECT  5.115 87.691 8.73 87.989 ;
     RECT  6.516 87.989 8.298 88.079 ;
     RECT  77.328 87.917 78.678 88.079 ;
     RECT  79.488 87.917 79.902 88.079 ;
     RECT  81.756 87.809 82.674 88.079 ;
     RECT  34.815 87.107 35.097 88.123 ;
     RECT  0.18 87.979 0.558 88.157 ;
     RECT  6.768 88.079 8.298 88.205 ;
     RECT  34.776 88.123 35.097 88.223 ;
     RECT  2.304 87.539 2.697 88.259 ;
     RECT  90.864 87.035 92.322 88.321 ;
     RECT  3.492 87.611 3.978 88.349 ;
     RECT  2.376 88.259 2.697 88.363 ;
     RECT  5.115 87.989 5.706 88.363 ;
     RECT  3.492 88.349 3.51 88.397 ;
     RECT  79.488 88.079 79.506 88.445 ;
     RECT  81.756 88.079 82.602 88.457 ;
     RECT  88.815 87.151 90.054 88.501 ;
     RECT  90.864 88.321 92.466 88.501 ;
     RECT  93.276 87.035 94.497 88.501 ;
     RECT  82.332 88.457 82.602 88.529 ;
     RECT  0.144 88.171 0.162 88.589 ;
     RECT  4.428 88.363 5.706 88.619 ;
     RECT  88.815 88.501 94.497 88.619 ;
     RECT  23.004 88.591 23.022 88.637 ;
     RECT  4.536 88.619 5.706 88.691 ;
     RECT  2.376 88.363 2.754 88.771 ;
     RECT  13.215 86.477 13.497 88.771 ;
     RECT  0.108 88.699 0.126 88.799 ;
     RECT  82.404 88.529 82.602 88.861 ;
     RECT  83.415 87.917 84.222 88.861 ;
     RECT  4.536 88.691 5.49 88.925 ;
     RECT  79.416 88.771 79.434 88.925 ;
     RECT  82.404 88.861 84.222 88.925 ;
     RECT  90.9 88.619 94.497 88.925 ;
     RECT  6.768 88.205 8.118 88.939 ;
     RECT  6.696 88.939 8.118 88.969 ;
     RECT  22.788 88.771 22.806 88.973 ;
     RECT  77.328 88.079 78.297 89.021 ;
     RECT  77.4 89.021 78.297 89.035 ;
     RECT  38.952 87.683 76.41 89.041 ;
     RECT  2.376 88.771 3.006 89.131 ;
     RECT  4.536 88.925 5.397 89.159 ;
     RECT  6.696 88.969 8.694 89.159 ;
     RECT  2.304 89.131 3.006 89.168 ;
     RECT  38.772 89.041 76.41 89.267 ;
     RECT  88.815 88.619 90.054 89.267 ;
     RECT  2.376 89.168 3.006 89.311 ;
     RECT  5.004 89.159 5.397 89.339 ;
     RECT  12.564 88.771 13.497 89.339 ;
     RECT  82.872 88.925 84.222 89.339 ;
     RECT  80.715 52.619 80.997 89.401 ;
     RECT  38.952 89.267 76.41 89.405 ;
     RECT  2.376 89.311 3.33 89.429 ;
     RECT  6.696 89.159 8.097 89.429 ;
     RECT  90.036 89.267 90.054 89.429 ;
     RECT  85.752 87.925 86.67 89.465 ;
     RECT  88.815 89.267 89.097 89.473 ;
     RECT  38.952 89.405 76.374 89.501 ;
     RECT  80.715 89.401 81.054 89.549 ;
     RECT  34.815 88.223 35.097 89.671 ;
     RECT  6.84 89.429 6.858 89.699 ;
     RECT  91.008 88.925 94.497 89.707 ;
     RECT  77.4 89.035 78.822 89.803 ;
     RECT  34.776 89.671 35.097 89.807 ;
     RECT  90.504 89.707 94.497 89.843 ;
     RECT  88.344 89.473 89.097 89.879 ;
     RECT  77.4 89.803 78.894 89.981 ;
     RECT  82.368 89.851 82.53 90.085 ;
     RECT  83.415 89.339 84.222 90.085 ;
     RECT  82.368 90.085 84.222 90.121 ;
     RECT  82.368 90.121 84.366 90.239 ;
     RECT  90.648 89.843 94.497 90.239 ;
     RECT  82.368 90.239 84.222 90.275 ;
     RECT  90.648 90.239 92.466 90.275 ;
     RECT  91.224 90.275 92.466 90.311 ;
     RECT  82.08 90.283 82.17 90.419 ;
     RECT  82.152 90.419 82.17 90.509 ;
     RECT  91.224 90.311 92.25 90.545 ;
     RECT  85.752 89.465 86.397 90.787 ;
     RECT  91.224 90.545 91.998 90.815 ;
     RECT  85.752 90.787 86.634 90.887 ;
     RECT  77.4 89.981 78.678 90.893 ;
     RECT  38.952 89.501 76.302 90.931 ;
     RECT  83.196 90.275 84.222 90.959 ;
     RECT  38.952 90.931 76.374 91.517 ;
     RECT  38.952 91.517 75.366 91.613 ;
     RECT  76.284 91.517 76.374 91.805 ;
     RECT  76.32 91.805 76.374 92.011 ;
     RECT  77.4 90.893 78.297 92.011 ;
     RECT  76.32 92.011 78.297 92.093 ;
     RECT  37.515 55.409 37.797 92.479 ;
     RECT  38.952 91.613 75.192 92.479 ;
     RECT  77.544 92.093 78.297 92.669 ;
     RECT  37.515 92.479 75.192 92.785 ;
     RECT  76.32 92.093 76.41 92.785 ;
     RECT  37.515 92.785 76.41 92.957 ;
     RECT  41.94 92.957 76.41 93.533 ;
     RECT  37.515 92.957 41.022 93.551 ;
     RECT  93.492 90.239 94.497 93.749 ;
     RECT  39.348 93.551 41.022 94.027 ;
     RECT  41.94 93.533 75.192 94.027 ;
     RECT  91.224 90.815 91.89 94.027 ;
     RECT  88.815 89.879 89.097 94.171 ;
     RECT  83.415 90.959 84.222 94.199 ;
     RECT  85.752 90.887 86.397 94.289 ;
     RECT  88.815 94.171 89.658 94.333 ;
     RECT  90.9 94.027 91.89 94.333 ;
     RECT  37.515 93.551 38.502 94.405 ;
     RECT  39.348 94.027 75.192 94.405 ;
     RECT  88.815 94.333 89.838 94.433 ;
     RECT  77.58 92.669 78.297 94.441 ;
     RECT  77.472 94.441 78.297 94.595 ;
     RECT  37.515 94.405 75.192 94.603 ;
     RECT  76.32 93.533 76.41 94.603 ;
     RECT  90.9 94.333 92.142 94.603 ;
     RECT  37.515 94.603 76.41 94.612 ;
     RECT  90.9 94.603 92.178 94.675 ;
     RECT  37.515 94.612 76.374 95.261 ;
     RECT  77.544 94.595 78.297 95.611 ;
     RECT  37.515 95.261 75.192 95.675 ;
     RECT  37.515 95.675 39.042 95.747 ;
     RECT  94.215 93.749 94.497 95.989 ;
     RECT  39.888 95.675 75.192 96.077 ;
     RECT  93.276 93.865 93.294 96.151 ;
     RECT  94.215 95.989 95.022 96.151 ;
     RECT  93.276 96.151 95.022 96.283 ;
     RECT  96.336 96.295 96.354 96.365 ;
     RECT  76.392 95.419 76.41 96.529 ;
     RECT  86.115 94.289 86.397 96.529 ;
     RECT  39.96 96.077 75.192 96.565 ;
     RECT  39.96 96.565 75.51 96.571 ;
     RECT  76.392 96.529 76.662 96.571 ;
     RECT  90.9 94.675 92.214 96.601 ;
     RECT  92.952 96.283 95.022 96.601 ;
     RECT  86.115 96.529 86.67 96.719 ;
     RECT  39.96 96.571 76.662 96.755 ;
     RECT  76.644 96.755 76.662 96.763 ;
     RECT  90.612 96.601 95.022 96.871 ;
     RECT  95.76 96.493 95.778 96.871 ;
     RECT  77.436 95.611 78.297 96.989 ;
     RECT  97.488 96.475 97.506 97.339 ;
     RECT  90.612 96.871 95.778 97.483 ;
     RECT  88.815 94.433 89.766 97.501 ;
     RECT  90.612 97.483 95.922 97.501 ;
     RECT  88.815 97.501 95.922 97.529 ;
     RECT  86.115 96.719 86.397 97.609 ;
     RECT  88.815 97.529 95.454 98.147 ;
     RECT  39.96 96.755 75.834 98.185 ;
     RECT  76.644 96.763 76.698 98.185 ;
     RECT  96.912 97.339 97.506 98.203 ;
     RECT  88.815 98.147 90.018 98.339 ;
     RECT  90.792 98.147 95.454 98.347 ;
     RECT  88.815 98.339 89.838 98.375 ;
     RECT  86.115 97.609 86.67 98.519 ;
     RECT  96.912 98.203 97.542 99.101 ;
     RECT  90.792 98.347 95.922 99.571 ;
     RECT  90.612 99.571 95.922 99.643 ;
     RECT  22.752 99.595 22.77 99.688 ;
     RECT  22.5 99.688 22.77 99.689 ;
     RECT  88.815 98.375 89.766 99.691 ;
     RECT  90.612 99.643 96.318 99.691 ;
     RECT  22.5 99.689 22.518 99.725 ;
     RECT  88.815 99.691 96.318 99.761 ;
     RECT  97.488 99.101 97.542 99.841 ;
     RECT  88.815 99.761 95.922 99.959 ;
     RECT  96.912 99.841 97.542 100.031 ;
     RECT  96.912 100.031 97.506 100.109 ;
     RECT  88.815 99.959 89.766 100.337 ;
     RECT  90.504 99.959 95.922 100.769 ;
     RECT  90.504 100.769 95.814 100.877 ;
     RECT  96.912 100.109 96.93 100.877 ;
     RECT  39.96 98.185 76.698 100.987 ;
     RECT  90.792 100.877 95.814 101.039 ;
     RECT  90.792 101.039 94.497 101.219 ;
     RECT  39.708 100.987 76.698 101.371 ;
     RECT  39.24 101.371 76.698 101.417 ;
     RECT  90.792 101.219 92.538 101.759 ;
     RECT  40.104 101.417 76.698 101.849 ;
     RECT  40.104 101.849 76.662 103.704 ;
     RECT  95.364 101.039 95.814 103.775 ;
     RECT  95.364 103.775 95.598 103.805 ;
     RECT  91.044 101.759 92.538 103.883 ;
     RECT  40.104 103.704 42.75 104.351 ;
     RECT  95.364 103.805 95.382 104.351 ;
     RECT  93.564 101.219 94.497 104.387 ;
     RECT  42.444 104.351 42.75 104.423 ;
     RECT  91.515 103.883 92.538 104.459 ;
     RECT  40.104 104.351 41.454 104.549 ;
     RECT  91.515 104.459 92.286 104.549 ;
     RECT  75.204 103.704 76.662 104.657 ;
     RECT  76.176 104.657 76.662 104.693 ;
     RECT  40.104 104.549 41.346 104.927 ;
     RECT  93.744 104.387 94.497 104.927 ;
     RECT  91.515 104.549 92.106 105.161 ;
     RECT  50.292 105.133 50.634 105.169 ;
     RECT  76.176 104.693 76.194 105.737 ;
     RECT  42.624 104.423 42.75 105.773 ;
     RECT  50.292 105.169 51.174 105.781 ;
     RECT  75.204 104.657 75.294 105.809 ;
     RECT  42.732 105.773 42.75 105.823 ;
     RECT  75.24 105.809 75.294 105.823 ;
     RECT  64.515 105.823 64.605 105.871 ;
     RECT  50.184 105.781 51.174 105.899 ;
     RECT  66.132 105.451 66.15 105.899 ;
     RECT  75.24 105.823 75.405 105.935 ;
     RECT  64.515 105.871 65.07 105.965 ;
     RECT  46.764 105.745 46.782 105.971 ;
     RECT  42.732 105.823 43.005 106.093 ;
     RECT  45.615 105.823 45.705 106.093 ;
     RECT  48.315 105.823 48.405 106.093 ;
     RECT  51.015 105.899 51.174 106.093 ;
     RECT  53.715 105.823 53.805 106.093 ;
     RECT  56.415 105.823 56.505 106.093 ;
     RECT  59.115 105.823 59.205 106.093 ;
     RECT  61.815 105.823 61.905 106.093 ;
     RECT  67.215 105.823 67.305 106.093 ;
     RECT  69.915 105.823 70.005 106.093 ;
     RECT  72.615 105.823 72.705 106.093 ;
     RECT  75.276 105.935 75.405 106.093 ;
     RECT  75.276 106.093 75.597 106.169 ;
     RECT  86.115 98.519 86.397 106.951 ;
     RECT  86.115 106.951 86.742 107.021 ;
     RECT  85.176 106.987 85.194 107.024 ;
     RECT  42.732 106.093 43.197 107.401 ;
     RECT  85.212 107.365 85.23 107.405 ;
     RECT  42.732 107.401 43.578 107.467 ;
     RECT  42.228 107.467 43.578 107.519 ;
     RECT  41.904 107.599 41.922 107.645 ;
     RECT  42.732 107.519 43.578 108.239 ;
     RECT  42.732 108.239 43.542 108.515 ;
     RECT  40.104 104.927 40.662 109.319 ;
     RECT  64.515 105.965 64.797 110.011 ;
     RECT  64.515 110.011 65.106 110.461 ;
     RECT  64.515 110.461 65.43 110.525 ;
     RECT  37.515 95.747 38.502 112.801 ;
     RECT  37.515 112.801 38.574 113.035 ;
     RECT  37.515 113.035 38.646 113.071 ;
     RECT  37.515 113.071 39.114 113.611 ;
     RECT  37.515 113.611 39.186 113.971 ;
     RECT  40.176 109.319 40.662 113.971 ;
     RECT  37.044 113.971 40.662 114.091 ;
     RECT  41.76 113.995 41.778 114.379 ;
     RECT  36.648 114.091 40.662 114.511 ;
     RECT  41.436 114.379 41.778 114.539 ;
     RECT  41.436 114.539 41.454 114.575 ;
     RECT  22.5 115.147 22.518 115.321 ;
     RECT  34.815 89.807 35.097 115.321 ;
     RECT  36 114.511 40.662 115.321 ;
     RECT  22.5 115.321 22.806 115.339 ;
     RECT  22.428 115.339 22.806 115.373 ;
     RECT  22.428 115.373 22.446 115.619 ;
     RECT  42.732 108.515 43.197 116.743 ;
     RECT  42.084 116.743 43.197 116.815 ;
     RECT  34.815 115.321 40.662 116.875 ;
     RECT  41.94 116.815 43.197 116.875 ;
     RECT  34.815 116.875 43.197 119.669 ;
     RECT  42.84 119.669 43.197 119.707 ;
     RECT  42.84 119.707 43.218 119.939 ;
     RECT  73.872 120.427 73.89 120.479 ;
     RECT  34.815 119.669 42.102 120.631 ;
     RECT  42.84 119.939 43.197 120.631 ;
     RECT  75.315 106.169 75.597 120.631 ;
     RECT  34.815 120.631 43.197 120.749 ;
     RECT  74.916 120.631 75.597 120.793 ;
     RECT  2.415 89.429 2.697 120.901 ;
     RECT  5.115 89.339 5.397 120.901 ;
     RECT  2.415 120.901 2.862 121.019 ;
     RECT  34.815 120.749 42.102 121.063 ;
     RECT  5.115 120.901 5.418 121.135 ;
     RECT  4.464 121.135 5.418 121.181 ;
     RECT  4.536 121.181 5.418 121.261 ;
     RECT  34.776 121.063 42.102 121.397 ;
     RECT  3.636 121.261 3.654 121.421 ;
     RECT  74.736 120.793 75.597 121.441 ;
     RECT  2.415 121.019 2.697 121.531 ;
     RECT  74.484 121.441 75.597 121.531 ;
     RECT  4.536 121.261 5.742 121.711 ;
     RECT  6.912 121.441 6.93 121.711 ;
     RECT  7.815 89.429 8.097 121.711 ;
     RECT  2.304 121.531 2.697 121.801 ;
     RECT  4.536 121.711 6.93 121.801 ;
     RECT  7.815 121.711 8.55 121.801 ;
     RECT  74.34 121.531 75.597 121.837 ;
     RECT  4.536 121.801 8.55 121.963 ;
     RECT  4.464 121.963 8.55 121.972 ;
     RECT  4.464 121.972 8.586 121.973 ;
     RECT  2.304 121.801 3.474 122.009 ;
     RECT  74.124 121.837 75.597 122.215 ;
     RECT  34.815 121.397 42.102 122.251 ;
     RECT  42.915 120.749 43.197 122.251 ;
     RECT  72.615 106.093 72.897 122.485 ;
     RECT  73.944 122.215 75.597 122.485 ;
     RECT  34.815 122.251 43.197 122.513 ;
     RECT  7.815 121.973 8.586 122.521 ;
     RECT  0.108 121.243 0.126 122.539 ;
     RECT  72.615 122.485 75.597 122.611 ;
     RECT  2.415 122.009 3.474 122.635 ;
     RECT  4.464 121.973 6.93 122.635 ;
     RECT  7.815 122.521 8.622 122.639 ;
     RECT  0.108 122.539 0.162 122.669 ;
     RECT  2.415 122.635 6.93 122.791 ;
     RECT  72.615 122.611 75.69 122.791 ;
     RECT  2.415 122.791 7.074 122.819 ;
     RECT  4.212 122.819 7.074 122.989 ;
     RECT  7.815 122.639 8.586 122.989 ;
     RECT  72.615 122.791 75.834 122.989 ;
     RECT  0.108 122.669 0.126 123.089 ;
     RECT  2.415 122.819 3.474 123.115 ;
     RECT  2.304 123.115 3.474 123.179 ;
     RECT  2.415 123.179 3.474 123.691 ;
     RECT  4.212 122.989 8.586 123.691 ;
     RECT  72.615 122.989 76.302 123.799 ;
     RECT  2.415 123.691 8.586 123.871 ;
     RECT  9.396 122.611 9.414 123.871 ;
     RECT  34.815 122.513 42.102 123.871 ;
     RECT  34.776 123.871 42.102 124.097 ;
     RECT  0.144 123.403 0.162 124.157 ;
     RECT  72.615 123.799 76.374 124.267 ;
     RECT  72.615 124.267 76.41 124.529 ;
     RECT  32.115 2.413 32.397 124.807 ;
     RECT  78.015 96.989 78.297 125.041 ;
     RECT  2.415 123.871 9.414 125.177 ;
     RECT  42.915 122.513 43.197 125.221 ;
     RECT  34.815 124.097 42.102 125.383 ;
     RECT  42.915 125.221 43.326 125.383 ;
     RECT  6.12 125.177 9.414 125.519 ;
     RECT  34.815 125.383 43.326 125.681 ;
     RECT  72.615 124.529 76.374 125.761 ;
     RECT  77.328 125.041 78.297 125.761 ;
     RECT  72.615 125.761 78.297 125.915 ;
     RECT  2.415 125.177 5.397 125.959 ;
     RECT  6.12 125.519 6.354 125.959 ;
     RECT  2.415 125.959 6.354 126.419 ;
     RECT  42.624 125.681 43.326 126.463 ;
     RECT  34.815 125.681 41.742 126.571 ;
     RECT  42.624 126.463 43.362 126.571 ;
     RECT  34.776 126.571 43.362 126.797 ;
     RECT  72.615 125.915 76.518 126.805 ;
     RECT  77.328 125.915 78.297 126.805 ;
     RECT  72.144 126.805 78.297 126.959 ;
     RECT  34.815 126.797 43.362 127.111 ;
     RECT  2.415 126.419 6.282 127.139 ;
     RECT  45.615 106.093 45.897 127.187 ;
     RECT  48.315 106.093 48.597 127.187 ;
     RECT  51.015 106.093 51.297 127.187 ;
     RECT  53.715 106.093 53.997 127.187 ;
     RECT  56.415 106.093 56.697 127.187 ;
     RECT  59.115 106.093 59.397 127.187 ;
     RECT  61.815 106.093 62.097 127.187 ;
     RECT  64.515 110.525 64.797 127.187 ;
     RECT  67.215 106.093 67.497 127.187 ;
     RECT  69.915 106.093 70.197 127.187 ;
     RECT  34.815 127.111 43.506 127.265 ;
     RECT  72.615 126.959 78.297 127.265 ;
     RECT  73.872 127.265 78.297 127.409 ;
     RECT  45.615 127.187 45.705 127.457 ;
     RECT  48.315 127.187 48.405 127.457 ;
     RECT  51.015 127.187 51.105 127.457 ;
     RECT  53.715 127.187 53.805 127.457 ;
     RECT  56.415 127.187 56.505 127.457 ;
     RECT  59.115 127.187 59.205 127.457 ;
     RECT  61.815 127.187 61.905 127.457 ;
     RECT  64.515 127.187 64.605 127.457 ;
     RECT  67.215 127.187 67.305 127.457 ;
     RECT  69.915 127.187 70.005 127.457 ;
     RECT  72.615 127.265 72.705 127.457 ;
     RECT  34.815 127.265 43.326 127.679 ;
     RECT  7.308 125.519 9.414 127.949 ;
     RECT  73.872 127.409 76.41 128.147 ;
     RECT  2.415 127.139 5.994 128.417 ;
     RECT  34.815 127.679 42.894 128.489 ;
     RECT  73.872 128.147 73.89 128.861 ;
     RECT  77.328 127.409 78.297 128.885 ;
     RECT  8.82 127.949 9.414 129.029 ;
     RECT  35.928 128.489 42.894 129.451 ;
     RECT  34.815 128.489 35.097 129.541 ;
     RECT  35.928 129.451 43.11 129.541 ;
     RECT  34.815 129.541 43.11 129.6 ;
     RECT  74.664 128.147 76.41 129.6 ;
     RECT  2.415 128.417 5.397 129.695 ;
     RECT  77.436 128.885 78.297 129.811 ;
     RECT  77.4 129.811 78.297 130.045 ;
     RECT  77.4 130.045 78.57 130.469 ;
     RECT  2.415 129.695 4.158 130.649 ;
     RECT  34.815 129.6 76.41 130.891 ;
     RECT  34.815 130.891 76.482 130.919 ;
     RECT  36 130.919 76.482 131.045 ;
     RECT  34.815 130.919 35.097 131.161 ;
     RECT  77.4 130.469 78.534 131.431 ;
     RECT  36.216 131.045 76.482 131.453 ;
     RECT  7.308 127.949 8.097 131.459 ;
     RECT  36.252 131.453 76.482 131.549 ;
     RECT  2.415 130.649 2.898 131.729 ;
     RECT  77.4 131.431 78.75 131.741 ;
     RECT  77.436 131.741 78.75 131.819 ;
     RECT  8.82 129.029 8.838 131.963 ;
     RECT  34.776 131.161 35.097 132.089 ;
     RECT  4.14 130.649 4.158 132.269 ;
     RECT  36.432 131.549 76.482 132.317 ;
     RECT  36.432 132.317 76.41 132.469 ;
     RECT  36 132.469 76.41 132.509 ;
     RECT  77.508 131.819 78.75 132.511 ;
     RECT  4.896 129.695 5.397 132.809 ;
     RECT  77.508 132.511 79.254 132.871 ;
     RECT  36.504 132.509 76.41 132.893 ;
     RECT  32.115 124.807 32.778 132.971 ;
     RECT  77.436 132.871 79.254 132.971 ;
     RECT  43.2 132.893 76.41 133.051 ;
     RECT  43.2 133.051 76.446 133.169 ;
     RECT  77.436 132.971 79.002 133.177 ;
     RECT  36.504 132.893 42.318 133.181 ;
     RECT  36.504 133.181 41.634 133.277 ;
     RECT  77.364 133.177 79.002 133.349 ;
     RECT  36.504 133.277 41.454 133.439 ;
     RECT  36.504 133.439 40.914 133.591 ;
     RECT  36.432 133.591 40.914 133.675 ;
     RECT  36.288 133.675 40.914 133.681 ;
     RECT  77.436 133.349 79.002 133.825 ;
     RECT  36.036 133.681 40.914 133.979 ;
     RECT  77.436 133.825 79.506 133.979 ;
     RECT  36.036 133.979 40.842 134.051 ;
     RECT  77.436 133.979 78.822 134.249 ;
     RECT  36.216 134.051 40.842 134.357 ;
     RECT  36.216 134.357 36.234 134.429 ;
     RECT  43.2 133.169 76.41 134.671 ;
     RECT  43.2 134.671 76.446 135.005 ;
     RECT  37.515 134.357 40.842 135.175 ;
     RECT  77.472 134.249 78.822 135.175 ;
     RECT  43.2 135.005 76.41 135.197 ;
     RECT  77.472 135.175 78.93 135.211 ;
     RECT  77.472 135.211 79.002 135.329 ;
     RECT  77.58 135.329 79.002 135.401 ;
     RECT  37.515 135.175 40.95 135.481 ;
     RECT  77.58 135.401 78.93 135.599 ;
     RECT  43.2 135.197 75.192 136.147 ;
     RECT  76.284 135.197 76.41 136.147 ;
     RECT  77.58 135.599 78.297 136.175 ;
     RECT  77.616 136.175 78.297 136.409 ;
     RECT  37.515 135.481 41.022 136.481 ;
     RECT  77.724 136.409 78.297 137.179 ;
     RECT  77.58 137.179 78.297 137.255 ;
     RECT  43.2 136.147 76.41 137.467 ;
     RECT  43.02 137.467 76.41 137.501 ;
     RECT  37.515 136.481 40.95 137.605 ;
     RECT  37.515 137.605 41.022 137.641 ;
     RECT  42.156 137.101 42.174 137.641 ;
     RECT  37.515 137.641 42.174 137.831 ;
     RECT  41.616 137.831 42.174 138.181 ;
     RECT  43.02 137.501 75.192 138.181 ;
     RECT  77.616 137.255 78.297 138.427 ;
     RECT  37.515 137.831 40.734 138.569 ;
     RECT  77.436 138.427 78.297 138.569 ;
     RECT  94.215 104.927 94.497 138.847 ;
     RECT  76.392 137.501 76.41 138.875 ;
     RECT  94.215 138.847 94.734 138.991 ;
     RECT  41.616 138.181 75.192 139.003 ;
     RECT  91.515 105.161 91.797 139.081 ;
     RECT  41.616 139.003 75.294 139.099 ;
     RECT  94.215 138.991 95.886 139.099 ;
     RECT  94.215 139.099 96.318 139.109 ;
     RECT  95.544 139.109 96.318 139.181 ;
     RECT  41.58 139.099 75.294 139.195 ;
     RECT  38.592 138.569 40.734 139.225 ;
     RECT  41.544 139.195 75.294 139.225 ;
     RECT  88.815 100.337 89.097 139.243 ;
     RECT  97.524 139.225 97.542 139.243 ;
     RECT  91.476 139.081 92.934 139.261 ;
     RECT  94.215 139.109 94.806 139.261 ;
     RECT  97.488 139.243 97.542 139.261 ;
     RECT  77.544 138.569 78.297 139.291 ;
     RECT  77.508 139.291 78.297 139.351 ;
     RECT  90.468 139.225 90.666 139.379 ;
     RECT  88.815 139.243 89.478 139.415 ;
     RECT  77.22 139.351 78.297 139.423 ;
     RECT  90.684 139.387 90.702 139.559 ;
     RECT  97.488 139.261 97.614 139.565 ;
     RECT  38.592 139.225 75.294 139.579 ;
     RECT  95.544 139.181 95.922 139.709 ;
     RECT  91.476 139.261 94.806 139.963 ;
     RECT  97.488 139.565 97.506 139.997 ;
     RECT  91.296 139.963 94.806 140.071 ;
     RECT  95.544 139.709 95.886 140.071 ;
     RECT  38.592 139.579 75.834 140.189 ;
     RECT  91.296 140.071 95.886 140.195 ;
     RECT  91.296 140.195 92.178 140.341 ;
     RECT  96.912 140.533 96.93 140.573 ;
     RECT  90.252 140.341 90.27 140.575 ;
     RECT  96.876 140.773 96.894 140.861 ;
     RECT  91.116 140.341 92.178 140.971 ;
     RECT  92.916 140.195 95.886 140.971 ;
     RECT  38.592 140.189 75.654 141.043 ;
     RECT  86.115 107.021 86.397 141.043 ;
     RECT  90.108 140.575 90.27 141.151 ;
     RECT  91.044 140.971 95.886 141.151 ;
     RECT  86.115 141.043 86.706 141.269 ;
     RECT  86.115 141.269 86.67 141.341 ;
     RECT  90.108 141.151 95.886 141.403 ;
     RECT  38.592 141.043 75.798 141.583 ;
     RECT  76.644 139.423 78.297 141.583 ;
     RECT  90.108 141.403 95.922 141.925 ;
     RECT  90 141.925 95.922 141.979 ;
     RECT  86.115 141.341 86.397 142.231 ;
     RECT  90 141.979 96.354 142.259 ;
     RECT  90 142.259 90.018 142.385 ;
     RECT  86.115 142.231 86.67 142.457 ;
     RECT  97.488 141.421 97.506 142.529 ;
     RECT  90.936 142.259 96.354 142.727 ;
     RECT  90.936 142.727 95.886 142.799 ;
     RECT  37.515 138.569 37.797 143.083 ;
     RECT  38.592 141.583 78.297 143.083 ;
     RECT  37.515 143.083 78.297 143.429 ;
     RECT  93.528 142.799 95.886 146.471 ;
     RECT  38.592 143.429 77.238 146.904 ;
     RECT  93.528 146.471 95.814 147.101 ;
     RECT  90.936 142.799 92.358 147.119 ;
     RECT  70.704 146.904 70.722 147.197 ;
     RECT  38.592 146.904 42.75 147.293 ;
     RECT  75.168 146.904 77.238 147.479 ;
     RECT  75.168 147.479 75.582 147.515 ;
     RECT  93.528 147.101 95.67 147.659 ;
     RECT  93.528 147.659 95.13 147.749 ;
     RECT  38.592 147.293 41.886 147.821 ;
     RECT  38.592 147.821 41.454 147.857 ;
     RECT  91.008 147.119 92.358 147.857 ;
     RECT  38.592 147.857 40.734 147.893 ;
     RECT  76.644 147.479 77.238 147.893 ;
     RECT  42.66 147.293 42.75 147.929 ;
     RECT  77.22 147.893 77.238 148.019 ;
     RECT  50.4 147.901 50.418 148.441 ;
     RECT  42.696 147.929 42.75 148.469 ;
     RECT  94.215 147.749 95.13 148.469 ;
     RECT  42.732 148.469 42.75 148.514 ;
     RECT  48.888 148.441 48.906 148.945 ;
     RECT  91.044 147.857 92.358 148.973 ;
     RECT  51.264 148.486 51.282 148.981 ;
     RECT  91.044 148.973 91.797 149.009 ;
     RECT  48.78 148.945 48.906 149.023 ;
     RECT  50.292 148.441 50.418 149.023 ;
     RECT  51.156 148.981 51.282 149.023 ;
     RECT  75.168 147.515 75.258 149.023 ;
     RECT  48.315 149.023 48.906 149.099 ;
     RECT  50.292 149.023 51.282 149.099 ;
     RECT  75.168 149.023 75.405 149.135 ;
     RECT  42.915 149.023 43.005 149.293 ;
     RECT  45.615 149.023 45.705 149.293 ;
     RECT  51.015 149.099 51.282 149.293 ;
     RECT  53.715 149.023 53.805 149.293 ;
     RECT  56.415 149.023 56.505 149.293 ;
     RECT  59.115 149.023 59.205 149.293 ;
     RECT  61.815 149.023 61.905 149.293 ;
     RECT  64.515 149.023 64.605 149.293 ;
     RECT  67.215 149.023 67.305 149.293 ;
     RECT  69.915 149.023 70.005 149.293 ;
     RECT  72.615 149.023 72.705 149.293 ;
     RECT  75.24 149.135 75.405 149.293 ;
     RECT  75.24 149.293 75.597 149.675 ;
     RECT  38.592 147.893 40.497 163.687 ;
     RECT  38.592 163.687 40.59 163.949 ;
     RECT  38.592 163.949 40.554 164.219 ;
     RECT  37.515 143.429 37.797 164.335 ;
     RECT  38.592 164.219 40.497 164.335 ;
     RECT  37.515 164.335 40.497 166.411 ;
     RECT  37.116 166.411 40.497 166.451 ;
     RECT  37.296 166.451 40.497 166.649 ;
     RECT  37.515 166.649 40.497 167.873 ;
     RECT  2.415 131.729 2.697 168.227 ;
     RECT  5.115 132.809 5.397 168.227 ;
     RECT  7.815 131.459 8.097 168.227 ;
     RECT  10.515 86.477 10.797 168.227 ;
     RECT  13.215 89.339 13.497 168.227 ;
     RECT  15.915 68.957 16.197 168.227 ;
     RECT  18.615 2.413 18.897 168.227 ;
     RECT  21.315 86.477 21.597 168.227 ;
     RECT  24.015 2.413 24.297 168.227 ;
     RECT  26.715 2.413 26.997 168.227 ;
     RECT  29.415 2.413 29.697 168.227 ;
     RECT  32.115 132.971 32.397 168.227 ;
     RECT  34.815 132.089 35.097 168.227 ;
     RECT  40.215 167.873 40.497 168.227 ;
     RECT  42.915 149.293 43.197 168.227 ;
     RECT  45.615 149.293 45.897 168.227 ;
     RECT  48.315 149.099 48.597 168.227 ;
     RECT  51.015 149.293 51.297 168.227 ;
     RECT  53.715 149.293 53.997 168.227 ;
     RECT  56.415 149.293 56.697 168.227 ;
     RECT  59.115 149.293 59.397 168.227 ;
     RECT  61.815 149.293 62.097 168.227 ;
     RECT  64.515 149.293 64.797 168.227 ;
     RECT  67.215 149.293 67.497 168.227 ;
     RECT  69.915 149.293 70.197 168.227 ;
     RECT  72.615 149.293 72.897 168.227 ;
     RECT  75.315 149.675 75.597 168.227 ;
     RECT  78.015 143.429 78.297 168.227 ;
     RECT  80.715 89.549 80.997 168.227 ;
     RECT  83.415 94.199 83.697 168.227 ;
     RECT  86.115 142.457 86.397 168.227 ;
     RECT  88.815 139.415 89.097 168.227 ;
     RECT  91.515 149.009 91.797 168.227 ;
     RECT  94.215 148.469 94.497 168.227 ;
     RECT  37.515 167.873 39.222 168.269 ;
     RECT  37.515 168.269 39.15 168.305 ;
     RECT  2.415 168.227 2.505 168.497 ;
     RECT  5.115 168.227 5.205 168.497 ;
     RECT  7.815 168.227 7.905 168.497 ;
     RECT  10.515 168.227 10.605 168.497 ;
     RECT  13.215 168.227 13.305 168.497 ;
     RECT  15.915 168.227 16.005 168.497 ;
     RECT  18.615 168.227 18.705 168.497 ;
     RECT  21.315 168.227 21.405 168.497 ;
     RECT  24.015 168.227 24.105 168.497 ;
     RECT  26.715 168.227 26.805 168.497 ;
     RECT  29.415 168.227 29.505 168.497 ;
     RECT  32.115 168.227 32.205 168.497 ;
     RECT  34.815 168.227 34.905 168.497 ;
     RECT  37.515 168.305 39.006 168.497 ;
     RECT  40.215 168.227 40.305 168.497 ;
     RECT  42.915 168.227 43.005 168.497 ;
     RECT  45.615 168.227 45.705 168.497 ;
     RECT  48.315 168.227 48.405 168.497 ;
     RECT  51.015 168.227 51.105 168.497 ;
     RECT  53.715 168.227 53.805 168.497 ;
     RECT  56.415 168.227 56.505 168.497 ;
     RECT  59.115 168.227 59.205 168.497 ;
     RECT  61.815 168.227 61.905 168.497 ;
     RECT  64.515 168.227 64.605 168.497 ;
     RECT  67.215 168.227 67.305 168.497 ;
     RECT  69.915 168.227 70.005 168.497 ;
     RECT  72.615 168.227 72.705 168.497 ;
     RECT  75.315 168.227 75.405 168.497 ;
     RECT  78.015 168.227 78.105 168.497 ;
     RECT  80.715 168.227 80.805 168.497 ;
     RECT  83.415 168.227 83.505 168.497 ;
     RECT  86.115 168.227 86.205 168.497 ;
     RECT  88.815 168.227 88.905 168.497 ;
     RECT  91.515 168.227 91.605 168.497 ;
     RECT  94.215 168.227 94.305 168.497 ;
     RECT  38.052 168.497 39.006 170.347 ;
     RECT  37.836 170.347 39.006 170.609 ;
     RECT  37.908 170.609 39.006 170.621 ;
    LAYER M4 ;
     RECT  0.06 31.68 0.137 36.168 ;
     RECT  0.06 40.896 0.137 45.384 ;
     RECT  0.06 78.912 0.137 83.4 ;
     RECT  0.06 121.248 0.137 124.44 ;
     RECT  0.137 31.728 2.252 36.168 ;
     RECT  2.252 31.728 2.408 36.264 ;
     RECT  0.137 41.04 2.408 45.384 ;
     RECT  0.137 78.96 2.408 83.256 ;
     RECT  0.06 84.672 2.408 89.16 ;
     RECT  0.137 121.392 2.408 124.44 ;
     RECT  2.408 2.148 2.512 168.492 ;
     RECT  2.512 2.418 2.704 168.222 ;
     RECT  2.704 84.672 3.449 89.16 ;
     RECT  2.704 31.728 3.881 36.12 ;
     RECT  2.704 78.96 3.925 83.256 ;
     RECT  2.704 121.392 4.412 124.296 ;
     RECT  2.704 41.088 4.501 45.432 ;
     RECT  3.449 84.96 4.885 89.16 ;
     RECT  3.881 31.968 5.108 36.12 ;
     RECT  4.501 40.992 5.108 45.432 ;
     RECT  3.925 78.624 5.108 83.256 ;
     RECT  4.885 84.864 5.108 89.16 ;
     RECT  4.412 121.152 5.108 124.296 ;
     RECT  5.108 2.148 5.212 168.492 ;
     RECT  5.212 2.418 5.404 168.222 ;
     RECT  5.404 41.136 5.429 45.24 ;
     RECT  5.404 34.416 5.501 36.024 ;
     RECT  5.404 84.576 5.501 88.44 ;
     RECT  5.501 34.752 5.555 36.024 ;
     RECT  5.429 41.136 5.555 44.904 ;
     RECT  5.404 82.224 5.573 83.208 ;
     RECT  5.555 44.064 5.609 44.904 ;
     RECT  5.404 122.4 5.609 124.296 ;
     RECT  5.404 31.776 5.645 33.288 ;
     RECT  5.555 36 5.645 36.024 ;
     RECT  5.404 80.352 5.645 80.808 ;
     RECT  5.501 86.64 5.645 88.44 ;
     RECT  5.645 86.64 5.699 87.576 ;
     RECT  5.645 32.784 5.717 32.808 ;
     RECT  5.609 44.208 5.717 44.904 ;
     RECT  5.717 44.208 5.825 44.76 ;
     RECT  5.609 124.272 5.833 124.296 ;
     RECT  5.609 122.4 5.897 123.144 ;
     RECT  5.404 115.344 5.987 115.704 ;
     RECT  5.555 34.752 6.257 34.776 ;
     RECT  5.555 41.136 6.275 43.08 ;
     RECT  5.645 80.784 6.541 80.808 ;
     RECT  5.501 84.576 6.716 85.272 ;
     RECT  5.699 87.216 6.757 87.576 ;
     RECT  5.573 82.656 6.797 83.208 ;
     RECT  6.757 87.216 6.825 87.816 ;
     RECT  6.685 88.944 6.901 88.968 ;
     RECT  6.716 84.576 7.009 86.184 ;
     RECT  6.469 79.728 7.045 79.752 ;
     RECT  6.577 123.168 7.225 123.192 ;
     RECT  7.009 83.712 7.381 86.184 ;
     RECT  7.153 36.672 7.669 36.696 ;
     RECT  6.901 88.848 7.801 88.968 ;
     RECT  5.645 31.776 7.808 31.8 ;
     RECT  6.613 34.944 7.808 34.968 ;
     RECT  7.669 36.336 7.808 36.696 ;
     RECT  5.404 39.984 7.808 40.008 ;
     RECT  6.275 41.136 7.808 41.448 ;
     RECT  6.275 42.48 7.808 43.08 ;
     RECT  5.825 44.208 7.808 44.232 ;
     RECT  6.721 45.552 7.808 45.576 ;
     RECT  5.404 68.928 7.808 68.952 ;
     RECT  7.045 79.728 7.808 79.8 ;
     RECT  6.541 80.784 7.808 81.624 ;
     RECT  6.797 82.656 7.808 82.68 ;
     RECT  7.381 83.712 7.808 86.328 ;
     RECT  6.825 87.792 7.808 87.816 ;
     RECT  7.801 88.848 7.808 89.208 ;
     RECT  5.987 115.344 7.808 115.368 ;
     RECT  7.225 123.168 7.808 123.48 ;
     RECT  7.808 2.148 7.912 168.492 ;
     RECT  7.912 2.418 8.104 168.222 ;
     RECT  8.104 41.136 8.129 41.256 ;
     RECT  8.104 34.944 8.201 34.968 ;
     RECT  8.104 36.336 8.201 36.36 ;
     RECT  8.104 79.776 8.201 79.8 ;
     RECT  8.104 123.456 8.237 123.48 ;
     RECT  8.104 89.184 8.243 89.208 ;
     RECT  8.104 43.056 8.309 43.08 ;
     RECT  8.104 83.76 8.309 83.784 ;
     RECT  8.104 88.176 8.309 88.2 ;
     RECT  8.129 41.232 8.489 41.256 ;
     RECT  8.104 68.928 10.508 68.952 ;
     RECT  8.104 86.304 10.508 86.328 ;
     RECT  8.104 115.344 10.508 115.368 ;
     RECT  10.508 2.148 10.612 168.492 ;
     RECT  10.612 2.418 10.804 168.222 ;
     RECT  10.804 86.304 10.829 86.472 ;
     RECT  10.804 68.928 13.208 68.952 ;
     RECT  10.829 86.448 13.208 86.472 ;
     RECT  10.804 115.344 13.208 115.368 ;
     RECT  13.208 2.148 13.312 168.492 ;
     RECT  13.312 2.418 13.504 168.222 ;
     RECT  13.504 68.832 13.601 68.952 ;
     RECT  13.601 68.832 14.821 68.856 ;
     RECT  13.504 86.448 14.821 86.472 ;
     RECT  14.821 86.448 14.861 86.568 ;
     RECT  14.821 68.736 15.217 68.856 ;
     RECT  15.217 68.736 15.908 68.952 ;
     RECT  14.861 86.544 15.908 86.568 ;
     RECT  13.504 115.344 15.908 115.368 ;
     RECT  15.908 2.148 16.012 168.492 ;
     RECT  16.012 2.418 16.204 168.222 ;
     RECT  16.204 68.736 16.841 68.952 ;
     RECT  16.841 68.832 16.883 68.952 ;
     RECT  16.883 68.928 18.608 68.952 ;
     RECT  16.204 74.592 18.608 74.616 ;
     RECT  16.204 86.544 18.608 86.568 ;
     RECT  16.204 115.344 18.608 115.368 ;
     RECT  18.608 2.148 18.712 168.492 ;
     RECT  18.712 2.418 18.904 168.222 ;
     RECT  18.904 68.928 21.308 68.952 ;
     RECT  18.904 74.592 21.308 74.616 ;
     RECT  18.904 86.448 21.308 86.472 ;
     RECT  18.904 115.344 21.308 115.368 ;
     RECT  21.308 2.148 21.412 168.492 ;
     RECT  21.412 2.418 21.604 168.222 ;
     RECT  21.604 68.928 22.499 68.952 ;
     RECT  21.604 115.152 22.573 115.368 ;
     RECT  21.604 88.512 22.643 88.92 ;
     RECT  21.604 99.696 22.7 99.72 ;
     RECT  22.643 88.608 22.733 88.92 ;
     RECT  22.7 99.6 22.787 99.72 ;
     RECT  21.604 86.448 22.813 86.472 ;
     RECT  22.733 88.608 22.817 88.968 ;
     RECT  22.813 86.448 22.853 86.568 ;
     RECT  22.817 88.608 23.033 88.632 ;
     RECT  21.604 74.592 24.008 74.616 ;
     RECT  22.853 86.544 24.008 86.568 ;
     RECT  22.787 99.696 24.008 99.72 ;
     RECT  22.573 115.344 24.008 115.368 ;
     RECT  24.008 2.148 24.112 168.492 ;
     RECT  24.112 2.418 24.304 168.222 ;
     RECT  24.304 74.592 26.708 74.616 ;
     RECT  24.304 86.544 26.708 86.568 ;
     RECT  24.304 99.696 26.708 99.72 ;
     RECT  24.304 115.344 26.708 115.368 ;
     RECT  26.708 2.148 26.812 168.492 ;
     RECT  26.812 2.418 27.004 168.222 ;
     RECT  27.004 74.592 29.408 74.616 ;
     RECT  27.004 86.544 29.408 86.568 ;
     RECT  27.004 99.696 29.408 99.72 ;
     RECT  27.004 115.344 29.408 115.368 ;
     RECT  29.408 2.148 29.512 168.492 ;
     RECT  29.512 2.418 29.704 168.222 ;
     RECT  29.704 86.448 30.769 86.472 ;
     RECT  30.769 86.448 30.809 86.568 ;
     RECT  29.704 74.592 32.108 74.616 ;
     RECT  30.809 86.544 32.108 86.568 ;
     RECT  29.704 99.696 32.108 99.72 ;
     RECT  29.704 115.344 32.108 115.368 ;
     RECT  32.108 2.148 32.212 168.492 ;
     RECT  32.212 2.418 32.404 168.222 ;
     RECT  32.404 74.592 34.808 74.616 ;
     RECT  32.404 86.544 34.808 86.568 ;
     RECT  32.404 99.696 34.808 99.72 ;
     RECT  32.404 115.344 34.808 115.368 ;
     RECT  34.808 2.148 34.912 168.492 ;
     RECT  34.912 2.418 35.104 168.222 ;
     RECT  35.104 126.144 35.308 126.168 ;
     RECT  35.104 119.904 35.651 121.032 ;
     RECT  35.104 122.352 35.651 122.808 ;
     RECT  35.651 119.904 35.692 120.504 ;
     RECT  35.104 115.104 35.891 116.712 ;
     RECT  36.236 133.68 36.323 133.704 ;
     RECT  35.104 127.632 36.349 127.656 ;
     RECT  36.349 126.672 36.757 127.656 ;
     RECT  35.692 120.48 36.961 120.504 ;
     RECT  36.757 125.952 37.004 127.656 ;
     RECT  36.205 131.424 37.033 131.448 ;
     RECT  37.033 131.088 37.045 131.448 ;
     RECT  35.104 132.48 37.045 132.504 ;
     RECT  35.104 130.08 37.052 130.104 ;
     RECT  37.045 131.088 37.213 132.504 ;
     RECT  35.651 122.784 37.357 122.808 ;
     RECT  37.052 129.936 37.357 130.104 ;
     RECT  37.213 131.088 37.357 133.32 ;
     RECT  35.891 116.688 37.381 116.712 ;
     RECT  35.104 118.032 37.381 118.728 ;
     RECT  36.961 120.48 37.393 120.984 ;
     RECT  37.357 122.784 37.465 122.952 ;
     RECT  35.104 74.592 37.508 74.616 ;
     RECT  35.104 86.544 37.508 86.568 ;
     RECT  35.104 99.696 37.508 99.72 ;
     RECT  36.661 101.376 37.508 101.4 ;
     RECT  36.62 114.096 37.508 114.12 ;
     RECT  35.891 115.104 37.508 115.368 ;
     RECT  37.381 116.688 37.508 118.728 ;
     RECT  37.393 120.24 37.508 120.984 ;
     RECT  37.465 122.496 37.508 122.952 ;
     RECT  35.104 124.272 37.508 124.824 ;
     RECT  37.004 125.952 37.508 128.28 ;
     RECT  37.357 129.936 37.508 133.32 ;
     RECT  37.093 141.36 37.508 141.384 ;
     RECT  37.141 142.368 37.508 142.392 ;
     RECT  37.1 166.416 37.508 166.44 ;
     RECT  37.508 2.148 37.612 168.492 ;
     RECT  37.612 2.418 37.804 168.222 ;
     RECT  37.804 122.496 37.865 122.568 ;
     RECT  37.825 170.352 37.957 170.376 ;
     RECT  37.804 99.696 38.003 99.72 ;
     RECT  37.957 170.352 38.044 170.52 ;
     RECT  37.804 117.504 38.099 118.728 ;
     RECT  37.865 122.544 38.153 122.568 ;
     RECT  37.804 127.008 38.153 127.752 ;
     RECT  38.044 170.352 38.153 170.472 ;
     RECT  37.804 124.8 38.225 125.4 ;
     RECT  37.804 101.376 38.233 101.448 ;
     RECT  37.804 113.376 38.243 114.024 ;
     RECT  38.153 127.056 38.291 127.752 ;
     RECT  37.804 115.104 38.297 116.28 ;
     RECT  37.804 130.512 38.387 131.496 ;
     RECT  37.804 133.296 38.387 134.088 ;
     RECT  37.804 135.648 38.387 137.352 ;
     RECT  38.387 135.648 38.428 136.488 ;
     RECT  38.428 135.648 38.441 135.672 ;
     RECT  37.804 92.88 38.531 93.528 ;
     RECT  38.297 115.104 38.531 115.8 ;
     RECT  38.099 118.464 38.531 118.728 ;
     RECT  38.531 118.464 38.585 118.536 ;
     RECT  38.387 130.512 38.621 130.536 ;
     RECT  38.531 93.36 38.627 93.528 ;
     RECT  37.804 55.296 38.723 55.32 ;
     RECT  37.804 52.752 38.729 53.688 ;
     RECT  37.804 166.464 38.729 166.488 ;
     RECT  37.804 48.768 38.773 50.328 ;
     RECT  37.804 51.504 38.773 51.528 ;
     RECT  38.729 52.752 38.773 52.776 ;
     RECT  37.804 94.608 38.797 94.632 ;
     RECT  38.291 127.056 38.801 127.08 ;
     RECT  38.773 48.768 38.819 52.776 ;
     RECT  38.797 94.608 38.821 95.448 ;
     RECT  38.819 48.768 38.86 51 ;
     RECT  38.86 48.768 38.869 50.856 ;
     RECT  37.804 123.552 38.905 123.816 ;
     RECT  37.804 74.592 38.965 74.616 ;
     RECT  38.819 52.08 39.011 52.44 ;
     RECT  38.869 48.384 39.013 50.856 ;
     RECT  38.905 123.072 39.017 123.816 ;
     RECT  37.804 142.368 39.203 143.4 ;
     RECT  39.116 163.92 39.203 163.944 ;
     RECT  37.804 165.408 39.203 165.432 ;
     RECT  37.804 141.36 39.229 141.384 ;
     RECT  39.203 142.368 39.229 142.728 ;
     RECT  39.229 141.36 39.337 142.728 ;
     RECT  38.869 131.712 39.373 131.736 ;
     RECT  38.153 170.448 39.395 170.472 ;
     RECT  39.121 128.544 39.445 128.568 ;
     RECT  39.308 149.664 39.493 149.688 ;
     RECT  39.445 128.208 39.581 128.568 ;
     RECT  39.517 91.344 39.589 91.368 ;
     RECT  39.445 135.312 39.589 135.336 ;
     RECT  38.627 93.456 39.625 93.528 ;
     RECT  38.225 125.376 39.661 125.4 ;
     RECT  39.553 126.432 39.661 126.456 ;
     RECT  39.373 131.712 39.661 132.216 ;
     RECT  39.625 92.496 39.697 93.528 ;
     RECT  38.821 94.512 39.697 95.448 ;
     RECT  38.233 101.376 39.697 101.4 ;
     RECT  39.017 123.792 39.769 123.816 ;
     RECT  39.697 92.496 39.829 95.448 ;
     RECT  37.804 138.48 39.829 138.504 ;
     RECT  37.804 86.448 39.841 86.472 ;
     RECT  39.661 131.664 39.973 132.216 ;
     RECT  38.387 133.296 39.973 133.32 ;
     RECT  38.585 118.464 39.985 118.488 ;
     RECT  39.589 90.864 40.021 91.368 ;
     RECT  39.829 92.496 40.021 96.072 ;
     RECT  38.965 73.776 40.049 74.616 ;
     RECT  39.769 84.864 40.069 84.888 ;
     RECT  39.769 123.792 40.069 123.864 ;
     RECT  39.661 125.376 40.069 126.456 ;
     RECT  40.028 88.8 40.201 88.824 ;
     RECT  40.129 46.224 40.208 46.248 ;
     RECT  39.013 47.712 40.208 50.856 ;
     RECT  39.011 52.416 40.208 52.44 ;
     RECT  40.049 73.776 40.208 75.048 ;
     RECT  40.069 84.336 40.208 84.888 ;
     RECT  39.841 86.448 40.208 87.096 ;
     RECT  40.201 88.8 40.208 88.92 ;
     RECT  40.021 90.864 40.208 96.072 ;
     RECT  39.697 100.992 40.208 101.4 ;
     RECT  39.349 105.936 40.208 105.96 ;
     RECT  37.804 110.496 40.208 110.52 ;
     RECT  39.973 114.384 40.208 114.408 ;
     RECT  39.409 116.688 40.208 116.712 ;
     RECT  39.985 118.464 40.208 118.776 ;
     RECT  40.021 122.544 40.208 122.568 ;
     RECT  40.069 123.792 40.208 126.456 ;
     RECT  39.581 128.208 40.208 129.432 ;
     RECT  39.973 131.664 40.208 133.32 ;
     RECT  39.589 134.496 40.208 135.336 ;
     RECT  39.769 137.088 40.208 137.112 ;
     RECT  39.829 138.48 40.208 138.696 ;
     RECT  39.337 140.592 40.208 142.728 ;
     RECT  39.493 149.616 40.208 149.688 ;
     RECT  40.208 2.148 40.312 168.492 ;
     RECT  40.312 2.418 40.504 168.222 ;
     RECT  40.504 87.072 40.745 87.096 ;
     RECT  40.504 58.704 40.931 58.92 ;
     RECT  40.931 58.896 40.997 58.92 ;
     RECT  40.504 120.768 41.027 120.888 ;
     RECT  40.504 122.112 41.027 123.96 ;
     RECT  40.504 127.68 41.033 127.704 ;
     RECT  41.027 122.112 41.141 122.136 ;
     RECT  41.027 123.696 41.141 123.72 ;
     RECT  40.504 125.904 41.213 126.216 ;
     RECT  40.504 114.384 41.465 114.408 ;
     RECT  40.504 45.024 41.497 51.192 ;
     RECT  40.504 52.224 41.497 53.784 ;
     RECT  40.504 88.896 41.497 89.016 ;
     RECT  40.504 90.816 41.497 94.104 ;
     RECT  40.504 95.424 41.497 96.792 ;
     RECT  40.504 139.776 41.497 139.992 ;
     RECT  41.497 45.024 41.509 53.784 ;
     RECT  40.504 116.88 41.509 116.904 ;
     RECT  41.497 139.488 41.533 139.992 ;
     RECT  41.533 139.2 41.569 139.992 ;
     RECT  41.497 88.896 41.605 94.104 ;
     RECT  41.497 95.136 41.605 96.792 ;
     RECT  40.504 131.04 41.605 132.504 ;
     RECT  40.504 137.376 41.605 137.4 ;
     RECT  41.569 139.104 41.605 139.992 ;
     RECT  41.213 125.904 41.645 125.928 ;
     RECT  40.504 117.984 41.74 118.104 ;
     RECT  41.605 88.224 41.821 96.792 ;
     RECT  41.749 114 41.833 114.024 ;
     RECT  41.027 120.864 41.861 120.888 ;
     RECT  41.821 88.128 41.893 96.792 ;
     RECT  40.504 83.184 41.989 83.208 ;
     RECT  41.749 84.192 41.989 84.216 ;
     RECT  40.504 107.616 41.989 107.64 ;
     RECT  41.893 88.128 42.073 96.984 ;
     RECT  41.989 83.184 42.133 84.216 ;
     RECT  41.989 107.472 42.133 107.64 ;
     RECT  42.073 87.936 42.145 96.984 ;
     RECT  41.605 137.376 42.145 139.992 ;
     RECT  40.504 86.016 42.229 86.04 ;
     RECT  42.145 87.552 42.229 96.984 ;
     RECT  42.133 83.184 42.284 84.36 ;
     RECT  42.284 82.944 42.433 84.36 ;
     RECT  42.433 147.072 42.505 147.096 ;
     RECT  41.509 44.352 42.517 53.784 ;
     RECT  41.509 116.448 42.517 116.904 ;
     RECT  42.505 147.072 42.577 147.24 ;
     RECT  41.605 131.04 42.649 133.272 ;
     RECT  42.517 44.16 42.661 53.784 ;
     RECT  42.661 64.944 42.709 64.968 ;
     RECT  42.649 130.656 42.709 133.272 ;
     RECT  42.709 64.608 42.908 64.968 ;
     RECT  40.504 73.776 42.908 73.8 ;
     RECT  42.469 79.776 42.908 79.8 ;
     RECT  42.433 82.656 42.908 84.36 ;
     RECT  40.504 105.936 42.908 105.96 ;
     RECT  42.133 107.472 42.908 108.36 ;
     RECT  40.504 110.496 42.908 110.52 ;
     RECT  42.517 116.448 42.908 117.432 ;
     RECT  42.565 118.56 42.908 118.584 ;
     RECT  41.557 119.712 42.908 119.736 ;
     RECT  42.649 126.432 42.908 126.456 ;
     RECT  42.145 137.28 42.973 139.992 ;
     RECT  42.908 2.148 43.012 41.052 ;
     RECT  42.908 62.628 43.012 84.36 ;
     RECT  42.908 105.828 43.012 127.452 ;
     RECT  42.908 149.028 43.012 168.492 ;
     RECT  42.709 130.368 43.081 133.272 ;
     RECT  43.081 129.456 43.2 133.272 ;
     RECT  42.973 137.28 43.2 140.184 ;
     RECT  43.012 2.418 43.204 40.782 ;
     RECT  43.012 62.898 43.204 84.36 ;
     RECT  43.012 105.936 43.204 127.182 ;
     RECT  43.012 149.298 43.204 168.222 ;
     RECT  43.204 83.76 43.229 84.36 ;
     RECT  43.204 119.712 43.229 119.736 ;
     RECT  43.204 126.432 43.229 126.456 ;
     RECT  42.661 43.968 43.272 53.784 ;
     RECT  40.504 61.008 43.272 61.032 ;
     RECT  42.229 86.016 43.272 96.984 ;
     RECT  40.504 103.776 43.272 103.8 ;
     RECT  43.2 129.456 43.272 140.184 ;
     RECT  42.577 147.072 43.272 147.288 ;
     RECT  43.272 129.456 43.331 147.288 ;
     RECT  43.204 64.56 43.372 64.968 ;
     RECT  43.229 84.336 43.553 84.36 ;
     RECT  43.204 107.808 43.553 108.504 ;
     RECT  43.553 107.808 43.589 108.216 ;
     RECT  43.372 64.944 45.608 64.968 ;
     RECT  43.204 73.776 45.608 73.8 ;
     RECT  44.732 83.76 45.608 83.784 ;
     RECT  43.204 105.936 45.608 105.96 ;
     RECT  43.589 107.808 45.608 107.832 ;
     RECT  43.204 110.496 45.608 110.52 ;
     RECT  45.608 2.148 45.712 41.052 ;
     RECT  45.608 62.628 45.712 84.252 ;
     RECT  45.608 105.828 45.712 127.452 ;
     RECT  45.608 149.028 45.712 168.492 ;
     RECT  45.712 2.418 45.904 40.782 ;
     RECT  45.712 62.898 45.904 83.982 ;
     RECT  45.712 105.936 45.904 127.182 ;
     RECT  45.712 149.298 45.904 168.222 ;
     RECT  45.904 73.776 48.308 73.8 ;
     RECT  45.904 105.936 48.308 105.96 ;
     RECT  45.904 110.496 48.308 110.52 ;
     RECT  48.308 2.148 48.412 41.052 ;
     RECT  48.308 62.628 48.412 84.252 ;
     RECT  48.308 105.828 48.412 127.452 ;
     RECT  48.308 149.028 48.412 168.492 ;
     RECT  48.412 2.418 48.604 40.782 ;
     RECT  48.412 62.898 48.604 83.982 ;
     RECT  48.412 105.936 48.604 127.182 ;
     RECT  48.412 149.298 48.604 168.222 ;
     RECT  48.604 73.776 51.008 73.8 ;
     RECT  48.604 105.936 51.008 105.96 ;
     RECT  48.604 110.496 51.008 110.52 ;
     RECT  51.008 2.148 51.112 41.052 ;
     RECT  51.008 62.628 51.112 84.252 ;
     RECT  51.008 105.828 51.112 127.452 ;
     RECT  51.008 149.028 51.112 168.492 ;
     RECT  51.112 2.418 51.304 40.782 ;
     RECT  51.112 62.898 51.304 83.982 ;
     RECT  51.112 105.936 51.304 127.182 ;
     RECT  51.112 149.298 51.304 168.222 ;
     RECT  51.304 73.776 53.708 73.8 ;
     RECT  51.304 105.936 53.708 105.96 ;
     RECT  51.304 110.496 53.708 110.52 ;
     RECT  53.708 2.148 53.812 41.052 ;
     RECT  53.708 62.628 53.812 84.252 ;
     RECT  53.708 105.828 53.812 127.452 ;
     RECT  53.708 149.028 53.812 168.492 ;
     RECT  53.812 2.418 54.004 40.782 ;
     RECT  53.812 62.898 54.004 83.982 ;
     RECT  53.812 105.936 54.004 127.182 ;
     RECT  53.812 149.298 54.004 168.222 ;
     RECT  54.004 73.776 56.408 73.8 ;
     RECT  54.004 105.936 56.408 105.96 ;
     RECT  54.004 110.496 56.408 110.52 ;
     RECT  56.408 2.148 56.512 41.052 ;
     RECT  56.408 62.628 56.512 84.252 ;
     RECT  56.408 105.828 56.512 127.452 ;
     RECT  56.408 149.028 56.512 168.492 ;
     RECT  56.512 2.418 56.704 40.782 ;
     RECT  56.512 62.898 56.704 83.982 ;
     RECT  56.512 105.936 56.704 127.182 ;
     RECT  56.512 149.298 56.704 168.222 ;
     RECT  56.704 73.776 59.108 73.8 ;
     RECT  56.704 105.936 59.108 105.96 ;
     RECT  56.704 110.496 59.108 110.52 ;
     RECT  59.108 2.148 59.212 41.052 ;
     RECT  59.108 62.628 59.212 84.252 ;
     RECT  59.108 105.828 59.212 127.452 ;
     RECT  59.108 149.028 59.212 168.492 ;
     RECT  59.212 2.418 59.404 40.782 ;
     RECT  59.212 62.898 59.404 83.982 ;
     RECT  59.212 105.936 59.404 127.182 ;
     RECT  59.212 149.298 59.404 168.222 ;
     RECT  59.404 73.776 61.808 73.8 ;
     RECT  59.404 105.936 61.808 105.96 ;
     RECT  59.404 110.496 61.808 110.52 ;
     RECT  61.808 2.148 61.912 41.052 ;
     RECT  61.808 62.628 61.912 84.252 ;
     RECT  61.808 105.828 61.912 127.452 ;
     RECT  61.808 149.028 61.912 168.492 ;
     RECT  61.912 2.418 62.104 40.782 ;
     RECT  61.912 62.898 62.104 83.982 ;
     RECT  61.912 105.936 62.104 127.182 ;
     RECT  61.912 149.298 62.104 168.222 ;
     RECT  62.104 73.776 64.508 73.8 ;
     RECT  62.104 105.936 64.508 105.96 ;
     RECT  62.104 110.496 64.508 110.52 ;
     RECT  64.508 2.148 64.612 41.052 ;
     RECT  64.508 62.628 64.612 84.252 ;
     RECT  64.508 105.828 64.612 127.452 ;
     RECT  64.508 149.028 64.612 168.492 ;
     RECT  64.612 2.418 64.804 40.782 ;
     RECT  64.612 62.898 64.804 84.216 ;
     RECT  64.612 105.936 64.804 127.182 ;
     RECT  64.612 149.298 64.804 168.222 ;
     RECT  64.804 105.936 65.081 105.96 ;
     RECT  64.804 84.096 65.459 84.216 ;
     RECT  64.804 110.016 65.459 110.52 ;
     RECT  65.459 84.096 65.843 84.12 ;
     RECT  65.797 105.456 66.161 105.48 ;
     RECT  64.804 73.776 67.208 74.088 ;
     RECT  65.459 110.496 67.208 110.52 ;
     RECT  67.208 2.148 67.312 41.052 ;
     RECT  67.208 62.628 67.312 84.252 ;
     RECT  67.208 105.828 67.312 127.452 ;
     RECT  67.208 149.028 67.312 168.492 ;
     RECT  67.312 2.418 67.504 40.782 ;
     RECT  67.312 62.898 67.504 83.982 ;
     RECT  67.312 106.098 67.504 127.182 ;
     RECT  67.312 149.298 67.504 168.222 ;
     RECT  67.504 73.776 69.908 74.088 ;
     RECT  67.504 110.496 69.908 110.52 ;
     RECT  69.908 2.148 70.012 41.052 ;
     RECT  69.908 62.628 70.012 84.252 ;
     RECT  69.908 105.828 70.012 127.452 ;
     RECT  69.908 149.028 70.012 168.492 ;
     RECT  70.012 2.418 70.204 40.782 ;
     RECT  70.012 62.898 70.204 83.982 ;
     RECT  70.012 106.098 70.204 127.182 ;
     RECT  70.012 149.298 70.204 168.222 ;
     RECT  70.204 73.776 72.608 74.088 ;
     RECT  70.204 110.496 72.608 110.52 ;
     RECT  72.608 2.148 72.712 41.052 ;
     RECT  72.608 62.628 72.712 84.252 ;
     RECT  72.608 105.828 72.712 127.452 ;
     RECT  72.608 149.028 72.712 168.492 ;
     RECT  72.712 2.418 72.904 40.782 ;
     RECT  72.712 62.898 72.904 83.982 ;
     RECT  72.712 106.098 72.904 127.182 ;
     RECT  72.712 149.298 72.904 168.222 ;
     RECT  43.331 129.6 73.861 147.288 ;
     RECT  73.897 126.144 73.967 126.168 ;
     RECT  72.904 123.12 74.045 123.144 ;
     RECT  72.904 110.496 74.051 110.52 ;
     RECT  72.904 124.128 74.581 124.152 ;
     RECT  73.967 125.616 74.689 126.168 ;
     RECT  74.689 125.28 74.761 126.168 ;
     RECT  74.005 106.992 74.917 107.016 ;
     RECT  74.581 124.128 74.941 124.248 ;
     RECT  74.941 124.128 75.085 124.296 ;
     RECT  74.761 125.28 75.085 126.936 ;
     RECT  43.272 43.2 75.12 61.032 ;
     RECT  43.272 86.016 75.12 103.8 ;
     RECT  73.861 128.832 75.12 147.288 ;
     RECT  75.085 124.128 75.265 126.936 ;
     RECT  75.12 128.832 75.269 140.184 ;
     RECT  75.049 84.912 75.305 84.936 ;
     RECT  75.12 87.168 75.305 96.984 ;
     RECT  75.121 41.568 75.308 41.592 ;
     RECT  72.904 73.776 75.308 74.088 ;
     RECT  74.917 106.992 75.308 107.4 ;
     RECT  72.904 120.432 75.308 120.456 ;
     RECT  74.329 121.536 75.308 121.56 ;
     RECT  74.677 122.544 75.308 122.568 ;
     RECT  75.265 124.128 75.308 127.032 ;
     RECT  75.12 43.968 75.341 53.88 ;
     RECT  75.305 87.168 75.341 96.888 ;
     RECT  75.269 129.408 75.341 140.184 ;
     RECT  75.341 43.968 75.377 53.688 ;
     RECT  75.341 129.408 75.377 140.088 ;
     RECT  75.308 2.148 75.412 41.592 ;
     RECT  75.308 62.628 75.412 84.252 ;
     RECT  75.308 105.828 75.412 127.452 ;
     RECT  75.308 149.028 75.412 168.492 ;
     RECT  75.377 129.408 75.557 139.992 ;
     RECT  75.12 61.008 75.593 61.032 ;
     RECT  75.412 2.418 75.604 41.592 ;
     RECT  75.412 62.898 75.604 83.982 ;
     RECT  75.412 106.098 75.604 127.452 ;
     RECT  75.412 149.298 75.604 168.222 ;
     RECT  75.604 123.84 75.661 127.452 ;
     RECT  75.604 41.568 75.731 41.592 ;
     RECT  75.661 123.84 75.745 127.656 ;
     RECT  75.557 129.408 75.827 139.896 ;
     RECT  75.377 43.968 75.845 53.592 ;
     RECT  75.745 123.84 75.845 127.272 ;
     RECT  75.845 48.672 75.881 53.592 ;
     RECT  75.845 123.84 75.881 126.84 ;
     RECT  75.827 130.368 75.917 139.896 ;
     RECT  75.881 123.84 76.025 125.64 ;
     RECT  75.845 43.968 76.097 47.64 ;
     RECT  76.025 125.376 76.097 125.64 ;
     RECT  75.881 48.768 76.133 53.592 ;
     RECT  75.917 130.56 76.133 139.896 ;
     RECT  76.133 48.768 76.421 53.496 ;
     RECT  76.025 124.272 76.421 124.296 ;
     RECT  76.133 130.848 76.457 139.896 ;
     RECT  75.881 126.816 76.637 126.84 ;
     RECT  75.341 87.168 76.709 96.792 ;
     RECT  75.604 73.776 77.221 74.088 ;
     RECT  76.457 130.848 77.425 134.04 ;
     RECT  76.457 135.072 77.701 139.896 ;
     RECT  76.097 44.064 78.008 47.64 ;
     RECT  76.421 48.864 78.008 53.496 ;
     RECT  77.221 73.776 78.008 74.28 ;
     RECT  75.12 86.016 78.008 86.04 ;
     RECT  76.709 87.168 78.008 96.504 ;
     RECT  75.12 103.776 78.008 103.8 ;
     RECT  75.604 106.992 78.008 107.4 ;
     RECT  76.097 125.616 78.008 125.64 ;
     RECT  77.425 130.512 78.008 134.04 ;
     RECT  77.701 135.072 78.008 140.76 ;
     RECT  75.12 147.072 78.008 147.288 ;
     RECT  78.008 2.148 78.112 168.492 ;
     RECT  78.112 2.418 78.304 168.222 ;
     RECT  78.304 73.776 78.689 73.896 ;
     RECT  78.304 44.064 79.517 47.688 ;
     RECT  79.517 44.064 80.708 44.472 ;
     RECT  79.517 45.744 80.708 47.688 ;
     RECT  78.689 73.872 80.708 73.896 ;
     RECT  78.304 87.264 80.708 90.888 ;
     RECT  78.304 103.776 80.708 103.8 ;
     RECT  78.304 106.992 80.708 107.4 ;
     RECT  78.304 140.736 80.708 140.76 ;
     RECT  78.304 147.072 80.708 147.288 ;
     RECT  80.708 2.148 80.812 168.492 ;
     RECT  80.812 2.418 81.004 168.222 ;
     RECT  81.004 44.064 81.065 44.472 ;
     RECT  81.065 44.064 81.533 44.376 ;
     RECT  81.004 45.744 82.037 47.688 ;
     RECT  81.533 44.064 83.408 44.136 ;
     RECT  82.037 46.848 83.408 47.688 ;
     RECT  81.004 73.872 83.408 73.896 ;
     RECT  81.004 87.36 83.408 90.888 ;
     RECT  81.004 103.776 83.408 103.8 ;
     RECT  81.004 106.992 83.408 107.4 ;
     RECT  81.004 140.736 83.408 140.76 ;
     RECT  81.004 147.072 83.408 147.288 ;
     RECT  83.408 2.148 83.512 168.492 ;
     RECT  83.512 2.418 83.704 168.222 ;
     RECT  83.704 87.888 83.801 87.912 ;
     RECT  83.704 89.712 83.801 90.648 ;
     RECT  83.704 44.064 83.837 44.136 ;
     RECT  83.801 89.712 83.837 89.736 ;
     RECT  83.704 47.424 84.197 47.448 ;
     RECT  85.813 37.968 86.108 37.992 ;
     RECT  85.777 41.04 86.108 41.064 ;
     RECT  83.837 44.064 86.108 44.088 ;
     RECT  83.704 73.872 86.108 73.896 ;
     RECT  83.704 103.776 86.108 103.8 ;
     RECT  83.704 106.992 86.108 107.4 ;
     RECT  83.704 140.736 86.108 140.76 ;
     RECT  83.704 147.072 86.108 147.288 ;
     RECT  86.108 2.148 86.212 168.492 ;
     RECT  86.212 2.418 86.404 168.222 ;
     RECT  86.404 73.872 86.681 74.04 ;
     RECT  86.404 37.968 88.808 37.992 ;
     RECT  86.404 44.064 88.808 44.088 ;
     RECT  86.681 73.872 88.808 73.896 ;
     RECT  86.404 103.776 88.808 103.8 ;
     RECT  86.404 106.992 88.808 107.016 ;
     RECT  86.404 140.736 88.808 140.76 ;
     RECT  86.404 147.072 88.808 147.288 ;
     RECT  88.808 2.148 88.912 168.492 ;
     RECT  88.912 2.418 89.104 168.222 ;
     RECT  89.104 96.864 89.843 96.888 ;
     RECT  89.104 98.304 89.884 98.328 ;
     RECT  89.104 81.888 90.097 81.912 ;
     RECT  89.104 39.888 90.133 39.912 ;
     RECT  89.104 99.696 90.137 99.72 ;
     RECT  90.133 39.888 90.179 40.152 ;
     RECT  89.104 55.248 90.236 55.272 ;
     RECT  89.104 56.4 90.236 56.424 ;
     RECT  90.236 55.248 90.323 56.424 ;
     RECT  89.104 43.344 90.476 44.088 ;
     RECT  90.179 40.128 90.493 40.152 ;
     RECT  90.241 41.712 90.493 41.736 ;
     RECT  90.493 40.128 90.673 41.736 ;
     RECT  90.476 42.72 90.673 44.088 ;
     RECT  90.323 55.248 90.709 55.272 ;
     RECT  89.104 84.576 90.961 84.6 ;
     RECT  90.673 40.128 91.177 44.088 ;
     RECT  90.709 55.152 91.213 55.272 ;
     RECT  90.493 100.848 91.32 100.872 ;
     RECT  91.32 100.512 91.343 100.872 ;
     RECT  90.961 84.576 91.381 84.888 ;
     RECT  91.249 86.208 91.381 86.232 ;
     RECT  90.457 98.112 91.381 98.136 ;
     RECT  89.104 140.736 91.393 140.76 ;
     RECT  90.097 141.84 91.393 141.864 ;
     RECT  91.381 98.064 91.465 98.136 ;
     RECT  89.104 37.968 91.508 37.992 ;
     RECT  91.177 39.792 91.508 44.088 ;
     RECT  89.104 53.568 91.508 53.592 ;
     RECT  91.213 54.672 91.508 55.272 ;
     RECT  90.323 56.4 91.508 56.424 ;
     RECT  91.189 72.816 91.508 72.84 ;
     RECT  89.104 73.872 91.508 73.896 ;
     RECT  90.097 81.888 91.508 82.44 ;
     RECT  91.381 84.576 91.508 86.232 ;
     RECT  90.601 96.912 91.508 96.936 ;
     RECT  91.465 98.064 91.508 98.472 ;
     RECT  91.343 99.696 91.508 100.872 ;
     RECT  89.104 103.776 91.508 103.8 ;
     RECT  89.104 106.992 91.508 107.016 ;
     RECT  89.104 139.248 91.508 139.272 ;
     RECT  91.393 140.736 91.508 141.864 ;
     RECT  89.104 147.072 91.508 147.288 ;
     RECT  91.508 2.148 91.612 168.492 ;
     RECT  91.612 2.418 91.804 168.222 ;
     RECT  91.804 85.872 91.955 86.232 ;
     RECT  91.804 44.064 92.045 44.088 ;
     RECT  91.804 140.16 92.189 141.576 ;
     RECT  91.804 98.064 92.405 98.472 ;
     RECT  92.189 141.552 92.693 141.576 ;
     RECT  91.804 39.504 92.869 42.6 ;
     RECT  92.869 39.216 92.909 42.6 ;
     RECT  93.005 42.768 93.02 42.792 ;
     RECT  93.02 42.768 93.107 43.32 ;
     RECT  91.804 84.864 93.161 84.888 ;
     RECT  92.405 98.064 93.205 98.088 ;
     RECT  91.804 54.672 93.229 55.176 ;
     RECT  91.804 56.448 93.229 56.664 ;
     RECT  91.804 81.648 93.301 81.912 ;
     RECT  91.804 72.816 93.404 72.84 ;
     RECT  92.909 39.216 93.445 41.736 ;
     RECT  91.804 53.232 93.445 53.256 ;
     RECT  91.804 99.648 93.493 99.72 ;
     RECT  93.229 54.672 93.517 56.664 ;
     RECT  92.189 140.16 93.697 140.184 ;
     RECT  93.404 72.624 93.733 72.84 ;
     RECT  93.301 81.264 93.877 81.912 ;
     RECT  91.804 37.968 93.884 37.992 ;
     RECT  93.445 39.072 93.884 41.736 ;
     RECT  93.884 37.968 93.949 41.736 ;
     RECT  93.107 42.768 93.949 43.272 ;
     RECT  93.445 53.232 93.949 53.592 ;
     RECT  93.517 54.672 93.949 56.856 ;
     RECT  93.949 37.968 94.021 43.272 ;
     RECT  93.697 140.16 94.021 140.76 ;
     RECT  93.949 53.232 94.049 56.856 ;
     RECT  93.877 81.264 94.057 82.68 ;
     RECT  94.021 37.872 94.208 43.272 ;
     RECT  94.049 52.944 94.208 56.856 ;
     RECT  93.733 72.624 94.208 72.936 ;
     RECT  94.057 81.264 94.208 83.256 ;
     RECT  92.941 96.288 94.208 96.312 ;
     RECT  93.205 97.536 94.208 98.088 ;
     RECT  93.493 99.648 94.208 100.296 ;
     RECT  91.804 103.776 94.208 103.8 ;
     RECT  94.021 139.488 94.208 141.288 ;
     RECT  91.804 147.072 94.208 147.288 ;
     RECT  94.208 2.148 94.312 168.492 ;
     RECT  94.312 2.418 94.504 168.222 ;
     RECT  94.504 139.488 94.565 141.288 ;
     RECT  94.565 139.488 94.745 141 ;
     RECT  94.504 100.224 94.752 100.296 ;
     RECT  94.504 96.912 94.889 99.192 ;
     RECT  94.504 147.072 95.501 147.288 ;
     RECT  94.745 139.824 95.605 141 ;
     RECT  94.504 103.776 95.609 103.8 ;
     RECT  94.504 52.848 95.749 55.032 ;
     RECT  94.889 96.912 95.749 98.664 ;
     RECT  94.752 100.224 95.749 100.248 ;
     RECT  95.501 147.072 95.825 147.096 ;
     RECT  95.749 96.624 95.893 98.664 ;
     RECT  95.749 100.224 95.893 100.824 ;
     RECT  95.605 139.824 95.893 141.864 ;
     RECT  94.504 37.872 95.933 43.416 ;
     RECT  95.749 52.56 96.289 55.608 ;
     RECT  95.749 56.88 96.289 56.904 ;
     RECT  95.893 139.68 96.289 141.864 ;
     RECT  95.893 96.624 96.325 100.824 ;
     RECT  96.289 139.104 96.325 141.864 ;
     RECT  94.504 81.36 96.901 85.704 ;
     RECT  95.933 38.736 96.973 43.08 ;
     RECT  96.289 52.56 97.477 56.904 ;
     RECT  96.325 139.104 97.477 142.008 ;
     RECT  96.973 38.736 98.22 43.224 ;
     RECT  97.477 52.56 98.22 57.048 ;
     RECT  96.901 81.36 98.22 85.848 ;
     RECT  96.325 96.336 98.22 100.824 ;
     RECT  97.477 139.104 98.22 142.296 ;
     RECT  98.22 81.744 98.273 81.768 ;
    LAYER M5 ;
     RECT  2.4 2.137 2.52 2.151 ;
     RECT  5.1 2.137 5.22 2.151 ;
     RECT  7.8 2.137 7.92 2.151 ;
     RECT  10.5 2.137 10.62 2.151 ;
     RECT  13.2 2.137 13.32 2.151 ;
     RECT  15.9 2.137 16.02 2.151 ;
     RECT  18.6 2.137 18.72 2.151 ;
     RECT  21.3 2.137 21.42 2.151 ;
     RECT  24 2.137 24.12 2.151 ;
     RECT  26.7 2.137 26.82 2.151 ;
     RECT  29.4 2.137 29.52 2.151 ;
     RECT  32.1 2.137 32.22 2.151 ;
     RECT  34.8 2.137 34.92 2.151 ;
     RECT  37.5 2.137 37.62 2.151 ;
     RECT  40.2 2.137 40.32 2.151 ;
     RECT  42.9 2.137 43.02 2.151 ;
     RECT  45.6 2.137 45.72 2.151 ;
     RECT  48.3 2.137 48.42 2.151 ;
     RECT  51 2.137 51.12 2.151 ;
     RECT  53.7 2.137 53.82 2.151 ;
     RECT  56.4 2.137 56.52 2.151 ;
     RECT  59.1 2.137 59.22 2.151 ;
     RECT  61.8 2.137 61.92 2.151 ;
     RECT  64.5 2.137 64.62 2.151 ;
     RECT  67.2 2.137 67.32 2.151 ;
     RECT  69.9 2.137 70.02 2.151 ;
     RECT  72.6 2.137 72.72 2.151 ;
     RECT  75.3 2.137 75.42 2.151 ;
     RECT  78 2.137 78.12 2.151 ;
     RECT  80.7 2.137 80.82 2.151 ;
     RECT  83.4 2.137 83.52 2.151 ;
     RECT  86.1 2.137 86.22 2.151 ;
     RECT  88.8 2.137 88.92 2.151 ;
     RECT  91.5 2.137 91.62 2.151 ;
     RECT  94.2 2.137 94.32 2.151 ;
     RECT  5.1 2.151 5.412 35.173 ;
     RECT  3.888 35.173 3.912 35.939 ;
     RECT  2.4 2.151 2.712 36.085 ;
     RECT  2.304 36.085 2.712 36.275 ;
     RECT  7.8 2.151 8.112 36.325 ;
     RECT  86.1 2.151 86.412 37.957 ;
     RECT  94.2 2.151 94.512 38.101 ;
     RECT  94.2 38.101 94.632 38.149 ;
     RECT  95.76 38.005 95.784 38.149 ;
     RECT  95.712 38.149 95.784 38.629 ;
     RECT  95.664 38.629 95.784 38.915 ;
     RECT  93.936 38.149 94.632 39.061 ;
     RECT  95.664 38.915 95.736 39.205 ;
     RECT  93.456 39.061 94.632 39.637 ;
     RECT  95.616 39.205 95.736 39.637 ;
     RECT  90.144 39.877 90.168 40.163 ;
     RECT  93.456 39.637 95.736 40.547 ;
     RECT  5.1 35.173 5.544 40.981 ;
     RECT  85.824 37.957 86.412 41.075 ;
     RECT  93.456 40.547 94.512 41.075 ;
     RECT  95.616 40.547 95.736 41.173 ;
     RECT  7.68 36.325 8.112 41.267 ;
     RECT  4.512 40.981 5.544 41.413 ;
     RECT  75.3 2.151 75.612 41.557 ;
     RECT  4.512 41.413 6.264 41.651 ;
     RECT  95.616 41.173 96.312 41.651 ;
     RECT  94.08 41.075 94.512 41.699 ;
     RECT  5.1 41.651 6.264 42.179 ;
     RECT  94.2 41.699 94.512 42.469 ;
     RECT  95.616 41.651 95.784 42.469 ;
     RECT  91.5 2.151 91.812 42.709 ;
     RECT  94.2 42.469 95.784 42.709 ;
     RECT  93.024 41.701 93.048 42.803 ;
     RECT  90.528 42.709 91.812 43.379 ;
     RECT  94.08 42.709 95.784 43.379 ;
     RECT  94.08 43.379 95.112 43.427 ;
     RECT  42.9 2.151 43.212 43.957 ;
     RECT  42.672 43.957 43.212 44.149 ;
     RECT  41.52 44.341 41.544 44.437 ;
     RECT  42.528 44.149 43.212 44.437 ;
     RECT  2.4 36.275 2.712 44.773 ;
     RECT  2.304 44.773 2.712 44.915 ;
     RECT  80.7 2.151 81.012 45.733 ;
     RECT  80.496 45.733 81.012 45.973 ;
     RECT  80.4 45.973 81.012 46.115 ;
     RECT  75.3 41.557 75.72 48.131 ;
     RECT  40.2 2.151 40.512 48.421 ;
     RECT  39.888 48.421 40.512 49.907 ;
     RECT  38.784 50.965 38.808 52.069 ;
     RECT  40.08 49.907 40.512 52.357 ;
     RECT  41.52 44.437 43.212 52.357 ;
     RECT  37.5 2.151 37.812 52.741 ;
     RECT  38.784 52.069 39 52.741 ;
     RECT  95.76 53.365 95.784 53.891 ;
     RECT  93.072 43.285 93.096 54.661 ;
     RECT  94.08 43.427 94.512 54.661 ;
     RECT  93.072 54.661 94.512 54.707 ;
     RECT  96.288 54.277 96.312 54.755 ;
     RECT  37.5 52.741 39 55.331 ;
     RECT  90.288 55.813 90.312 56.435 ;
     RECT  40.08 52.357 43.212 61.043 ;
     RECT  41.52 61.043 43.212 64.549 ;
     RECT  45.6 2.151 45.912 64.933 ;
     RECT  15.9 2.151 16.212 68.821 ;
     RECT  21.3 2.151 21.612 68.917 ;
     RECT  93.456 54.707 94.512 72.659 ;
     RECT  91.5 43.379 91.812 72.805 ;
     RECT  78 2.151 78.312 73.765 ;
     RECT  38.976 55.331 39 73.811 ;
     RECT  91.2 72.805 91.812 73.907 ;
     RECT  64.5 2.151 64.812 74.053 ;
     RECT  77.232 73.765 78.312 74.291 ;
     RECT  15.9 68.821 16.872 74.627 ;
     RECT  3.936 78.613 3.96 79.187 ;
     RECT  2.4 44.915 2.712 81.445 ;
     RECT  5.1 42.179 5.544 82.021 ;
     RECT  4.32 82.021 5.544 82.451 ;
     RECT  93.888 72.659 94.512 82.691 ;
     RECT  2.4 81.445 3 82.885 ;
     RECT  5.1 82.451 5.544 83.173 ;
     RECT  64.5 74.053 65.448 84.085 ;
     RECT  41.52 64.549 43.32 84.371 ;
     RECT  2.4 82.885 3.288 84.851 ;
     RECT  91.392 73.907 91.812 84.853 ;
     RECT  7.8 41.267 8.112 85.477 ;
     RECT  40.08 61.043 40.512 86.005 ;
     RECT  41.52 84.371 43.212 86.005 ;
     RECT  6.768 85.477 8.112 86.195 ;
     RECT  91.392 84.853 91.944 86.243 ;
     RECT  7.392 86.195 8.112 86.339 ;
     RECT  40.08 86.005 43.212 86.533 ;
     RECT  5.1 83.173 5.688 86.581 ;
     RECT  4.512 86.581 5.688 87.541 ;
     RECT  6.768 87.205 6.792 87.541 ;
     RECT  4.512 87.541 6.792 87.587 ;
     RECT  5.1 87.587 6.792 87.827 ;
     RECT  7.8 86.339 8.112 88.165 ;
     RECT  21.3 68.917 22.488 88.501 ;
     RECT  21.3 88.501 22.632 88.933 ;
     RECT  78 74.291 78.312 88.981 ;
     RECT  7.8 88.165 8.232 89.219 ;
     RECT  78 88.981 78.696 89.219 ;
     RECT  40.032 86.533 43.212 91.619 ;
     RECT  37.5 55.331 37.812 92.869 ;
     RECT  37.5 92.869 38.52 93.349 ;
     RECT  37.5 93.349 38.616 93.445 ;
     RECT  37.5 93.445 38.76 94.501 ;
     RECT  37.5 94.501 38.856 94.643 ;
     RECT  40.2 91.619 43.212 95.413 ;
     RECT  94.2 82.691 94.512 96.277 ;
     RECT  88.8 2.151 89.112 96.853 ;
     RECT  91.392 86.243 91.812 98.099 ;
     RECT  93.216 96.277 94.512 98.099 ;
     RECT  94.2 98.099 94.512 99.157 ;
     RECT  21.3 88.933 22.776 99.635 ;
     RECT  37.5 94.643 37.812 99.685 ;
     RECT  91.5 98.099 91.812 99.685 ;
     RECT  94.2 99.157 94.68 99.685 ;
     RECT  88.8 96.853 89.832 99.731 ;
     RECT  93.504 99.685 94.68 100.307 ;
     RECT  91.392 99.685 91.812 100.837 ;
     RECT  39.84 95.413 43.212 101.027 ;
     RECT  37.5 99.685 37.992 101.365 ;
     RECT  36.672 101.365 37.992 101.413 ;
     RECT  64.5 84.085 65.832 105.491 ;
     RECT  40.2 101.027 43.212 105.925 ;
     RECT  86.1 41.075 86.412 106.981 ;
     RECT  90.528 100.837 91.812 107.027 ;
     RECT  74.016 106.981 74.04 107.365 ;
     RECT  75.3 48.131 75.612 107.365 ;
     RECT  85.488 106.981 86.412 107.411 ;
     RECT  44.784 64.933 45.912 107.843 ;
     RECT  39.36 105.925 43.212 108.469 ;
     RECT  64.5 105.491 65.448 110.051 ;
     RECT  36.672 101.413 38.184 110.531 ;
     RECT  36.672 110.531 38.088 113.365 ;
     RECT  36.672 113.365 38.232 114.131 ;
     RECT  34.8 2.151 35.112 115.093 ;
     RECT  37.5 114.131 38.232 115.093 ;
     RECT  39.36 108.469 43.32 115.093 ;
     RECT  21.3 99.635 22.536 115.187 ;
     RECT  5.1 87.827 5.976 115.715 ;
     RECT  34.8 115.093 35.88 116.339 ;
     RECT  37.5 115.093 43.32 117.493 ;
     RECT  37.392 117.493 43.32 118.019 ;
     RECT  42.576 118.019 43.32 118.595 ;
     RECT  34.8 116.339 35.112 118.693 ;
     RECT  37.392 118.019 41.592 119.747 ;
     RECT  37.392 119.747 41.016 120.949 ;
     RECT  5.1 115.715 5.784 121.141 ;
     RECT  4.464 121.141 5.784 121.955 ;
     RECT  34.8 118.693 35.64 122.387 ;
     RECT  74.016 107.365 75.612 122.579 ;
     RECT  37.104 120.949 41.016 122.773 ;
     RECT  5.1 121.955 5.784 124.307 ;
     RECT  36.432 122.773 41.016 124.307 ;
     RECT  34.8 122.387 35.112 124.789 ;
     RECT  75.3 122.579 75.612 125.413 ;
     RECT  78 89.219 78.312 125.605 ;
     RECT  74.016 122.579 74.04 125.651 ;
     RECT  37.104 124.307 41.016 125.941 ;
     RECT  34.8 124.789 35.256 126.179 ;
     RECT  36.768 125.941 41.016 127.091 ;
     RECT  37.056 127.091 41.016 127.715 ;
     RECT  75.3 125.413 75.768 129.397 ;
     RECT  42.72 118.595 43.32 129.491 ;
     RECT  37.056 127.715 40.512 130.115 ;
     RECT  42.72 129.491 43.212 130.403 ;
     RECT  77.712 125.605 78.312 130.501 ;
     RECT  77.472 130.501 78.312 131.315 ;
     RECT  37.104 130.115 40.512 131.605 ;
     RECT  75.3 129.397 75.816 132.227 ;
     RECT  37.056 131.605 40.512 132.469 ;
     RECT  36.288 132.469 40.512 133.715 ;
     RECT  75.3 132.227 75.768 134.531 ;
     RECT  75.3 134.531 75.72 134.627 ;
     RECT  94.2 100.307 94.512 139.477 ;
     RECT  77.712 131.315 78.312 140.771 ;
     RECT  94.032 139.477 94.512 141.299 ;
     RECT  37.104 133.715 40.512 141.395 ;
     RECT  37.5 141.395 40.512 142.357 ;
     RECT  37.152 142.357 40.512 143.411 ;
     RECT  39.168 143.411 40.512 165.443 ;
     RECT  37.152 143.411 37.992 166.451 ;
     RECT  2.4 84.851 2.712 168.489 ;
     RECT  5.1 124.307 5.412 168.489 ;
     RECT  7.8 89.219 8.112 168.489 ;
     RECT  10.5 2.151 10.812 168.489 ;
     RECT  13.2 2.151 13.512 168.489 ;
     RECT  15.9 74.627 16.212 168.489 ;
     RECT  18.6 2.151 18.912 168.489 ;
     RECT  21.3 115.187 21.612 168.489 ;
     RECT  24 2.151 24.312 168.489 ;
     RECT  26.7 2.151 27.012 168.489 ;
     RECT  29.4 2.151 29.712 168.489 ;
     RECT  32.1 2.151 32.412 168.489 ;
     RECT  34.8 126.179 35.112 168.489 ;
     RECT  39.36 165.443 40.512 168.489 ;
     RECT  42.9 130.403 43.212 168.489 ;
     RECT  45.6 107.843 45.912 168.489 ;
     RECT  48.3 2.151 48.612 168.489 ;
     RECT  51 2.151 51.312 168.489 ;
     RECT  53.7 2.151 54.012 168.489 ;
     RECT  56.4 2.151 56.712 168.489 ;
     RECT  59.1 2.151 59.412 168.489 ;
     RECT  61.8 2.151 62.112 168.489 ;
     RECT  64.5 110.051 64.812 168.489 ;
     RECT  67.2 2.151 67.512 168.489 ;
     RECT  69.9 2.151 70.212 168.489 ;
     RECT  72.6 2.151 72.912 168.489 ;
     RECT  75.3 134.627 75.612 168.489 ;
     RECT  78 140.771 78.312 168.489 ;
     RECT  80.7 46.115 81.012 168.489 ;
     RECT  83.4 2.151 83.712 168.489 ;
     RECT  86.1 107.411 86.412 168.489 ;
     RECT  88.8 99.731 89.112 168.489 ;
     RECT  91.5 107.027 91.812 168.489 ;
     RECT  94.2 141.299 94.512 168.489 ;
     RECT  2.4 168.489 2.52 168.503 ;
     RECT  5.1 168.489 5.22 168.503 ;
     RECT  7.8 168.489 7.92 168.503 ;
     RECT  10.5 168.489 10.62 168.503 ;
     RECT  13.2 168.489 13.32 168.503 ;
     RECT  15.9 168.489 16.02 168.503 ;
     RECT  18.6 168.489 18.72 168.503 ;
     RECT  21.3 168.489 21.42 168.503 ;
     RECT  24 168.489 24.12 168.503 ;
     RECT  26.7 168.489 26.82 168.503 ;
     RECT  29.4 168.489 29.52 168.503 ;
     RECT  32.1 168.489 32.22 168.503 ;
     RECT  34.8 168.489 34.92 168.503 ;
     RECT  37.5 166.451 37.992 168.503 ;
     RECT  39.36 168.489 40.32 168.503 ;
     RECT  42.9 168.489 43.02 168.503 ;
     RECT  45.6 168.489 45.72 168.503 ;
     RECT  48.3 168.489 48.42 168.503 ;
     RECT  51 168.489 51.12 168.503 ;
     RECT  53.7 168.489 53.82 168.503 ;
     RECT  56.4 168.489 56.52 168.503 ;
     RECT  59.1 168.489 59.22 168.503 ;
     RECT  61.8 168.489 61.92 168.503 ;
     RECT  64.5 168.489 64.62 168.503 ;
     RECT  67.2 168.489 67.32 168.503 ;
     RECT  69.9 168.489 70.02 168.503 ;
     RECT  72.6 168.489 72.72 168.503 ;
     RECT  75.3 168.489 75.42 168.503 ;
     RECT  78 168.489 78.12 168.503 ;
     RECT  80.7 168.489 80.82 168.503 ;
     RECT  83.4 168.489 83.52 168.503 ;
     RECT  86.1 168.489 86.22 168.503 ;
     RECT  88.8 168.489 88.92 168.503 ;
     RECT  91.5 168.489 91.62 168.503 ;
     RECT  94.2 168.489 94.32 168.503 ;
     RECT  39.36 168.503 39.384 170.483 ;
     RECT  37.968 168.503 37.992 170.531 ;
  END
END qfd_landh0d8sn_151_EW_98x171
END LIBRARY
